VERSION 5.7 ;
BUSBITCHARS "[]" ;
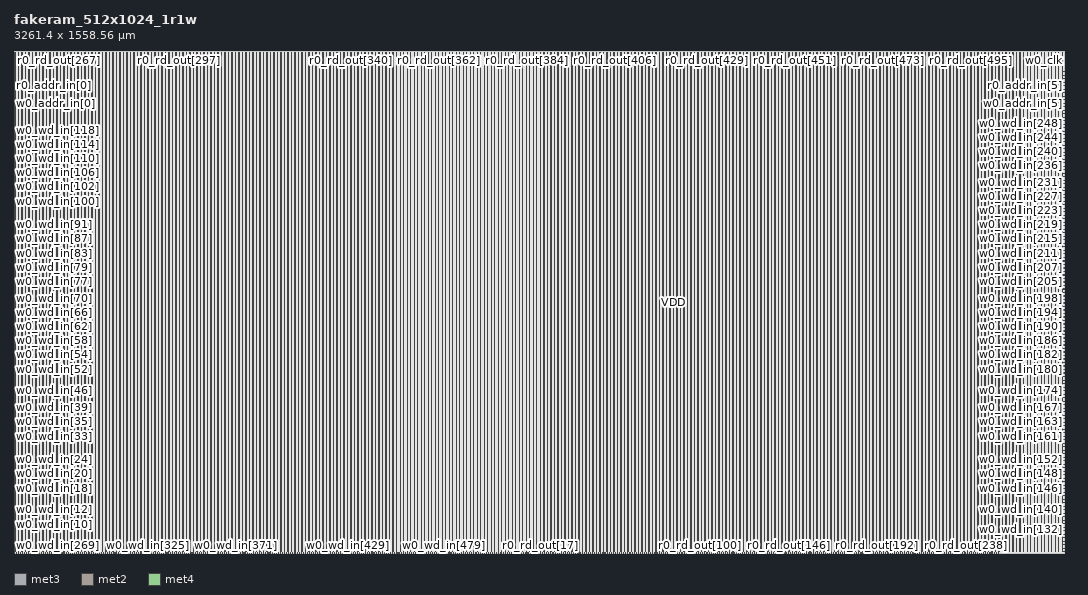
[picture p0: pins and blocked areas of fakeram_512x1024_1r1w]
MACRO fakeram_512x1024_1r1w
  FOREIGN fakeram_512x1024_1r1w 0 0 ;
  SYMMETRY X Y R90 ;
  SIZE 3261.400 BY 1558.560 ;
  CLASS BLOCK ;
  PIN w0_wd_in[0]
    DIRECTION INPUT ;
    USE SIGNAL ;
    SHAPE ABUTMENT ;
    PORT
      LAYER met3 ;
      RECT 0.000 3.930 0.900 4.230 ;
    END
  END w0_wd_in[0]
  PIN w0_wd_in[1]
    DIRECTION INPUT ;
    USE SIGNAL ;
    SHAPE ABUTMENT ;
    PORT
      LAYER met3 ;
      RECT 0.000 14.810 0.900 15.110 ;
    END
  END w0_wd_in[1]
  PIN w0_wd_in[2]
    DIRECTION INPUT ;
    USE SIGNAL ;
    SHAPE ABUTMENT ;
    PORT
      LAYER met3 ;
      RECT 0.000 25.690 0.900 25.990 ;
    END
  END w0_wd_in[2]
  PIN w0_wd_in[3]
    DIRECTION INPUT ;
    USE SIGNAL ;
    SHAPE ABUTMENT ;
    PORT
      LAYER met3 ;
      RECT 0.000 36.570 0.900 36.870 ;
    END
  END w0_wd_in[3]
  PIN w0_wd_in[4]
    DIRECTION INPUT ;
    USE SIGNAL ;
    SHAPE ABUTMENT ;
    PORT
      LAYER met3 ;
      RECT 0.000 47.450 0.900 47.750 ;
    END
  END w0_wd_in[4]
  PIN w0_wd_in[5]
    DIRECTION INPUT ;
    USE SIGNAL ;
    SHAPE ABUTMENT ;
    PORT
      LAYER met3 ;
      RECT 0.000 58.330 0.900 58.630 ;
    END
  END w0_wd_in[5]
  PIN w0_wd_in[6]
    DIRECTION INPUT ;
    USE SIGNAL ;
    SHAPE ABUTMENT ;
    PORT
      LAYER met3 ;
      RECT 0.000 69.210 0.900 69.510 ;
    END
  END w0_wd_in[6]
  PIN w0_wd_in[7]
    DIRECTION INPUT ;
    USE SIGNAL ;
    SHAPE ABUTMENT ;
    PORT
      LAYER met3 ;
      RECT 0.000 80.090 0.900 80.390 ;
    END
  END w0_wd_in[7]
  PIN w0_wd_in[8]
    DIRECTION INPUT ;
    USE SIGNAL ;
    SHAPE ABUTMENT ;
    PORT
      LAYER met3 ;
      RECT 0.000 90.970 0.900 91.270 ;
    END
  END w0_wd_in[8]
  PIN w0_wd_in[9]
    DIRECTION INPUT ;
    USE SIGNAL ;
    SHAPE ABUTMENT ;
    PORT
      LAYER met3 ;
      RECT 0.000 101.850 0.900 102.150 ;
    END
  END w0_wd_in[9]
  PIN w0_wd_in[10]
    DIRECTION INPUT ;
    USE SIGNAL ;
    SHAPE ABUTMENT ;
    PORT
      LAYER met3 ;
      RECT 0.000 112.730 0.900 113.030 ;
    END
  END w0_wd_in[10]
  PIN w0_wd_in[11]
    DIRECTION INPUT ;
    USE SIGNAL ;
    SHAPE ABUTMENT ;
    PORT
      LAYER met3 ;
      RECT 0.000 123.610 0.900 123.910 ;
    END
  END w0_wd_in[11]
  PIN w0_wd_in[12]
    DIRECTION INPUT ;
    USE SIGNAL ;
    SHAPE ABUTMENT ;
    PORT
      LAYER met3 ;
      RECT 0.000 134.490 0.900 134.790 ;
    END
  END w0_wd_in[12]
  PIN w0_wd_in[13]
    DIRECTION INPUT ;
    USE SIGNAL ;
    SHAPE ABUTMENT ;
    PORT
      LAYER met3 ;
      RECT 0.000 145.370 0.900 145.670 ;
    END
  END w0_wd_in[13]
  PIN w0_wd_in[14]
    DIRECTION INPUT ;
    USE SIGNAL ;
    SHAPE ABUTMENT ;
    PORT
      LAYER met3 ;
      RECT 0.000 156.250 0.900 156.550 ;
    END
  END w0_wd_in[14]
  PIN w0_wd_in[15]
    DIRECTION INPUT ;
    USE SIGNAL ;
    SHAPE ABUTMENT ;
    PORT
      LAYER met3 ;
      RECT 0.000 167.130 0.900 167.430 ;
    END
  END w0_wd_in[15]
  PIN w0_wd_in[16]
    DIRECTION INPUT ;
    USE SIGNAL ;
    SHAPE ABUTMENT ;
    PORT
      LAYER met3 ;
      RECT 0.000 178.010 0.900 178.310 ;
    END
  END w0_wd_in[16]
  PIN w0_wd_in[17]
    DIRECTION INPUT ;
    USE SIGNAL ;
    SHAPE ABUTMENT ;
    PORT
      LAYER met3 ;
      RECT 0.000 188.890 0.900 189.190 ;
    END
  END w0_wd_in[17]
  PIN w0_wd_in[18]
    DIRECTION INPUT ;
    USE SIGNAL ;
    SHAPE ABUTMENT ;
    PORT
      LAYER met3 ;
      RECT 0.000 199.770 0.900 200.070 ;
    END
  END w0_wd_in[18]
  PIN w0_wd_in[19]
    DIRECTION INPUT ;
    USE SIGNAL ;
    SHAPE ABUTMENT ;
    PORT
      LAYER met3 ;
      RECT 0.000 210.650 0.900 210.950 ;
    END
  END w0_wd_in[19]
  PIN w0_wd_in[20]
    DIRECTION INPUT ;
    USE SIGNAL ;
    SHAPE ABUTMENT ;
    PORT
      LAYER met3 ;
      RECT 0.000 221.530 0.900 221.830 ;
    END
  END w0_wd_in[20]
  PIN w0_wd_in[21]
    DIRECTION INPUT ;
    USE SIGNAL ;
    SHAPE ABUTMENT ;
    PORT
      LAYER met3 ;
      RECT 0.000 232.410 0.900 232.710 ;
    END
  END w0_wd_in[21]
  PIN w0_wd_in[22]
    DIRECTION INPUT ;
    USE SIGNAL ;
    SHAPE ABUTMENT ;
    PORT
      LAYER met3 ;
      RECT 0.000 243.290 0.900 243.590 ;
    END
  END w0_wd_in[22]
  PIN w0_wd_in[23]
    DIRECTION INPUT ;
    USE SIGNAL ;
    SHAPE ABUTMENT ;
    PORT
      LAYER met3 ;
      RECT 0.000 254.170 0.900 254.470 ;
    END
  END w0_wd_in[23]
  PIN w0_wd_in[24]
    DIRECTION INPUT ;
    USE SIGNAL ;
    SHAPE ABUTMENT ;
    PORT
      LAYER met3 ;
      RECT 0.000 265.050 0.900 265.350 ;
    END
  END w0_wd_in[24]
  PIN w0_wd_in[25]
    DIRECTION INPUT ;
    USE SIGNAL ;
    SHAPE ABUTMENT ;
    PORT
      LAYER met3 ;
      RECT 0.000 275.930 0.900 276.230 ;
    END
  END w0_wd_in[25]
  PIN w0_wd_in[26]
    DIRECTION INPUT ;
    USE SIGNAL ;
    SHAPE ABUTMENT ;
    PORT
      LAYER met3 ;
      RECT 0.000 286.810 0.900 287.110 ;
    END
  END w0_wd_in[26]
  PIN w0_wd_in[27]
    DIRECTION INPUT ;
    USE SIGNAL ;
    SHAPE ABUTMENT ;
    PORT
      LAYER met3 ;
      RECT 0.000 297.690 0.900 297.990 ;
    END
  END w0_wd_in[27]
  PIN w0_wd_in[28]
    DIRECTION INPUT ;
    USE SIGNAL ;
    SHAPE ABUTMENT ;
    PORT
      LAYER met3 ;
      RECT 0.000 308.570 0.900 308.870 ;
    END
  END w0_wd_in[28]
  PIN w0_wd_in[29]
    DIRECTION INPUT ;
    USE SIGNAL ;
    SHAPE ABUTMENT ;
    PORT
      LAYER met3 ;
      RECT 0.000 319.450 0.900 319.750 ;
    END
  END w0_wd_in[29]
  PIN w0_wd_in[30]
    DIRECTION INPUT ;
    USE SIGNAL ;
    SHAPE ABUTMENT ;
    PORT
      LAYER met3 ;
      RECT 0.000 330.330 0.900 330.630 ;
    END
  END w0_wd_in[30]
  PIN w0_wd_in[31]
    DIRECTION INPUT ;
    USE SIGNAL ;
    SHAPE ABUTMENT ;
    PORT
      LAYER met3 ;
      RECT 0.000 341.210 0.900 341.510 ;
    END
  END w0_wd_in[31]
  PIN w0_wd_in[32]
    DIRECTION INPUT ;
    USE SIGNAL ;
    SHAPE ABUTMENT ;
    PORT
      LAYER met3 ;
      RECT 0.000 352.090 0.900 352.390 ;
    END
  END w0_wd_in[32]
  PIN w0_wd_in[33]
    DIRECTION INPUT ;
    USE SIGNAL ;
    SHAPE ABUTMENT ;
    PORT
      LAYER met3 ;
      RECT 0.000 362.970 0.900 363.270 ;
    END
  END w0_wd_in[33]
  PIN w0_wd_in[34]
    DIRECTION INPUT ;
    USE SIGNAL ;
    SHAPE ABUTMENT ;
    PORT
      LAYER met3 ;
      RECT 0.000 373.850 0.900 374.150 ;
    END
  END w0_wd_in[34]
  PIN w0_wd_in[35]
    DIRECTION INPUT ;
    USE SIGNAL ;
    SHAPE ABUTMENT ;
    PORT
      LAYER met3 ;
      RECT 0.000 384.730 0.900 385.030 ;
    END
  END w0_wd_in[35]
  PIN w0_wd_in[36]
    DIRECTION INPUT ;
    USE SIGNAL ;
    SHAPE ABUTMENT ;
    PORT
      LAYER met3 ;
      RECT 0.000 395.610 0.900 395.910 ;
    END
  END w0_wd_in[36]
  PIN w0_wd_in[37]
    DIRECTION INPUT ;
    USE SIGNAL ;
    SHAPE ABUTMENT ;
    PORT
      LAYER met3 ;
      RECT 0.000 406.490 0.900 406.790 ;
    END
  END w0_wd_in[37]
  PIN w0_wd_in[38]
    DIRECTION INPUT ;
    USE SIGNAL ;
    SHAPE ABUTMENT ;
    PORT
      LAYER met3 ;
      RECT 0.000 417.370 0.900 417.670 ;
    END
  END w0_wd_in[38]
  PIN w0_wd_in[39]
    DIRECTION INPUT ;
    USE SIGNAL ;
    SHAPE ABUTMENT ;
    PORT
      LAYER met3 ;
      RECT 0.000 428.250 0.900 428.550 ;
    END
  END w0_wd_in[39]
  PIN w0_wd_in[40]
    DIRECTION INPUT ;
    USE SIGNAL ;
    SHAPE ABUTMENT ;
    PORT
      LAYER met3 ;
      RECT 0.000 439.130 0.900 439.430 ;
    END
  END w0_wd_in[40]
  PIN w0_wd_in[41]
    DIRECTION INPUT ;
    USE SIGNAL ;
    SHAPE ABUTMENT ;
    PORT
      LAYER met3 ;
      RECT 0.000 450.010 0.900 450.310 ;
    END
  END w0_wd_in[41]
  PIN w0_wd_in[42]
    DIRECTION INPUT ;
    USE SIGNAL ;
    SHAPE ABUTMENT ;
    PORT
      LAYER met3 ;
      RECT 0.000 460.890 0.900 461.190 ;
    END
  END w0_wd_in[42]
  PIN w0_wd_in[43]
    DIRECTION INPUT ;
    USE SIGNAL ;
    SHAPE ABUTMENT ;
    PORT
      LAYER met3 ;
      RECT 0.000 471.770 0.900 472.070 ;
    END
  END w0_wd_in[43]
  PIN w0_wd_in[44]
    DIRECTION INPUT ;
    USE SIGNAL ;
    SHAPE ABUTMENT ;
    PORT
      LAYER met3 ;
      RECT 0.000 482.650 0.900 482.950 ;
    END
  END w0_wd_in[44]
  PIN w0_wd_in[45]
    DIRECTION INPUT ;
    USE SIGNAL ;
    SHAPE ABUTMENT ;
    PORT
      LAYER met3 ;
      RECT 0.000 493.530 0.900 493.830 ;
    END
  END w0_wd_in[45]
  PIN w0_wd_in[46]
    DIRECTION INPUT ;
    USE SIGNAL ;
    SHAPE ABUTMENT ;
    PORT
      LAYER met3 ;
      RECT 0.000 504.410 0.900 504.710 ;
    END
  END w0_wd_in[46]
  PIN w0_wd_in[47]
    DIRECTION INPUT ;
    USE SIGNAL ;
    SHAPE ABUTMENT ;
    PORT
      LAYER met3 ;
      RECT 0.000 515.290 0.900 515.590 ;
    END
  END w0_wd_in[47]
  PIN w0_wd_in[48]
    DIRECTION INPUT ;
    USE SIGNAL ;
    SHAPE ABUTMENT ;
    PORT
      LAYER met3 ;
      RECT 0.000 526.170 0.900 526.470 ;
    END
  END w0_wd_in[48]
  PIN w0_wd_in[49]
    DIRECTION INPUT ;
    USE SIGNAL ;
    SHAPE ABUTMENT ;
    PORT
      LAYER met3 ;
      RECT 0.000 537.050 0.900 537.350 ;
    END
  END w0_wd_in[49]
  PIN w0_wd_in[50]
    DIRECTION INPUT ;
    USE SIGNAL ;
    SHAPE ABUTMENT ;
    PORT
      LAYER met3 ;
      RECT 0.000 547.930 0.900 548.230 ;
    END
  END w0_wd_in[50]
  PIN w0_wd_in[51]
    DIRECTION INPUT ;
    USE SIGNAL ;
    SHAPE ABUTMENT ;
    PORT
      LAYER met3 ;
      RECT 0.000 558.810 0.900 559.110 ;
    END
  END w0_wd_in[51]
  PIN w0_wd_in[52]
    DIRECTION INPUT ;
    USE SIGNAL ;
    SHAPE ABUTMENT ;
    PORT
      LAYER met3 ;
      RECT 0.000 569.690 0.900 569.990 ;
    END
  END w0_wd_in[52]
  PIN w0_wd_in[53]
    DIRECTION INPUT ;
    USE SIGNAL ;
    SHAPE ABUTMENT ;
    PORT
      LAYER met3 ;
      RECT 0.000 580.570 0.900 580.870 ;
    END
  END w0_wd_in[53]
  PIN w0_wd_in[54]
    DIRECTION INPUT ;
    USE SIGNAL ;
    SHAPE ABUTMENT ;
    PORT
      LAYER met3 ;
      RECT 0.000 591.450 0.900 591.750 ;
    END
  END w0_wd_in[54]
  PIN w0_wd_in[55]
    DIRECTION INPUT ;
    USE SIGNAL ;
    SHAPE ABUTMENT ;
    PORT
      LAYER met3 ;
      RECT 0.000 602.330 0.900 602.630 ;
    END
  END w0_wd_in[55]
  PIN w0_wd_in[56]
    DIRECTION INPUT ;
    USE SIGNAL ;
    SHAPE ABUTMENT ;
    PORT
      LAYER met3 ;
      RECT 0.000 613.210 0.900 613.510 ;
    END
  END w0_wd_in[56]
  PIN w0_wd_in[57]
    DIRECTION INPUT ;
    USE SIGNAL ;
    SHAPE ABUTMENT ;
    PORT
      LAYER met3 ;
      RECT 0.000 624.090 0.900 624.390 ;
    END
  END w0_wd_in[57]
  PIN w0_wd_in[58]
    DIRECTION INPUT ;
    USE SIGNAL ;
    SHAPE ABUTMENT ;
    PORT
      LAYER met3 ;
      RECT 0.000 634.970 0.900 635.270 ;
    END
  END w0_wd_in[58]
  PIN w0_wd_in[59]
    DIRECTION INPUT ;
    USE SIGNAL ;
    SHAPE ABUTMENT ;
    PORT
      LAYER met3 ;
      RECT 0.000 645.850 0.900 646.150 ;
    END
  END w0_wd_in[59]
  PIN w0_wd_in[60]
    DIRECTION INPUT ;
    USE SIGNAL ;
    SHAPE ABUTMENT ;
    PORT
      LAYER met3 ;
      RECT 0.000 656.730 0.900 657.030 ;
    END
  END w0_wd_in[60]
  PIN w0_wd_in[61]
    DIRECTION INPUT ;
    USE SIGNAL ;
    SHAPE ABUTMENT ;
    PORT
      LAYER met3 ;
      RECT 0.000 667.610 0.900 667.910 ;
    END
  END w0_wd_in[61]
  PIN w0_wd_in[62]
    DIRECTION INPUT ;
    USE SIGNAL ;
    SHAPE ABUTMENT ;
    PORT
      LAYER met3 ;
      RECT 0.000 678.490 0.900 678.790 ;
    END
  END w0_wd_in[62]
  PIN w0_wd_in[63]
    DIRECTION INPUT ;
    USE SIGNAL ;
    SHAPE ABUTMENT ;
    PORT
      LAYER met3 ;
      RECT 0.000 689.370 0.900 689.670 ;
    END
  END w0_wd_in[63]
  PIN w0_wd_in[64]
    DIRECTION INPUT ;
    USE SIGNAL ;
    SHAPE ABUTMENT ;
    PORT
      LAYER met3 ;
      RECT 0.000 700.250 0.900 700.550 ;
    END
  END w0_wd_in[64]
  PIN w0_wd_in[65]
    DIRECTION INPUT ;
    USE SIGNAL ;
    SHAPE ABUTMENT ;
    PORT
      LAYER met3 ;
      RECT 0.000 711.130 0.900 711.430 ;
    END
  END w0_wd_in[65]
  PIN w0_wd_in[66]
    DIRECTION INPUT ;
    USE SIGNAL ;
    SHAPE ABUTMENT ;
    PORT
      LAYER met3 ;
      RECT 0.000 722.010 0.900 722.310 ;
    END
  END w0_wd_in[66]
  PIN w0_wd_in[67]
    DIRECTION INPUT ;
    USE SIGNAL ;
    SHAPE ABUTMENT ;
    PORT
      LAYER met3 ;
      RECT 0.000 732.890 0.900 733.190 ;
    END
  END w0_wd_in[67]
  PIN w0_wd_in[68]
    DIRECTION INPUT ;
    USE SIGNAL ;
    SHAPE ABUTMENT ;
    PORT
      LAYER met3 ;
      RECT 0.000 743.770 0.900 744.070 ;
    END
  END w0_wd_in[68]
  PIN w0_wd_in[69]
    DIRECTION INPUT ;
    USE SIGNAL ;
    SHAPE ABUTMENT ;
    PORT
      LAYER met3 ;
      RECT 0.000 754.650 0.900 754.950 ;
    END
  END w0_wd_in[69]
  PIN w0_wd_in[70]
    DIRECTION INPUT ;
    USE SIGNAL ;
    SHAPE ABUTMENT ;
    PORT
      LAYER met3 ;
      RECT 0.000 765.530 0.900 765.830 ;
    END
  END w0_wd_in[70]
  PIN w0_wd_in[71]
    DIRECTION INPUT ;
    USE SIGNAL ;
    SHAPE ABUTMENT ;
    PORT
      LAYER met3 ;
      RECT 0.000 776.410 0.900 776.710 ;
    END
  END w0_wd_in[71]
  PIN w0_wd_in[72]
    DIRECTION INPUT ;
    USE SIGNAL ;
    SHAPE ABUTMENT ;
    PORT
      LAYER met3 ;
      RECT 0.000 787.290 0.900 787.590 ;
    END
  END w0_wd_in[72]
  PIN w0_wd_in[73]
    DIRECTION INPUT ;
    USE SIGNAL ;
    SHAPE ABUTMENT ;
    PORT
      LAYER met3 ;
      RECT 0.000 798.170 0.900 798.470 ;
    END
  END w0_wd_in[73]
  PIN w0_wd_in[74]
    DIRECTION INPUT ;
    USE SIGNAL ;
    SHAPE ABUTMENT ;
    PORT
      LAYER met3 ;
      RECT 0.000 809.050 0.900 809.350 ;
    END
  END w0_wd_in[74]
  PIN w0_wd_in[75]
    DIRECTION INPUT ;
    USE SIGNAL ;
    SHAPE ABUTMENT ;
    PORT
      LAYER met3 ;
      RECT 0.000 819.930 0.900 820.230 ;
    END
  END w0_wd_in[75]
  PIN w0_wd_in[76]
    DIRECTION INPUT ;
    USE SIGNAL ;
    SHAPE ABUTMENT ;
    PORT
      LAYER met3 ;
      RECT 0.000 830.810 0.900 831.110 ;
    END
  END w0_wd_in[76]
  PIN w0_wd_in[77]
    DIRECTION INPUT ;
    USE SIGNAL ;
    SHAPE ABUTMENT ;
    PORT
      LAYER met3 ;
      RECT 0.000 841.690 0.900 841.990 ;
    END
  END w0_wd_in[77]
  PIN w0_wd_in[78]
    DIRECTION INPUT ;
    USE SIGNAL ;
    SHAPE ABUTMENT ;
    PORT
      LAYER met3 ;
      RECT 0.000 852.570 0.900 852.870 ;
    END
  END w0_wd_in[78]
  PIN w0_wd_in[79]
    DIRECTION INPUT ;
    USE SIGNAL ;
    SHAPE ABUTMENT ;
    PORT
      LAYER met3 ;
      RECT 0.000 863.450 0.900 863.750 ;
    END
  END w0_wd_in[79]
  PIN w0_wd_in[80]
    DIRECTION INPUT ;
    USE SIGNAL ;
    SHAPE ABUTMENT ;
    PORT
      LAYER met3 ;
      RECT 0.000 874.330 0.900 874.630 ;
    END
  END w0_wd_in[80]
  PIN w0_wd_in[81]
    DIRECTION INPUT ;
    USE SIGNAL ;
    SHAPE ABUTMENT ;
    PORT
      LAYER met3 ;
      RECT 0.000 885.210 0.900 885.510 ;
    END
  END w0_wd_in[81]
  PIN w0_wd_in[82]
    DIRECTION INPUT ;
    USE SIGNAL ;
    SHAPE ABUTMENT ;
    PORT
      LAYER met3 ;
      RECT 0.000 896.090 0.900 896.390 ;
    END
  END w0_wd_in[82]
  PIN w0_wd_in[83]
    DIRECTION INPUT ;
    USE SIGNAL ;
    SHAPE ABUTMENT ;
    PORT
      LAYER met3 ;
      RECT 0.000 906.970 0.900 907.270 ;
    END
  END w0_wd_in[83]
  PIN w0_wd_in[84]
    DIRECTION INPUT ;
    USE SIGNAL ;
    SHAPE ABUTMENT ;
    PORT
      LAYER met3 ;
      RECT 0.000 917.850 0.900 918.150 ;
    END
  END w0_wd_in[84]
  PIN w0_wd_in[85]
    DIRECTION INPUT ;
    USE SIGNAL ;
    SHAPE ABUTMENT ;
    PORT
      LAYER met3 ;
      RECT 0.000 928.730 0.900 929.030 ;
    END
  END w0_wd_in[85]
  PIN w0_wd_in[86]
    DIRECTION INPUT ;
    USE SIGNAL ;
    SHAPE ABUTMENT ;
    PORT
      LAYER met3 ;
      RECT 0.000 939.610 0.900 939.910 ;
    END
  END w0_wd_in[86]
  PIN w0_wd_in[87]
    DIRECTION INPUT ;
    USE SIGNAL ;
    SHAPE ABUTMENT ;
    PORT
      LAYER met3 ;
      RECT 0.000 950.490 0.900 950.790 ;
    END
  END w0_wd_in[87]
  PIN w0_wd_in[88]
    DIRECTION INPUT ;
    USE SIGNAL ;
    SHAPE ABUTMENT ;
    PORT
      LAYER met3 ;
      RECT 0.000 961.370 0.900 961.670 ;
    END
  END w0_wd_in[88]
  PIN w0_wd_in[89]
    DIRECTION INPUT ;
    USE SIGNAL ;
    SHAPE ABUTMENT ;
    PORT
      LAYER met3 ;
      RECT 0.000 972.250 0.900 972.550 ;
    END
  END w0_wd_in[89]
  PIN w0_wd_in[90]
    DIRECTION INPUT ;
    USE SIGNAL ;
    SHAPE ABUTMENT ;
    PORT
      LAYER met3 ;
      RECT 0.000 983.130 0.900 983.430 ;
    END
  END w0_wd_in[90]
  PIN w0_wd_in[91]
    DIRECTION INPUT ;
    USE SIGNAL ;
    SHAPE ABUTMENT ;
    PORT
      LAYER met3 ;
      RECT 0.000 994.010 0.900 994.310 ;
    END
  END w0_wd_in[91]
  PIN w0_wd_in[92]
    DIRECTION INPUT ;
    USE SIGNAL ;
    SHAPE ABUTMENT ;
    PORT
      LAYER met3 ;
      RECT 0.000 1004.890 0.900 1005.190 ;
    END
  END w0_wd_in[92]
  PIN w0_wd_in[93]
    DIRECTION INPUT ;
    USE SIGNAL ;
    SHAPE ABUTMENT ;
    PORT
      LAYER met3 ;
      RECT 0.000 1015.770 0.900 1016.070 ;
    END
  END w0_wd_in[93]
  PIN w0_wd_in[94]
    DIRECTION INPUT ;
    USE SIGNAL ;
    SHAPE ABUTMENT ;
    PORT
      LAYER met3 ;
      RECT 0.000 1026.650 0.900 1026.950 ;
    END
  END w0_wd_in[94]
  PIN w0_wd_in[95]
    DIRECTION INPUT ;
    USE SIGNAL ;
    SHAPE ABUTMENT ;
    PORT
      LAYER met3 ;
      RECT 0.000 1037.530 0.900 1037.830 ;
    END
  END w0_wd_in[95]
  PIN w0_wd_in[96]
    DIRECTION INPUT ;
    USE SIGNAL ;
    SHAPE ABUTMENT ;
    PORT
      LAYER met3 ;
      RECT 0.000 1048.410 0.900 1048.710 ;
    END
  END w0_wd_in[96]
  PIN w0_wd_in[97]
    DIRECTION INPUT ;
    USE SIGNAL ;
    SHAPE ABUTMENT ;
    PORT
      LAYER met3 ;
      RECT 0.000 1059.290 0.900 1059.590 ;
    END
  END w0_wd_in[97]
  PIN w0_wd_in[98]
    DIRECTION INPUT ;
    USE SIGNAL ;
    SHAPE ABUTMENT ;
    PORT
      LAYER met3 ;
      RECT 0.000 1070.170 0.900 1070.470 ;
    END
  END w0_wd_in[98]
  PIN w0_wd_in[99]
    DIRECTION INPUT ;
    USE SIGNAL ;
    SHAPE ABUTMENT ;
    PORT
      LAYER met3 ;
      RECT 0.000 1081.050 0.900 1081.350 ;
    END
  END w0_wd_in[99]
  PIN w0_wd_in[100]
    DIRECTION INPUT ;
    USE SIGNAL ;
    SHAPE ABUTMENT ;
    PORT
      LAYER met3 ;
      RECT 0.000 1091.930 0.900 1092.230 ;
    END
  END w0_wd_in[100]
  PIN w0_wd_in[101]
    DIRECTION INPUT ;
    USE SIGNAL ;
    SHAPE ABUTMENT ;
    PORT
      LAYER met3 ;
      RECT 0.000 1102.810 0.900 1103.110 ;
    END
  END w0_wd_in[101]
  PIN w0_wd_in[102]
    DIRECTION INPUT ;
    USE SIGNAL ;
    SHAPE ABUTMENT ;
    PORT
      LAYER met3 ;
      RECT 0.000 1113.690 0.900 1113.990 ;
    END
  END w0_wd_in[102]
  PIN w0_wd_in[103]
    DIRECTION INPUT ;
    USE SIGNAL ;
    SHAPE ABUTMENT ;
    PORT
      LAYER met3 ;
      RECT 0.000 1124.570 0.900 1124.870 ;
    END
  END w0_wd_in[103]
  PIN w0_wd_in[104]
    DIRECTION INPUT ;
    USE SIGNAL ;
    SHAPE ABUTMENT ;
    PORT
      LAYER met3 ;
      RECT 0.000 1135.450 0.900 1135.750 ;
    END
  END w0_wd_in[104]
  PIN w0_wd_in[105]
    DIRECTION INPUT ;
    USE SIGNAL ;
    SHAPE ABUTMENT ;
    PORT
      LAYER met3 ;
      RECT 0.000 1146.330 0.900 1146.630 ;
    END
  END w0_wd_in[105]
  PIN w0_wd_in[106]
    DIRECTION INPUT ;
    USE SIGNAL ;
    SHAPE ABUTMENT ;
    PORT
      LAYER met3 ;
      RECT 0.000 1157.210 0.900 1157.510 ;
    END
  END w0_wd_in[106]
  PIN w0_wd_in[107]
    DIRECTION INPUT ;
    USE SIGNAL ;
    SHAPE ABUTMENT ;
    PORT
      LAYER met3 ;
      RECT 0.000 1168.090 0.900 1168.390 ;
    END
  END w0_wd_in[107]
  PIN w0_wd_in[108]
    DIRECTION INPUT ;
    USE SIGNAL ;
    SHAPE ABUTMENT ;
    PORT
      LAYER met3 ;
      RECT 0.000 1178.970 0.900 1179.270 ;
    END
  END w0_wd_in[108]
  PIN w0_wd_in[109]
    DIRECTION INPUT ;
    USE SIGNAL ;
    SHAPE ABUTMENT ;
    PORT
      LAYER met3 ;
      RECT 0.000 1189.850 0.900 1190.150 ;
    END
  END w0_wd_in[109]
  PIN w0_wd_in[110]
    DIRECTION INPUT ;
    USE SIGNAL ;
    SHAPE ABUTMENT ;
    PORT
      LAYER met3 ;
      RECT 0.000 1200.730 0.900 1201.030 ;
    END
  END w0_wd_in[110]
  PIN w0_wd_in[111]
    DIRECTION INPUT ;
    USE SIGNAL ;
    SHAPE ABUTMENT ;
    PORT
      LAYER met3 ;
      RECT 0.000 1211.610 0.900 1211.910 ;
    END
  END w0_wd_in[111]
  PIN w0_wd_in[112]
    DIRECTION INPUT ;
    USE SIGNAL ;
    SHAPE ABUTMENT ;
    PORT
      LAYER met3 ;
      RECT 0.000 1222.490 0.900 1222.790 ;
    END
  END w0_wd_in[112]
  PIN w0_wd_in[113]
    DIRECTION INPUT ;
    USE SIGNAL ;
    SHAPE ABUTMENT ;
    PORT
      LAYER met3 ;
      RECT 0.000 1233.370 0.900 1233.670 ;
    END
  END w0_wd_in[113]
  PIN w0_wd_in[114]
    DIRECTION INPUT ;
    USE SIGNAL ;
    SHAPE ABUTMENT ;
    PORT
      LAYER met3 ;
      RECT 0.000 1244.250 0.900 1244.550 ;
    END
  END w0_wd_in[114]
  PIN w0_wd_in[115]
    DIRECTION INPUT ;
    USE SIGNAL ;
    SHAPE ABUTMENT ;
    PORT
      LAYER met3 ;
      RECT 0.000 1255.130 0.900 1255.430 ;
    END
  END w0_wd_in[115]
  PIN w0_wd_in[116]
    DIRECTION INPUT ;
    USE SIGNAL ;
    SHAPE ABUTMENT ;
    PORT
      LAYER met3 ;
      RECT 0.000 1266.010 0.900 1266.310 ;
    END
  END w0_wd_in[116]
  PIN w0_wd_in[117]
    DIRECTION INPUT ;
    USE SIGNAL ;
    SHAPE ABUTMENT ;
    PORT
      LAYER met3 ;
      RECT 0.000 1276.890 0.900 1277.190 ;
    END
  END w0_wd_in[117]
  PIN w0_wd_in[118]
    DIRECTION INPUT ;
    USE SIGNAL ;
    SHAPE ABUTMENT ;
    PORT
      LAYER met3 ;
      RECT 0.000 1287.770 0.900 1288.070 ;
    END
  END w0_wd_in[118]
  PIN w0_wd_in[119]
    DIRECTION INPUT ;
    USE SIGNAL ;
    SHAPE ABUTMENT ;
    PORT
      LAYER met3 ;
      RECT 0.000 1298.650 0.900 1298.950 ;
    END
  END w0_wd_in[119]
  PIN w0_wd_in[120]
    DIRECTION INPUT ;
    USE SIGNAL ;
    SHAPE ABUTMENT ;
    PORT
      LAYER met3 ;
      RECT 0.000 1309.530 0.900 1309.830 ;
    END
  END w0_wd_in[120]
  PIN w0_wd_in[121]
    DIRECTION INPUT ;
    USE SIGNAL ;
    SHAPE ABUTMENT ;
    PORT
      LAYER met3 ;
      RECT 0.000 1320.410 0.900 1320.710 ;
    END
  END w0_wd_in[121]
  PIN w0_wd_in[122]
    DIRECTION INPUT ;
    USE SIGNAL ;
    SHAPE ABUTMENT ;
    PORT
      LAYER met3 ;
      RECT 0.000 1331.290 0.900 1331.590 ;
    END
  END w0_wd_in[122]
  PIN w0_wd_in[123]
    DIRECTION INPUT ;
    USE SIGNAL ;
    SHAPE ABUTMENT ;
    PORT
      LAYER met3 ;
      RECT 0.000 1342.170 0.900 1342.470 ;
    END
  END w0_wd_in[123]
  PIN w0_wd_in[124]
    DIRECTION INPUT ;
    USE SIGNAL ;
    SHAPE ABUTMENT ;
    PORT
      LAYER met3 ;
      RECT 0.000 1353.050 0.900 1353.350 ;
    END
  END w0_wd_in[124]
  PIN w0_wd_in[125]
    DIRECTION INPUT ;
    USE SIGNAL ;
    SHAPE ABUTMENT ;
    PORT
      LAYER met3 ;
      RECT 0.000 1363.930 0.900 1364.230 ;
    END
  END w0_wd_in[125]
  PIN w0_wd_in[126]
    DIRECTION INPUT ;
    USE SIGNAL ;
    SHAPE ABUTMENT ;
    PORT
      LAYER met3 ;
      RECT 0.000 1374.810 0.900 1375.110 ;
    END
  END w0_wd_in[126]
  PIN w0_wd_in[127]
    DIRECTION INPUT ;
    USE SIGNAL ;
    SHAPE ABUTMENT ;
    PORT
      LAYER met3 ;
      RECT 0.000 1385.690 0.900 1385.990 ;
    END
  END w0_wd_in[127]
  PIN w0_wd_in[128]
    DIRECTION INPUT ;
    USE SIGNAL ;
    SHAPE ABUTMENT ;
    PORT
      LAYER met3 ;
      RECT 3260.500 3.930 3261.400 4.230 ;
    END
  END w0_wd_in[128]
  PIN w0_wd_in[129]
    DIRECTION INPUT ;
    USE SIGNAL ;
    SHAPE ABUTMENT ;
    PORT
      LAYER met3 ;
      RECT 3260.500 14.810 3261.400 15.110 ;
    END
  END w0_wd_in[129]
  PIN w0_wd_in[130]
    DIRECTION INPUT ;
    USE SIGNAL ;
    SHAPE ABUTMENT ;
    PORT
      LAYER met3 ;
      RECT 3260.500 25.690 3261.400 25.990 ;
    END
  END w0_wd_in[130]
  PIN w0_wd_in[131]
    DIRECTION INPUT ;
    USE SIGNAL ;
    SHAPE ABUTMENT ;
    PORT
      LAYER met3 ;
      RECT 3260.500 36.570 3261.400 36.870 ;
    END
  END w0_wd_in[131]
  PIN w0_wd_in[132]
    DIRECTION INPUT ;
    USE SIGNAL ;
    SHAPE ABUTMENT ;
    PORT
      LAYER met3 ;
      RECT 3260.500 47.450 3261.400 47.750 ;
    END
  END w0_wd_in[132]
  PIN w0_wd_in[133]
    DIRECTION INPUT ;
    USE SIGNAL ;
    SHAPE ABUTMENT ;
    PORT
      LAYER met3 ;
      RECT 3260.500 58.330 3261.400 58.630 ;
    END
  END w0_wd_in[133]
  PIN w0_wd_in[134]
    DIRECTION INPUT ;
    USE SIGNAL ;
    SHAPE ABUTMENT ;
    PORT
      LAYER met3 ;
      RECT 3260.500 69.210 3261.400 69.510 ;
    END
  END w0_wd_in[134]
  PIN w0_wd_in[135]
    DIRECTION INPUT ;
    USE SIGNAL ;
    SHAPE ABUTMENT ;
    PORT
      LAYER met3 ;
      RECT 3260.500 80.090 3261.400 80.390 ;
    END
  END w0_wd_in[135]
  PIN w0_wd_in[136]
    DIRECTION INPUT ;
    USE SIGNAL ;
    SHAPE ABUTMENT ;
    PORT
      LAYER met3 ;
      RECT 3260.500 90.970 3261.400 91.270 ;
    END
  END w0_wd_in[136]
  PIN w0_wd_in[137]
    DIRECTION INPUT ;
    USE SIGNAL ;
    SHAPE ABUTMENT ;
    PORT
      LAYER met3 ;
      RECT 3260.500 101.850 3261.400 102.150 ;
    END
  END w0_wd_in[137]
  PIN w0_wd_in[138]
    DIRECTION INPUT ;
    USE SIGNAL ;
    SHAPE ABUTMENT ;
    PORT
      LAYER met3 ;
      RECT 3260.500 112.730 3261.400 113.030 ;
    END
  END w0_wd_in[138]
  PIN w0_wd_in[139]
    DIRECTION INPUT ;
    USE SIGNAL ;
    SHAPE ABUTMENT ;
    PORT
      LAYER met3 ;
      RECT 3260.500 123.610 3261.400 123.910 ;
    END
  END w0_wd_in[139]
  PIN w0_wd_in[140]
    DIRECTION INPUT ;
    USE SIGNAL ;
    SHAPE ABUTMENT ;
    PORT
      LAYER met3 ;
      RECT 3260.500 134.490 3261.400 134.790 ;
    END
  END w0_wd_in[140]
  PIN w0_wd_in[141]
    DIRECTION INPUT ;
    USE SIGNAL ;
    SHAPE ABUTMENT ;
    PORT
      LAYER met3 ;
      RECT 3260.500 145.370 3261.400 145.670 ;
    END
  END w0_wd_in[141]
  PIN w0_wd_in[142]
    DIRECTION INPUT ;
    USE SIGNAL ;
    SHAPE ABUTMENT ;
    PORT
      LAYER met3 ;
      RECT 3260.500 156.250 3261.400 156.550 ;
    END
  END w0_wd_in[142]
  PIN w0_wd_in[143]
    DIRECTION INPUT ;
    USE SIGNAL ;
    SHAPE ABUTMENT ;
    PORT
      LAYER met3 ;
      RECT 3260.500 167.130 3261.400 167.430 ;
    END
  END w0_wd_in[143]
  PIN w0_wd_in[144]
    DIRECTION INPUT ;
    USE SIGNAL ;
    SHAPE ABUTMENT ;
    PORT
      LAYER met3 ;
      RECT 3260.500 178.010 3261.400 178.310 ;
    END
  END w0_wd_in[144]
  PIN w0_wd_in[145]
    DIRECTION INPUT ;
    USE SIGNAL ;
    SHAPE ABUTMENT ;
    PORT
      LAYER met3 ;
      RECT 3260.500 188.890 3261.400 189.190 ;
    END
  END w0_wd_in[145]
  PIN w0_wd_in[146]
    DIRECTION INPUT ;
    USE SIGNAL ;
    SHAPE ABUTMENT ;
    PORT
      LAYER met3 ;
      RECT 3260.500 199.770 3261.400 200.070 ;
    END
  END w0_wd_in[146]
  PIN w0_wd_in[147]
    DIRECTION INPUT ;
    USE SIGNAL ;
    SHAPE ABUTMENT ;
    PORT
      LAYER met3 ;
      RECT 3260.500 210.650 3261.400 210.950 ;
    END
  END w0_wd_in[147]
  PIN w0_wd_in[148]
    DIRECTION INPUT ;
    USE SIGNAL ;
    SHAPE ABUTMENT ;
    PORT
      LAYER met3 ;
      RECT 3260.500 221.530 3261.400 221.830 ;
    END
  END w0_wd_in[148]
  PIN w0_wd_in[149]
    DIRECTION INPUT ;
    USE SIGNAL ;
    SHAPE ABUTMENT ;
    PORT
      LAYER met3 ;
      RECT 3260.500 232.410 3261.400 232.710 ;
    END
  END w0_wd_in[149]
  PIN w0_wd_in[150]
    DIRECTION INPUT ;
    USE SIGNAL ;
    SHAPE ABUTMENT ;
    PORT
      LAYER met3 ;
      RECT 3260.500 243.290 3261.400 243.590 ;
    END
  END w0_wd_in[150]
  PIN w0_wd_in[151]
    DIRECTION INPUT ;
    USE SIGNAL ;
    SHAPE ABUTMENT ;
    PORT
      LAYER met3 ;
      RECT 3260.500 254.170 3261.400 254.470 ;
    END
  END w0_wd_in[151]
  PIN w0_wd_in[152]
    DIRECTION INPUT ;
    USE SIGNAL ;
    SHAPE ABUTMENT ;
    PORT
      LAYER met3 ;
      RECT 3260.500 265.050 3261.400 265.350 ;
    END
  END w0_wd_in[152]
  PIN w0_wd_in[153]
    DIRECTION INPUT ;
    USE SIGNAL ;
    SHAPE ABUTMENT ;
    PORT
      LAYER met3 ;
      RECT 3260.500 275.930 3261.400 276.230 ;
    END
  END w0_wd_in[153]
  PIN w0_wd_in[154]
    DIRECTION INPUT ;
    USE SIGNAL ;
    SHAPE ABUTMENT ;
    PORT
      LAYER met3 ;
      RECT 3260.500 286.810 3261.400 287.110 ;
    END
  END w0_wd_in[154]
  PIN w0_wd_in[155]
    DIRECTION INPUT ;
    USE SIGNAL ;
    SHAPE ABUTMENT ;
    PORT
      LAYER met3 ;
      RECT 3260.500 297.690 3261.400 297.990 ;
    END
  END w0_wd_in[155]
  PIN w0_wd_in[156]
    DIRECTION INPUT ;
    USE SIGNAL ;
    SHAPE ABUTMENT ;
    PORT
      LAYER met3 ;
      RECT 3260.500 308.570 3261.400 308.870 ;
    END
  END w0_wd_in[156]
  PIN w0_wd_in[157]
    DIRECTION INPUT ;
    USE SIGNAL ;
    SHAPE ABUTMENT ;
    PORT
      LAYER met3 ;
      RECT 3260.500 319.450 3261.400 319.750 ;
    END
  END w0_wd_in[157]
  PIN w0_wd_in[158]
    DIRECTION INPUT ;
    USE SIGNAL ;
    SHAPE ABUTMENT ;
    PORT
      LAYER met3 ;
      RECT 3260.500 330.330 3261.400 330.630 ;
    END
  END w0_wd_in[158]
  PIN w0_wd_in[159]
    DIRECTION INPUT ;
    USE SIGNAL ;
    SHAPE ABUTMENT ;
    PORT
      LAYER met3 ;
      RECT 3260.500 341.210 3261.400 341.510 ;
    END
  END w0_wd_in[159]
  PIN w0_wd_in[160]
    DIRECTION INPUT ;
    USE SIGNAL ;
    SHAPE ABUTMENT ;
    PORT
      LAYER met3 ;
      RECT 3260.500 352.090 3261.400 352.390 ;
    END
  END w0_wd_in[160]
  PIN w0_wd_in[161]
    DIRECTION INPUT ;
    USE SIGNAL ;
    SHAPE ABUTMENT ;
    PORT
      LAYER met3 ;
      RECT 3260.500 362.970 3261.400 363.270 ;
    END
  END w0_wd_in[161]
  PIN w0_wd_in[162]
    DIRECTION INPUT ;
    USE SIGNAL ;
    SHAPE ABUTMENT ;
    PORT
      LAYER met3 ;
      RECT 3260.500 373.850 3261.400 374.150 ;
    END
  END w0_wd_in[162]
  PIN w0_wd_in[163]
    DIRECTION INPUT ;
    USE SIGNAL ;
    SHAPE ABUTMENT ;
    PORT
      LAYER met3 ;
      RECT 3260.500 384.730 3261.400 385.030 ;
    END
  END w0_wd_in[163]
  PIN w0_wd_in[164]
    DIRECTION INPUT ;
    USE SIGNAL ;
    SHAPE ABUTMENT ;
    PORT
      LAYER met3 ;
      RECT 3260.500 395.610 3261.400 395.910 ;
    END
  END w0_wd_in[164]
  PIN w0_wd_in[165]
    DIRECTION INPUT ;
    USE SIGNAL ;
    SHAPE ABUTMENT ;
    PORT
      LAYER met3 ;
      RECT 3260.500 406.490 3261.400 406.790 ;
    END
  END w0_wd_in[165]
  PIN w0_wd_in[166]
    DIRECTION INPUT ;
    USE SIGNAL ;
    SHAPE ABUTMENT ;
    PORT
      LAYER met3 ;
      RECT 3260.500 417.370 3261.400 417.670 ;
    END
  END w0_wd_in[166]
  PIN w0_wd_in[167]
    DIRECTION INPUT ;
    USE SIGNAL ;
    SHAPE ABUTMENT ;
    PORT
      LAYER met3 ;
      RECT 3260.500 428.250 3261.400 428.550 ;
    END
  END w0_wd_in[167]
  PIN w0_wd_in[168]
    DIRECTION INPUT ;
    USE SIGNAL ;
    SHAPE ABUTMENT ;
    PORT
      LAYER met3 ;
      RECT 3260.500 439.130 3261.400 439.430 ;
    END
  END w0_wd_in[168]
  PIN w0_wd_in[169]
    DIRECTION INPUT ;
    USE SIGNAL ;
    SHAPE ABUTMENT ;
    PORT
      LAYER met3 ;
      RECT 3260.500 450.010 3261.400 450.310 ;
    END
  END w0_wd_in[169]
  PIN w0_wd_in[170]
    DIRECTION INPUT ;
    USE SIGNAL ;
    SHAPE ABUTMENT ;
    PORT
      LAYER met3 ;
      RECT 3260.500 460.890 3261.400 461.190 ;
    END
  END w0_wd_in[170]
  PIN w0_wd_in[171]
    DIRECTION INPUT ;
    USE SIGNAL ;
    SHAPE ABUTMENT ;
    PORT
      LAYER met3 ;
      RECT 3260.500 471.770 3261.400 472.070 ;
    END
  END w0_wd_in[171]
  PIN w0_wd_in[172]
    DIRECTION INPUT ;
    USE SIGNAL ;
    SHAPE ABUTMENT ;
    PORT
      LAYER met3 ;
      RECT 3260.500 482.650 3261.400 482.950 ;
    END
  END w0_wd_in[172]
  PIN w0_wd_in[173]
    DIRECTION INPUT ;
    USE SIGNAL ;
    SHAPE ABUTMENT ;
    PORT
      LAYER met3 ;
      RECT 3260.500 493.530 3261.400 493.830 ;
    END
  END w0_wd_in[173]
  PIN w0_wd_in[174]
    DIRECTION INPUT ;
    USE SIGNAL ;
    SHAPE ABUTMENT ;
    PORT
      LAYER met3 ;
      RECT 3260.500 504.410 3261.400 504.710 ;
    END
  END w0_wd_in[174]
  PIN w0_wd_in[175]
    DIRECTION INPUT ;
    USE SIGNAL ;
    SHAPE ABUTMENT ;
    PORT
      LAYER met3 ;
      RECT 3260.500 515.290 3261.400 515.590 ;
    END
  END w0_wd_in[175]
  PIN w0_wd_in[176]
    DIRECTION INPUT ;
    USE SIGNAL ;
    SHAPE ABUTMENT ;
    PORT
      LAYER met3 ;
      RECT 3260.500 526.170 3261.400 526.470 ;
    END
  END w0_wd_in[176]
  PIN w0_wd_in[177]
    DIRECTION INPUT ;
    USE SIGNAL ;
    SHAPE ABUTMENT ;
    PORT
      LAYER met3 ;
      RECT 3260.500 537.050 3261.400 537.350 ;
    END
  END w0_wd_in[177]
  PIN w0_wd_in[178]
    DIRECTION INPUT ;
    USE SIGNAL ;
    SHAPE ABUTMENT ;
    PORT
      LAYER met3 ;
      RECT 3260.500 547.930 3261.400 548.230 ;
    END
  END w0_wd_in[178]
  PIN w0_wd_in[179]
    DIRECTION INPUT ;
    USE SIGNAL ;
    SHAPE ABUTMENT ;
    PORT
      LAYER met3 ;
      RECT 3260.500 558.810 3261.400 559.110 ;
    END
  END w0_wd_in[179]
  PIN w0_wd_in[180]
    DIRECTION INPUT ;
    USE SIGNAL ;
    SHAPE ABUTMENT ;
    PORT
      LAYER met3 ;
      RECT 3260.500 569.690 3261.400 569.990 ;
    END
  END w0_wd_in[180]
  PIN w0_wd_in[181]
    DIRECTION INPUT ;
    USE SIGNAL ;
    SHAPE ABUTMENT ;
    PORT
      LAYER met3 ;
      RECT 3260.500 580.570 3261.400 580.870 ;
    END
  END w0_wd_in[181]
  PIN w0_wd_in[182]
    DIRECTION INPUT ;
    USE SIGNAL ;
    SHAPE ABUTMENT ;
    PORT
      LAYER met3 ;
      RECT 3260.500 591.450 3261.400 591.750 ;
    END
  END w0_wd_in[182]
  PIN w0_wd_in[183]
    DIRECTION INPUT ;
    USE SIGNAL ;
    SHAPE ABUTMENT ;
    PORT
      LAYER met3 ;
      RECT 3260.500 602.330 3261.400 602.630 ;
    END
  END w0_wd_in[183]
  PIN w0_wd_in[184]
    DIRECTION INPUT ;
    USE SIGNAL ;
    SHAPE ABUTMENT ;
    PORT
      LAYER met3 ;
      RECT 3260.500 613.210 3261.400 613.510 ;
    END
  END w0_wd_in[184]
  PIN w0_wd_in[185]
    DIRECTION INPUT ;
    USE SIGNAL ;
    SHAPE ABUTMENT ;
    PORT
      LAYER met3 ;
      RECT 3260.500 624.090 3261.400 624.390 ;
    END
  END w0_wd_in[185]
  PIN w0_wd_in[186]
    DIRECTION INPUT ;
    USE SIGNAL ;
    SHAPE ABUTMENT ;
    PORT
      LAYER met3 ;
      RECT 3260.500 634.970 3261.400 635.270 ;
    END
  END w0_wd_in[186]
  PIN w0_wd_in[187]
    DIRECTION INPUT ;
    USE SIGNAL ;
    SHAPE ABUTMENT ;
    PORT
      LAYER met3 ;
      RECT 3260.500 645.850 3261.400 646.150 ;
    END
  END w0_wd_in[187]
  PIN w0_wd_in[188]
    DIRECTION INPUT ;
    USE SIGNAL ;
    SHAPE ABUTMENT ;
    PORT
      LAYER met3 ;
      RECT 3260.500 656.730 3261.400 657.030 ;
    END
  END w0_wd_in[188]
  PIN w0_wd_in[189]
    DIRECTION INPUT ;
    USE SIGNAL ;
    SHAPE ABUTMENT ;
    PORT
      LAYER met3 ;
      RECT 3260.500 667.610 3261.400 667.910 ;
    END
  END w0_wd_in[189]
  PIN w0_wd_in[190]
    DIRECTION INPUT ;
    USE SIGNAL ;
    SHAPE ABUTMENT ;
    PORT
      LAYER met3 ;
      RECT 3260.500 678.490 3261.400 678.790 ;
    END
  END w0_wd_in[190]
  PIN w0_wd_in[191]
    DIRECTION INPUT ;
    USE SIGNAL ;
    SHAPE ABUTMENT ;
    PORT
      LAYER met3 ;
      RECT 3260.500 689.370 3261.400 689.670 ;
    END
  END w0_wd_in[191]
  PIN w0_wd_in[192]
    DIRECTION INPUT ;
    USE SIGNAL ;
    SHAPE ABUTMENT ;
    PORT
      LAYER met3 ;
      RECT 3260.500 700.250 3261.400 700.550 ;
    END
  END w0_wd_in[192]
  PIN w0_wd_in[193]
    DIRECTION INPUT ;
    USE SIGNAL ;
    SHAPE ABUTMENT ;
    PORT
      LAYER met3 ;
      RECT 3260.500 711.130 3261.400 711.430 ;
    END
  END w0_wd_in[193]
  PIN w0_wd_in[194]
    DIRECTION INPUT ;
    USE SIGNAL ;
    SHAPE ABUTMENT ;
    PORT
      LAYER met3 ;
      RECT 3260.500 722.010 3261.400 722.310 ;
    END
  END w0_wd_in[194]
  PIN w0_wd_in[195]
    DIRECTION INPUT ;
    USE SIGNAL ;
    SHAPE ABUTMENT ;
    PORT
      LAYER met3 ;
      RECT 3260.500 732.890 3261.400 733.190 ;
    END
  END w0_wd_in[195]
  PIN w0_wd_in[196]
    DIRECTION INPUT ;
    USE SIGNAL ;
    SHAPE ABUTMENT ;
    PORT
      LAYER met3 ;
      RECT 3260.500 743.770 3261.400 744.070 ;
    END
  END w0_wd_in[196]
  PIN w0_wd_in[197]
    DIRECTION INPUT ;
    USE SIGNAL ;
    SHAPE ABUTMENT ;
    PORT
      LAYER met3 ;
      RECT 3260.500 754.650 3261.400 754.950 ;
    END
  END w0_wd_in[197]
  PIN w0_wd_in[198]
    DIRECTION INPUT ;
    USE SIGNAL ;
    SHAPE ABUTMENT ;
    PORT
      LAYER met3 ;
      RECT 3260.500 765.530 3261.400 765.830 ;
    END
  END w0_wd_in[198]
  PIN w0_wd_in[199]
    DIRECTION INPUT ;
    USE SIGNAL ;
    SHAPE ABUTMENT ;
    PORT
      LAYER met3 ;
      RECT 3260.500 776.410 3261.400 776.710 ;
    END
  END w0_wd_in[199]
  PIN w0_wd_in[200]
    DIRECTION INPUT ;
    USE SIGNAL ;
    SHAPE ABUTMENT ;
    PORT
      LAYER met3 ;
      RECT 3260.500 787.290 3261.400 787.590 ;
    END
  END w0_wd_in[200]
  PIN w0_wd_in[201]
    DIRECTION INPUT ;
    USE SIGNAL ;
    SHAPE ABUTMENT ;
    PORT
      LAYER met3 ;
      RECT 3260.500 798.170 3261.400 798.470 ;
    END
  END w0_wd_in[201]
  PIN w0_wd_in[202]
    DIRECTION INPUT ;
    USE SIGNAL ;
    SHAPE ABUTMENT ;
    PORT
      LAYER met3 ;
      RECT 3260.500 809.050 3261.400 809.350 ;
    END
  END w0_wd_in[202]
  PIN w0_wd_in[203]
    DIRECTION INPUT ;
    USE SIGNAL ;
    SHAPE ABUTMENT ;
    PORT
      LAYER met3 ;
      RECT 3260.500 819.930 3261.400 820.230 ;
    END
  END w0_wd_in[203]
  PIN w0_wd_in[204]
    DIRECTION INPUT ;
    USE SIGNAL ;
    SHAPE ABUTMENT ;
    PORT
      LAYER met3 ;
      RECT 3260.500 830.810 3261.400 831.110 ;
    END
  END w0_wd_in[204]
  PIN w0_wd_in[205]
    DIRECTION INPUT ;
    USE SIGNAL ;
    SHAPE ABUTMENT ;
    PORT
      LAYER met3 ;
      RECT 3260.500 841.690 3261.400 841.990 ;
    END
  END w0_wd_in[205]
  PIN w0_wd_in[206]
    DIRECTION INPUT ;
    USE SIGNAL ;
    SHAPE ABUTMENT ;
    PORT
      LAYER met3 ;
      RECT 3260.500 852.570 3261.400 852.870 ;
    END
  END w0_wd_in[206]
  PIN w0_wd_in[207]
    DIRECTION INPUT ;
    USE SIGNAL ;
    SHAPE ABUTMENT ;
    PORT
      LAYER met3 ;
      RECT 3260.500 863.450 3261.400 863.750 ;
    END
  END w0_wd_in[207]
  PIN w0_wd_in[208]
    DIRECTION INPUT ;
    USE SIGNAL ;
    SHAPE ABUTMENT ;
    PORT
      LAYER met3 ;
      RECT 3260.500 874.330 3261.400 874.630 ;
    END
  END w0_wd_in[208]
  PIN w0_wd_in[209]
    DIRECTION INPUT ;
    USE SIGNAL ;
    SHAPE ABUTMENT ;
    PORT
      LAYER met3 ;
      RECT 3260.500 885.210 3261.400 885.510 ;
    END
  END w0_wd_in[209]
  PIN w0_wd_in[210]
    DIRECTION INPUT ;
    USE SIGNAL ;
    SHAPE ABUTMENT ;
    PORT
      LAYER met3 ;
      RECT 3260.500 896.090 3261.400 896.390 ;
    END
  END w0_wd_in[210]
  PIN w0_wd_in[211]
    DIRECTION INPUT ;
    USE SIGNAL ;
    SHAPE ABUTMENT ;
    PORT
      LAYER met3 ;
      RECT 3260.500 906.970 3261.400 907.270 ;
    END
  END w0_wd_in[211]
  PIN w0_wd_in[212]
    DIRECTION INPUT ;
    USE SIGNAL ;
    SHAPE ABUTMENT ;
    PORT
      LAYER met3 ;
      RECT 3260.500 917.850 3261.400 918.150 ;
    END
  END w0_wd_in[212]
  PIN w0_wd_in[213]
    DIRECTION INPUT ;
    USE SIGNAL ;
    SHAPE ABUTMENT ;
    PORT
      LAYER met3 ;
      RECT 3260.500 928.730 3261.400 929.030 ;
    END
  END w0_wd_in[213]
  PIN w0_wd_in[214]
    DIRECTION INPUT ;
    USE SIGNAL ;
    SHAPE ABUTMENT ;
    PORT
      LAYER met3 ;
      RECT 3260.500 939.610 3261.400 939.910 ;
    END
  END w0_wd_in[214]
  PIN w0_wd_in[215]
    DIRECTION INPUT ;
    USE SIGNAL ;
    SHAPE ABUTMENT ;
    PORT
      LAYER met3 ;
      RECT 3260.500 950.490 3261.400 950.790 ;
    END
  END w0_wd_in[215]
  PIN w0_wd_in[216]
    DIRECTION INPUT ;
    USE SIGNAL ;
    SHAPE ABUTMENT ;
    PORT
      LAYER met3 ;
      RECT 3260.500 961.370 3261.400 961.670 ;
    END
  END w0_wd_in[216]
  PIN w0_wd_in[217]
    DIRECTION INPUT ;
    USE SIGNAL ;
    SHAPE ABUTMENT ;
    PORT
      LAYER met3 ;
      RECT 3260.500 972.250 3261.400 972.550 ;
    END
  END w0_wd_in[217]
  PIN w0_wd_in[218]
    DIRECTION INPUT ;
    USE SIGNAL ;
    SHAPE ABUTMENT ;
    PORT
      LAYER met3 ;
      RECT 3260.500 983.130 3261.400 983.430 ;
    END
  END w0_wd_in[218]
  PIN w0_wd_in[219]
    DIRECTION INPUT ;
    USE SIGNAL ;
    SHAPE ABUTMENT ;
    PORT
      LAYER met3 ;
      RECT 3260.500 994.010 3261.400 994.310 ;
    END
  END w0_wd_in[219]
  PIN w0_wd_in[220]
    DIRECTION INPUT ;
    USE SIGNAL ;
    SHAPE ABUTMENT ;
    PORT
      LAYER met3 ;
      RECT 3260.500 1004.890 3261.400 1005.190 ;
    END
  END w0_wd_in[220]
  PIN w0_wd_in[221]
    DIRECTION INPUT ;
    USE SIGNAL ;
    SHAPE ABUTMENT ;
    PORT
      LAYER met3 ;
      RECT 3260.500 1015.770 3261.400 1016.070 ;
    END
  END w0_wd_in[221]
  PIN w0_wd_in[222]
    DIRECTION INPUT ;
    USE SIGNAL ;
    SHAPE ABUTMENT ;
    PORT
      LAYER met3 ;
      RECT 3260.500 1026.650 3261.400 1026.950 ;
    END
  END w0_wd_in[222]
  PIN w0_wd_in[223]
    DIRECTION INPUT ;
    USE SIGNAL ;
    SHAPE ABUTMENT ;
    PORT
      LAYER met3 ;
      RECT 3260.500 1037.530 3261.400 1037.830 ;
    END
  END w0_wd_in[223]
  PIN w0_wd_in[224]
    DIRECTION INPUT ;
    USE SIGNAL ;
    SHAPE ABUTMENT ;
    PORT
      LAYER met3 ;
      RECT 3260.500 1048.410 3261.400 1048.710 ;
    END
  END w0_wd_in[224]
  PIN w0_wd_in[225]
    DIRECTION INPUT ;
    USE SIGNAL ;
    SHAPE ABUTMENT ;
    PORT
      LAYER met3 ;
      RECT 3260.500 1059.290 3261.400 1059.590 ;
    END
  END w0_wd_in[225]
  PIN w0_wd_in[226]
    DIRECTION INPUT ;
    USE SIGNAL ;
    SHAPE ABUTMENT ;
    PORT
      LAYER met3 ;
      RECT 3260.500 1070.170 3261.400 1070.470 ;
    END
  END w0_wd_in[226]
  PIN w0_wd_in[227]
    DIRECTION INPUT ;
    USE SIGNAL ;
    SHAPE ABUTMENT ;
    PORT
      LAYER met3 ;
      RECT 3260.500 1081.050 3261.400 1081.350 ;
    END
  END w0_wd_in[227]
  PIN w0_wd_in[228]
    DIRECTION INPUT ;
    USE SIGNAL ;
    SHAPE ABUTMENT ;
    PORT
      LAYER met3 ;
      RECT 3260.500 1091.930 3261.400 1092.230 ;
    END
  END w0_wd_in[228]
  PIN w0_wd_in[229]
    DIRECTION INPUT ;
    USE SIGNAL ;
    SHAPE ABUTMENT ;
    PORT
      LAYER met3 ;
      RECT 3260.500 1102.810 3261.400 1103.110 ;
    END
  END w0_wd_in[229]
  PIN w0_wd_in[230]
    DIRECTION INPUT ;
    USE SIGNAL ;
    SHAPE ABUTMENT ;
    PORT
      LAYER met3 ;
      RECT 3260.500 1113.690 3261.400 1113.990 ;
    END
  END w0_wd_in[230]
  PIN w0_wd_in[231]
    DIRECTION INPUT ;
    USE SIGNAL ;
    SHAPE ABUTMENT ;
    PORT
      LAYER met3 ;
      RECT 3260.500 1124.570 3261.400 1124.870 ;
    END
  END w0_wd_in[231]
  PIN w0_wd_in[232]
    DIRECTION INPUT ;
    USE SIGNAL ;
    SHAPE ABUTMENT ;
    PORT
      LAYER met3 ;
      RECT 3260.500 1135.450 3261.400 1135.750 ;
    END
  END w0_wd_in[232]
  PIN w0_wd_in[233]
    DIRECTION INPUT ;
    USE SIGNAL ;
    SHAPE ABUTMENT ;
    PORT
      LAYER met3 ;
      RECT 3260.500 1146.330 3261.400 1146.630 ;
    END
  END w0_wd_in[233]
  PIN w0_wd_in[234]
    DIRECTION INPUT ;
    USE SIGNAL ;
    SHAPE ABUTMENT ;
    PORT
      LAYER met3 ;
      RECT 3260.500 1157.210 3261.400 1157.510 ;
    END
  END w0_wd_in[234]
  PIN w0_wd_in[235]
    DIRECTION INPUT ;
    USE SIGNAL ;
    SHAPE ABUTMENT ;
    PORT
      LAYER met3 ;
      RECT 3260.500 1168.090 3261.400 1168.390 ;
    END
  END w0_wd_in[235]
  PIN w0_wd_in[236]
    DIRECTION INPUT ;
    USE SIGNAL ;
    SHAPE ABUTMENT ;
    PORT
      LAYER met3 ;
      RECT 3260.500 1178.970 3261.400 1179.270 ;
    END
  END w0_wd_in[236]
  PIN w0_wd_in[237]
    DIRECTION INPUT ;
    USE SIGNAL ;
    SHAPE ABUTMENT ;
    PORT
      LAYER met3 ;
      RECT 3260.500 1189.850 3261.400 1190.150 ;
    END
  END w0_wd_in[237]
  PIN w0_wd_in[238]
    DIRECTION INPUT ;
    USE SIGNAL ;
    SHAPE ABUTMENT ;
    PORT
      LAYER met3 ;
      RECT 3260.500 1200.730 3261.400 1201.030 ;
    END
  END w0_wd_in[238]
  PIN w0_wd_in[239]
    DIRECTION INPUT ;
    USE SIGNAL ;
    SHAPE ABUTMENT ;
    PORT
      LAYER met3 ;
      RECT 3260.500 1211.610 3261.400 1211.910 ;
    END
  END w0_wd_in[239]
  PIN w0_wd_in[240]
    DIRECTION INPUT ;
    USE SIGNAL ;
    SHAPE ABUTMENT ;
    PORT
      LAYER met3 ;
      RECT 3260.500 1222.490 3261.400 1222.790 ;
    END
  END w0_wd_in[240]
  PIN w0_wd_in[241]
    DIRECTION INPUT ;
    USE SIGNAL ;
    SHAPE ABUTMENT ;
    PORT
      LAYER met3 ;
      RECT 3260.500 1233.370 3261.400 1233.670 ;
    END
  END w0_wd_in[241]
  PIN w0_wd_in[242]
    DIRECTION INPUT ;
    USE SIGNAL ;
    SHAPE ABUTMENT ;
    PORT
      LAYER met3 ;
      RECT 3260.500 1244.250 3261.400 1244.550 ;
    END
  END w0_wd_in[242]
  PIN w0_wd_in[243]
    DIRECTION INPUT ;
    USE SIGNAL ;
    SHAPE ABUTMENT ;
    PORT
      LAYER met3 ;
      RECT 3260.500 1255.130 3261.400 1255.430 ;
    END
  END w0_wd_in[243]
  PIN w0_wd_in[244]
    DIRECTION INPUT ;
    USE SIGNAL ;
    SHAPE ABUTMENT ;
    PORT
      LAYER met3 ;
      RECT 3260.500 1266.010 3261.400 1266.310 ;
    END
  END w0_wd_in[244]
  PIN w0_wd_in[245]
    DIRECTION INPUT ;
    USE SIGNAL ;
    SHAPE ABUTMENT ;
    PORT
      LAYER met3 ;
      RECT 3260.500 1276.890 3261.400 1277.190 ;
    END
  END w0_wd_in[245]
  PIN w0_wd_in[246]
    DIRECTION INPUT ;
    USE SIGNAL ;
    SHAPE ABUTMENT ;
    PORT
      LAYER met3 ;
      RECT 3260.500 1287.770 3261.400 1288.070 ;
    END
  END w0_wd_in[246]
  PIN w0_wd_in[247]
    DIRECTION INPUT ;
    USE SIGNAL ;
    SHAPE ABUTMENT ;
    PORT
      LAYER met3 ;
      RECT 3260.500 1298.650 3261.400 1298.950 ;
    END
  END w0_wd_in[247]
  PIN w0_wd_in[248]
    DIRECTION INPUT ;
    USE SIGNAL ;
    SHAPE ABUTMENT ;
    PORT
      LAYER met3 ;
      RECT 3260.500 1309.530 3261.400 1309.830 ;
    END
  END w0_wd_in[248]
  PIN w0_wd_in[249]
    DIRECTION INPUT ;
    USE SIGNAL ;
    SHAPE ABUTMENT ;
    PORT
      LAYER met3 ;
      RECT 3260.500 1320.410 3261.400 1320.710 ;
    END
  END w0_wd_in[249]
  PIN w0_wd_in[250]
    DIRECTION INPUT ;
    USE SIGNAL ;
    SHAPE ABUTMENT ;
    PORT
      LAYER met3 ;
      RECT 3260.500 1331.290 3261.400 1331.590 ;
    END
  END w0_wd_in[250]
  PIN w0_wd_in[251]
    DIRECTION INPUT ;
    USE SIGNAL ;
    SHAPE ABUTMENT ;
    PORT
      LAYER met3 ;
      RECT 3260.500 1342.170 3261.400 1342.470 ;
    END
  END w0_wd_in[251]
  PIN w0_wd_in[252]
    DIRECTION INPUT ;
    USE SIGNAL ;
    SHAPE ABUTMENT ;
    PORT
      LAYER met3 ;
      RECT 3260.500 1353.050 3261.400 1353.350 ;
    END
  END w0_wd_in[252]
  PIN w0_wd_in[253]
    DIRECTION INPUT ;
    USE SIGNAL ;
    SHAPE ABUTMENT ;
    PORT
      LAYER met3 ;
      RECT 3260.500 1363.930 3261.400 1364.230 ;
    END
  END w0_wd_in[253]
  PIN w0_wd_in[254]
    DIRECTION INPUT ;
    USE SIGNAL ;
    SHAPE ABUTMENT ;
    PORT
      LAYER met3 ;
      RECT 3260.500 1374.810 3261.400 1375.110 ;
    END
  END w0_wd_in[254]
  PIN w0_wd_in[255]
    DIRECTION INPUT ;
    USE SIGNAL ;
    SHAPE ABUTMENT ;
    PORT
      LAYER met3 ;
      RECT 3260.500 1385.690 3261.400 1385.990 ;
    END
  END w0_wd_in[255]
  PIN w0_wd_in[256]
    DIRECTION OUTPUT ;
    USE SIGNAL ;
    SHAPE ABUTMENT ;
    PORT
      LAYER met2 ;
      RECT 2.690 0.000 2.830 0.420 ;
    END
  END w0_wd_in[256]
  PIN w0_wd_in[257]
    DIRECTION OUTPUT ;
    USE SIGNAL ;
    SHAPE ABUTMENT ;
    PORT
      LAYER met2 ;
      RECT 8.670 0.000 8.810 0.420 ;
    END
  END w0_wd_in[257]
  PIN w0_wd_in[258]
    DIRECTION OUTPUT ;
    USE SIGNAL ;
    SHAPE ABUTMENT ;
    PORT
      LAYER met2 ;
      RECT 14.650 0.000 14.790 0.420 ;
    END
  END w0_wd_in[258]
  PIN w0_wd_in[259]
    DIRECTION OUTPUT ;
    USE SIGNAL ;
    SHAPE ABUTMENT ;
    PORT
      LAYER met2 ;
      RECT 20.630 0.000 20.770 0.420 ;
    END
  END w0_wd_in[259]
  PIN w0_wd_in[260]
    DIRECTION OUTPUT ;
    USE SIGNAL ;
    SHAPE ABUTMENT ;
    PORT
      LAYER met2 ;
      RECT 26.610 0.000 26.750 0.420 ;
    END
  END w0_wd_in[260]
  PIN w0_wd_in[261]
    DIRECTION OUTPUT ;
    USE SIGNAL ;
    SHAPE ABUTMENT ;
    PORT
      LAYER met2 ;
      RECT 32.590 0.000 32.730 0.420 ;
    END
  END w0_wd_in[261]
  PIN w0_wd_in[262]
    DIRECTION OUTPUT ;
    USE SIGNAL ;
    SHAPE ABUTMENT ;
    PORT
      LAYER met2 ;
      RECT 38.570 0.000 38.710 0.420 ;
    END
  END w0_wd_in[262]
  PIN w0_wd_in[263]
    DIRECTION OUTPUT ;
    USE SIGNAL ;
    SHAPE ABUTMENT ;
    PORT
      LAYER met2 ;
      RECT 44.550 0.000 44.690 0.420 ;
    END
  END w0_wd_in[263]
  PIN w0_wd_in[264]
    DIRECTION OUTPUT ;
    USE SIGNAL ;
    SHAPE ABUTMENT ;
    PORT
      LAYER met2 ;
      RECT 50.530 0.000 50.670 0.420 ;
    END
  END w0_wd_in[264]
  PIN w0_wd_in[265]
    DIRECTION OUTPUT ;
    USE SIGNAL ;
    SHAPE ABUTMENT ;
    PORT
      LAYER met2 ;
      RECT 56.510 0.000 56.650 0.420 ;
    END
  END w0_wd_in[265]
  PIN w0_wd_in[266]
    DIRECTION OUTPUT ;
    USE SIGNAL ;
    SHAPE ABUTMENT ;
    PORT
      LAYER met2 ;
      RECT 62.490 0.000 62.630 0.420 ;
    END
  END w0_wd_in[266]
  PIN w0_wd_in[267]
    DIRECTION OUTPUT ;
    USE SIGNAL ;
    SHAPE ABUTMENT ;
    PORT
      LAYER met2 ;
      RECT 68.470 0.000 68.610 0.420 ;
    END
  END w0_wd_in[267]
  PIN w0_wd_in[268]
    DIRECTION OUTPUT ;
    USE SIGNAL ;
    SHAPE ABUTMENT ;
    PORT
      LAYER met2 ;
      RECT 74.450 0.000 74.590 0.420 ;
    END
  END w0_wd_in[268]
  PIN w0_wd_in[269]
    DIRECTION OUTPUT ;
    USE SIGNAL ;
    SHAPE ABUTMENT ;
    PORT
      LAYER met2 ;
      RECT 80.430 0.000 80.570 0.420 ;
    END
  END w0_wd_in[269]
  PIN w0_wd_in[270]
    DIRECTION OUTPUT ;
    USE SIGNAL ;
    SHAPE ABUTMENT ;
    PORT
      LAYER met2 ;
      RECT 86.410 0.000 86.550 0.420 ;
    END
  END w0_wd_in[270]
  PIN w0_wd_in[271]
    DIRECTION OUTPUT ;
    USE SIGNAL ;
    SHAPE ABUTMENT ;
    PORT
      LAYER met2 ;
      RECT 92.390 0.000 92.530 0.420 ;
    END
  END w0_wd_in[271]
  PIN w0_wd_in[272]
    DIRECTION OUTPUT ;
    USE SIGNAL ;
    SHAPE ABUTMENT ;
    PORT
      LAYER met2 ;
      RECT 98.370 0.000 98.510 0.420 ;
    END
  END w0_wd_in[272]
  PIN w0_wd_in[273]
    DIRECTION OUTPUT ;
    USE SIGNAL ;
    SHAPE ABUTMENT ;
    PORT
      LAYER met2 ;
      RECT 104.350 0.000 104.490 0.420 ;
    END
  END w0_wd_in[273]
  PIN w0_wd_in[274]
    DIRECTION OUTPUT ;
    USE SIGNAL ;
    SHAPE ABUTMENT ;
    PORT
      LAYER met2 ;
      RECT 110.330 0.000 110.470 0.420 ;
    END
  END w0_wd_in[274]
  PIN w0_wd_in[275]
    DIRECTION OUTPUT ;
    USE SIGNAL ;
    SHAPE ABUTMENT ;
    PORT
      LAYER met2 ;
      RECT 116.310 0.000 116.450 0.420 ;
    END
  END w0_wd_in[275]
  PIN w0_wd_in[276]
    DIRECTION OUTPUT ;
    USE SIGNAL ;
    SHAPE ABUTMENT ;
    PORT
      LAYER met2 ;
      RECT 122.290 0.000 122.430 0.420 ;
    END
  END w0_wd_in[276]
  PIN w0_wd_in[277]
    DIRECTION OUTPUT ;
    USE SIGNAL ;
    SHAPE ABUTMENT ;
    PORT
      LAYER met2 ;
      RECT 128.270 0.000 128.410 0.420 ;
    END
  END w0_wd_in[277]
  PIN w0_wd_in[278]
    DIRECTION OUTPUT ;
    USE SIGNAL ;
    SHAPE ABUTMENT ;
    PORT
      LAYER met2 ;
      RECT 134.250 0.000 134.390 0.420 ;
    END
  END w0_wd_in[278]
  PIN w0_wd_in[279]
    DIRECTION OUTPUT ;
    USE SIGNAL ;
    SHAPE ABUTMENT ;
    PORT
      LAYER met2 ;
      RECT 140.230 0.000 140.370 0.420 ;
    END
  END w0_wd_in[279]
  PIN w0_wd_in[280]
    DIRECTION OUTPUT ;
    USE SIGNAL ;
    SHAPE ABUTMENT ;
    PORT
      LAYER met2 ;
      RECT 146.210 0.000 146.350 0.420 ;
    END
  END w0_wd_in[280]
  PIN w0_wd_in[281]
    DIRECTION OUTPUT ;
    USE SIGNAL ;
    SHAPE ABUTMENT ;
    PORT
      LAYER met2 ;
      RECT 152.190 0.000 152.330 0.420 ;
    END
  END w0_wd_in[281]
  PIN w0_wd_in[282]
    DIRECTION OUTPUT ;
    USE SIGNAL ;
    SHAPE ABUTMENT ;
    PORT
      LAYER met2 ;
      RECT 158.170 0.000 158.310 0.420 ;
    END
  END w0_wd_in[282]
  PIN w0_wd_in[283]
    DIRECTION OUTPUT ;
    USE SIGNAL ;
    SHAPE ABUTMENT ;
    PORT
      LAYER met2 ;
      RECT 164.150 0.000 164.290 0.420 ;
    END
  END w0_wd_in[283]
  PIN w0_wd_in[284]
    DIRECTION OUTPUT ;
    USE SIGNAL ;
    SHAPE ABUTMENT ;
    PORT
      LAYER met2 ;
      RECT 170.130 0.000 170.270 0.420 ;
    END
  END w0_wd_in[284]
  PIN w0_wd_in[285]
    DIRECTION OUTPUT ;
    USE SIGNAL ;
    SHAPE ABUTMENT ;
    PORT
      LAYER met2 ;
      RECT 176.110 0.000 176.250 0.420 ;
    END
  END w0_wd_in[285]
  PIN w0_wd_in[286]
    DIRECTION OUTPUT ;
    USE SIGNAL ;
    SHAPE ABUTMENT ;
    PORT
      LAYER met2 ;
      RECT 182.090 0.000 182.230 0.420 ;
    END
  END w0_wd_in[286]
  PIN w0_wd_in[287]
    DIRECTION OUTPUT ;
    USE SIGNAL ;
    SHAPE ABUTMENT ;
    PORT
      LAYER met2 ;
      RECT 188.070 0.000 188.210 0.420 ;
    END
  END w0_wd_in[287]
  PIN w0_wd_in[288]
    DIRECTION OUTPUT ;
    USE SIGNAL ;
    SHAPE ABUTMENT ;
    PORT
      LAYER met2 ;
      RECT 194.050 0.000 194.190 0.420 ;
    END
  END w0_wd_in[288]
  PIN w0_wd_in[289]
    DIRECTION OUTPUT ;
    USE SIGNAL ;
    SHAPE ABUTMENT ;
    PORT
      LAYER met2 ;
      RECT 200.030 0.000 200.170 0.420 ;
    END
  END w0_wd_in[289]
  PIN w0_wd_in[290]
    DIRECTION OUTPUT ;
    USE SIGNAL ;
    SHAPE ABUTMENT ;
    PORT
      LAYER met2 ;
      RECT 206.010 0.000 206.150 0.420 ;
    END
  END w0_wd_in[290]
  PIN w0_wd_in[291]
    DIRECTION OUTPUT ;
    USE SIGNAL ;
    SHAPE ABUTMENT ;
    PORT
      LAYER met2 ;
      RECT 211.990 0.000 212.130 0.420 ;
    END
  END w0_wd_in[291]
  PIN w0_wd_in[292]
    DIRECTION OUTPUT ;
    USE SIGNAL ;
    SHAPE ABUTMENT ;
    PORT
      LAYER met2 ;
      RECT 217.970 0.000 218.110 0.420 ;
    END
  END w0_wd_in[292]
  PIN w0_wd_in[293]
    DIRECTION OUTPUT ;
    USE SIGNAL ;
    SHAPE ABUTMENT ;
    PORT
      LAYER met2 ;
      RECT 223.950 0.000 224.090 0.420 ;
    END
  END w0_wd_in[293]
  PIN w0_wd_in[294]
    DIRECTION OUTPUT ;
    USE SIGNAL ;
    SHAPE ABUTMENT ;
    PORT
      LAYER met2 ;
      RECT 229.930 0.000 230.070 0.420 ;
    END
  END w0_wd_in[294]
  PIN w0_wd_in[295]
    DIRECTION OUTPUT ;
    USE SIGNAL ;
    SHAPE ABUTMENT ;
    PORT
      LAYER met2 ;
      RECT 235.910 0.000 236.050 0.420 ;
    END
  END w0_wd_in[295]
  PIN w0_wd_in[296]
    DIRECTION OUTPUT ;
    USE SIGNAL ;
    SHAPE ABUTMENT ;
    PORT
      LAYER met2 ;
      RECT 241.890 0.000 242.030 0.420 ;
    END
  END w0_wd_in[296]
  PIN w0_wd_in[297]
    DIRECTION OUTPUT ;
    USE SIGNAL ;
    SHAPE ABUTMENT ;
    PORT
      LAYER met2 ;
      RECT 247.870 0.000 248.010 0.420 ;
    END
  END w0_wd_in[297]
  PIN w0_wd_in[298]
    DIRECTION OUTPUT ;
    USE SIGNAL ;
    SHAPE ABUTMENT ;
    PORT
      LAYER met2 ;
      RECT 253.850 0.000 253.990 0.420 ;
    END
  END w0_wd_in[298]
  PIN w0_wd_in[299]
    DIRECTION OUTPUT ;
    USE SIGNAL ;
    SHAPE ABUTMENT ;
    PORT
      LAYER met2 ;
      RECT 259.830 0.000 259.970 0.420 ;
    END
  END w0_wd_in[299]
  PIN w0_wd_in[300]
    DIRECTION OUTPUT ;
    USE SIGNAL ;
    SHAPE ABUTMENT ;
    PORT
      LAYER met2 ;
      RECT 265.810 0.000 265.950 0.420 ;
    END
  END w0_wd_in[300]
  PIN w0_wd_in[301]
    DIRECTION OUTPUT ;
    USE SIGNAL ;
    SHAPE ABUTMENT ;
    PORT
      LAYER met2 ;
      RECT 271.790 0.000 271.930 0.420 ;
    END
  END w0_wd_in[301]
  PIN w0_wd_in[302]
    DIRECTION OUTPUT ;
    USE SIGNAL ;
    SHAPE ABUTMENT ;
    PORT
      LAYER met2 ;
      RECT 277.770 0.000 277.910 0.420 ;
    END
  END w0_wd_in[302]
  PIN w0_wd_in[303]
    DIRECTION OUTPUT ;
    USE SIGNAL ;
    SHAPE ABUTMENT ;
    PORT
      LAYER met2 ;
      RECT 283.750 0.000 283.890 0.420 ;
    END
  END w0_wd_in[303]
  PIN w0_wd_in[304]
    DIRECTION OUTPUT ;
    USE SIGNAL ;
    SHAPE ABUTMENT ;
    PORT
      LAYER met2 ;
      RECT 289.730 0.000 289.870 0.420 ;
    END
  END w0_wd_in[304]
  PIN w0_wd_in[305]
    DIRECTION OUTPUT ;
    USE SIGNAL ;
    SHAPE ABUTMENT ;
    PORT
      LAYER met2 ;
      RECT 295.710 0.000 295.850 0.420 ;
    END
  END w0_wd_in[305]
  PIN w0_wd_in[306]
    DIRECTION OUTPUT ;
    USE SIGNAL ;
    SHAPE ABUTMENT ;
    PORT
      LAYER met2 ;
      RECT 301.690 0.000 301.830 0.420 ;
    END
  END w0_wd_in[306]
  PIN w0_wd_in[307]
    DIRECTION OUTPUT ;
    USE SIGNAL ;
    SHAPE ABUTMENT ;
    PORT
      LAYER met2 ;
      RECT 307.670 0.000 307.810 0.420 ;
    END
  END w0_wd_in[307]
  PIN w0_wd_in[308]
    DIRECTION OUTPUT ;
    USE SIGNAL ;
    SHAPE ABUTMENT ;
    PORT
      LAYER met2 ;
      RECT 313.650 0.000 313.790 0.420 ;
    END
  END w0_wd_in[308]
  PIN w0_wd_in[309]
    DIRECTION OUTPUT ;
    USE SIGNAL ;
    SHAPE ABUTMENT ;
    PORT
      LAYER met2 ;
      RECT 319.630 0.000 319.770 0.420 ;
    END
  END w0_wd_in[309]
  PIN w0_wd_in[310]
    DIRECTION OUTPUT ;
    USE SIGNAL ;
    SHAPE ABUTMENT ;
    PORT
      LAYER met2 ;
      RECT 325.610 0.000 325.750 0.420 ;
    END
  END w0_wd_in[310]
  PIN w0_wd_in[311]
    DIRECTION OUTPUT ;
    USE SIGNAL ;
    SHAPE ABUTMENT ;
    PORT
      LAYER met2 ;
      RECT 331.590 0.000 331.730 0.420 ;
    END
  END w0_wd_in[311]
  PIN w0_wd_in[312]
    DIRECTION OUTPUT ;
    USE SIGNAL ;
    SHAPE ABUTMENT ;
    PORT
      LAYER met2 ;
      RECT 337.570 0.000 337.710 0.420 ;
    END
  END w0_wd_in[312]
  PIN w0_wd_in[313]
    DIRECTION OUTPUT ;
    USE SIGNAL ;
    SHAPE ABUTMENT ;
    PORT
      LAYER met2 ;
      RECT 343.550 0.000 343.690 0.420 ;
    END
  END w0_wd_in[313]
  PIN w0_wd_in[314]
    DIRECTION OUTPUT ;
    USE SIGNAL ;
    SHAPE ABUTMENT ;
    PORT
      LAYER met2 ;
      RECT 349.530 0.000 349.670 0.420 ;
    END
  END w0_wd_in[314]
  PIN w0_wd_in[315]
    DIRECTION OUTPUT ;
    USE SIGNAL ;
    SHAPE ABUTMENT ;
    PORT
      LAYER met2 ;
      RECT 355.510 0.000 355.650 0.420 ;
    END
  END w0_wd_in[315]
  PIN w0_wd_in[316]
    DIRECTION OUTPUT ;
    USE SIGNAL ;
    SHAPE ABUTMENT ;
    PORT
      LAYER met2 ;
      RECT 361.490 0.000 361.630 0.420 ;
    END
  END w0_wd_in[316]
  PIN w0_wd_in[317]
    DIRECTION OUTPUT ;
    USE SIGNAL ;
    SHAPE ABUTMENT ;
    PORT
      LAYER met2 ;
      RECT 367.470 0.000 367.610 0.420 ;
    END
  END w0_wd_in[317]
  PIN w0_wd_in[318]
    DIRECTION OUTPUT ;
    USE SIGNAL ;
    SHAPE ABUTMENT ;
    PORT
      LAYER met2 ;
      RECT 373.450 0.000 373.590 0.420 ;
    END
  END w0_wd_in[318]
  PIN w0_wd_in[319]
    DIRECTION OUTPUT ;
    USE SIGNAL ;
    SHAPE ABUTMENT ;
    PORT
      LAYER met2 ;
      RECT 379.430 0.000 379.570 0.420 ;
    END
  END w0_wd_in[319]
  PIN w0_wd_in[320]
    DIRECTION OUTPUT ;
    USE SIGNAL ;
    SHAPE ABUTMENT ;
    PORT
      LAYER met2 ;
      RECT 385.410 0.000 385.550 0.420 ;
    END
  END w0_wd_in[320]
  PIN w0_wd_in[321]
    DIRECTION OUTPUT ;
    USE SIGNAL ;
    SHAPE ABUTMENT ;
    PORT
      LAYER met2 ;
      RECT 391.390 0.000 391.530 0.420 ;
    END
  END w0_wd_in[321]
  PIN w0_wd_in[322]
    DIRECTION OUTPUT ;
    USE SIGNAL ;
    SHAPE ABUTMENT ;
    PORT
      LAYER met2 ;
      RECT 397.370 0.000 397.510 0.420 ;
    END
  END w0_wd_in[322]
  PIN w0_wd_in[323]
    DIRECTION OUTPUT ;
    USE SIGNAL ;
    SHAPE ABUTMENT ;
    PORT
      LAYER met2 ;
      RECT 403.350 0.000 403.490 0.420 ;
    END
  END w0_wd_in[323]
  PIN w0_wd_in[324]
    DIRECTION OUTPUT ;
    USE SIGNAL ;
    SHAPE ABUTMENT ;
    PORT
      LAYER met2 ;
      RECT 409.330 0.000 409.470 0.420 ;
    END
  END w0_wd_in[324]
  PIN w0_wd_in[325]
    DIRECTION OUTPUT ;
    USE SIGNAL ;
    SHAPE ABUTMENT ;
    PORT
      LAYER met2 ;
      RECT 415.310 0.000 415.450 0.420 ;
    END
  END w0_wd_in[325]
  PIN w0_wd_in[326]
    DIRECTION OUTPUT ;
    USE SIGNAL ;
    SHAPE ABUTMENT ;
    PORT
      LAYER met2 ;
      RECT 421.290 0.000 421.430 0.420 ;
    END
  END w0_wd_in[326]
  PIN w0_wd_in[327]
    DIRECTION OUTPUT ;
    USE SIGNAL ;
    SHAPE ABUTMENT ;
    PORT
      LAYER met2 ;
      RECT 427.270 0.000 427.410 0.420 ;
    END
  END w0_wd_in[327]
  PIN w0_wd_in[328]
    DIRECTION OUTPUT ;
    USE SIGNAL ;
    SHAPE ABUTMENT ;
    PORT
      LAYER met2 ;
      RECT 433.250 0.000 433.390 0.420 ;
    END
  END w0_wd_in[328]
  PIN w0_wd_in[329]
    DIRECTION OUTPUT ;
    USE SIGNAL ;
    SHAPE ABUTMENT ;
    PORT
      LAYER met2 ;
      RECT 439.230 0.000 439.370 0.420 ;
    END
  END w0_wd_in[329]
  PIN w0_wd_in[330]
    DIRECTION OUTPUT ;
    USE SIGNAL ;
    SHAPE ABUTMENT ;
    PORT
      LAYER met2 ;
      RECT 445.210 0.000 445.350 0.420 ;
    END
  END w0_wd_in[330]
  PIN w0_wd_in[331]
    DIRECTION OUTPUT ;
    USE SIGNAL ;
    SHAPE ABUTMENT ;
    PORT
      LAYER met2 ;
      RECT 451.190 0.000 451.330 0.420 ;
    END
  END w0_wd_in[331]
  PIN w0_wd_in[332]
    DIRECTION OUTPUT ;
    USE SIGNAL ;
    SHAPE ABUTMENT ;
    PORT
      LAYER met2 ;
      RECT 457.170 0.000 457.310 0.420 ;
    END
  END w0_wd_in[332]
  PIN w0_wd_in[333]
    DIRECTION OUTPUT ;
    USE SIGNAL ;
    SHAPE ABUTMENT ;
    PORT
      LAYER met2 ;
      RECT 463.150 0.000 463.290 0.420 ;
    END
  END w0_wd_in[333]
  PIN w0_wd_in[334]
    DIRECTION OUTPUT ;
    USE SIGNAL ;
    SHAPE ABUTMENT ;
    PORT
      LAYER met2 ;
      RECT 469.130 0.000 469.270 0.420 ;
    END
  END w0_wd_in[334]
  PIN w0_wd_in[335]
    DIRECTION OUTPUT ;
    USE SIGNAL ;
    SHAPE ABUTMENT ;
    PORT
      LAYER met2 ;
      RECT 475.110 0.000 475.250 0.420 ;
    END
  END w0_wd_in[335]
  PIN w0_wd_in[336]
    DIRECTION OUTPUT ;
    USE SIGNAL ;
    SHAPE ABUTMENT ;
    PORT
      LAYER met2 ;
      RECT 481.090 0.000 481.230 0.420 ;
    END
  END w0_wd_in[336]
  PIN w0_wd_in[337]
    DIRECTION OUTPUT ;
    USE SIGNAL ;
    SHAPE ABUTMENT ;
    PORT
      LAYER met2 ;
      RECT 487.070 0.000 487.210 0.420 ;
    END
  END w0_wd_in[337]
  PIN w0_wd_in[338]
    DIRECTION OUTPUT ;
    USE SIGNAL ;
    SHAPE ABUTMENT ;
    PORT
      LAYER met2 ;
      RECT 493.050 0.000 493.190 0.420 ;
    END
  END w0_wd_in[338]
  PIN w0_wd_in[339]
    DIRECTION OUTPUT ;
    USE SIGNAL ;
    SHAPE ABUTMENT ;
    PORT
      LAYER met2 ;
      RECT 499.030 0.000 499.170 0.420 ;
    END
  END w0_wd_in[339]
  PIN w0_wd_in[340]
    DIRECTION OUTPUT ;
    USE SIGNAL ;
    SHAPE ABUTMENT ;
    PORT
      LAYER met2 ;
      RECT 505.010 0.000 505.150 0.420 ;
    END
  END w0_wd_in[340]
  PIN w0_wd_in[341]
    DIRECTION OUTPUT ;
    USE SIGNAL ;
    SHAPE ABUTMENT ;
    PORT
      LAYER met2 ;
      RECT 510.990 0.000 511.130 0.420 ;
    END
  END w0_wd_in[341]
  PIN w0_wd_in[342]
    DIRECTION OUTPUT ;
    USE SIGNAL ;
    SHAPE ABUTMENT ;
    PORT
      LAYER met2 ;
      RECT 516.970 0.000 517.110 0.420 ;
    END
  END w0_wd_in[342]
  PIN w0_wd_in[343]
    DIRECTION OUTPUT ;
    USE SIGNAL ;
    SHAPE ABUTMENT ;
    PORT
      LAYER met2 ;
      RECT 522.950 0.000 523.090 0.420 ;
    END
  END w0_wd_in[343]
  PIN w0_wd_in[344]
    DIRECTION OUTPUT ;
    USE SIGNAL ;
    SHAPE ABUTMENT ;
    PORT
      LAYER met2 ;
      RECT 528.930 0.000 529.070 0.420 ;
    END
  END w0_wd_in[344]
  PIN w0_wd_in[345]
    DIRECTION OUTPUT ;
    USE SIGNAL ;
    SHAPE ABUTMENT ;
    PORT
      LAYER met2 ;
      RECT 534.910 0.000 535.050 0.420 ;
    END
  END w0_wd_in[345]
  PIN w0_wd_in[346]
    DIRECTION OUTPUT ;
    USE SIGNAL ;
    SHAPE ABUTMENT ;
    PORT
      LAYER met2 ;
      RECT 540.890 0.000 541.030 0.420 ;
    END
  END w0_wd_in[346]
  PIN w0_wd_in[347]
    DIRECTION OUTPUT ;
    USE SIGNAL ;
    SHAPE ABUTMENT ;
    PORT
      LAYER met2 ;
      RECT 546.870 0.000 547.010 0.420 ;
    END
  END w0_wd_in[347]
  PIN w0_wd_in[348]
    DIRECTION OUTPUT ;
    USE SIGNAL ;
    SHAPE ABUTMENT ;
    PORT
      LAYER met2 ;
      RECT 552.850 0.000 552.990 0.420 ;
    END
  END w0_wd_in[348]
  PIN w0_wd_in[349]
    DIRECTION OUTPUT ;
    USE SIGNAL ;
    SHAPE ABUTMENT ;
    PORT
      LAYER met2 ;
      RECT 558.830 0.000 558.970 0.420 ;
    END
  END w0_wd_in[349]
  PIN w0_wd_in[350]
    DIRECTION OUTPUT ;
    USE SIGNAL ;
    SHAPE ABUTMENT ;
    PORT
      LAYER met2 ;
      RECT 564.810 0.000 564.950 0.420 ;
    END
  END w0_wd_in[350]
  PIN w0_wd_in[351]
    DIRECTION OUTPUT ;
    USE SIGNAL ;
    SHAPE ABUTMENT ;
    PORT
      LAYER met2 ;
      RECT 570.790 0.000 570.930 0.420 ;
    END
  END w0_wd_in[351]
  PIN w0_wd_in[352]
    DIRECTION OUTPUT ;
    USE SIGNAL ;
    SHAPE ABUTMENT ;
    PORT
      LAYER met2 ;
      RECT 576.770 0.000 576.910 0.420 ;
    END
  END w0_wd_in[352]
  PIN w0_wd_in[353]
    DIRECTION OUTPUT ;
    USE SIGNAL ;
    SHAPE ABUTMENT ;
    PORT
      LAYER met2 ;
      RECT 582.750 0.000 582.890 0.420 ;
    END
  END w0_wd_in[353]
  PIN w0_wd_in[354]
    DIRECTION OUTPUT ;
    USE SIGNAL ;
    SHAPE ABUTMENT ;
    PORT
      LAYER met2 ;
      RECT 588.730 0.000 588.870 0.420 ;
    END
  END w0_wd_in[354]
  PIN w0_wd_in[355]
    DIRECTION OUTPUT ;
    USE SIGNAL ;
    SHAPE ABUTMENT ;
    PORT
      LAYER met2 ;
      RECT 594.710 0.000 594.850 0.420 ;
    END
  END w0_wd_in[355]
  PIN w0_wd_in[356]
    DIRECTION OUTPUT ;
    USE SIGNAL ;
    SHAPE ABUTMENT ;
    PORT
      LAYER met2 ;
      RECT 600.690 0.000 600.830 0.420 ;
    END
  END w0_wd_in[356]
  PIN w0_wd_in[357]
    DIRECTION OUTPUT ;
    USE SIGNAL ;
    SHAPE ABUTMENT ;
    PORT
      LAYER met2 ;
      RECT 606.670 0.000 606.810 0.420 ;
    END
  END w0_wd_in[357]
  PIN w0_wd_in[358]
    DIRECTION OUTPUT ;
    USE SIGNAL ;
    SHAPE ABUTMENT ;
    PORT
      LAYER met2 ;
      RECT 612.650 0.000 612.790 0.420 ;
    END
  END w0_wd_in[358]
  PIN w0_wd_in[359]
    DIRECTION OUTPUT ;
    USE SIGNAL ;
    SHAPE ABUTMENT ;
    PORT
      LAYER met2 ;
      RECT 618.630 0.000 618.770 0.420 ;
    END
  END w0_wd_in[359]
  PIN w0_wd_in[360]
    DIRECTION OUTPUT ;
    USE SIGNAL ;
    SHAPE ABUTMENT ;
    PORT
      LAYER met2 ;
      RECT 624.610 0.000 624.750 0.420 ;
    END
  END w0_wd_in[360]
  PIN w0_wd_in[361]
    DIRECTION OUTPUT ;
    USE SIGNAL ;
    SHAPE ABUTMENT ;
    PORT
      LAYER met2 ;
      RECT 630.590 0.000 630.730 0.420 ;
    END
  END w0_wd_in[361]
  PIN w0_wd_in[362]
    DIRECTION OUTPUT ;
    USE SIGNAL ;
    SHAPE ABUTMENT ;
    PORT
      LAYER met2 ;
      RECT 636.570 0.000 636.710 0.420 ;
    END
  END w0_wd_in[362]
  PIN w0_wd_in[363]
    DIRECTION OUTPUT ;
    USE SIGNAL ;
    SHAPE ABUTMENT ;
    PORT
      LAYER met2 ;
      RECT 642.550 0.000 642.690 0.420 ;
    END
  END w0_wd_in[363]
  PIN w0_wd_in[364]
    DIRECTION OUTPUT ;
    USE SIGNAL ;
    SHAPE ABUTMENT ;
    PORT
      LAYER met2 ;
      RECT 648.530 0.000 648.670 0.420 ;
    END
  END w0_wd_in[364]
  PIN w0_wd_in[365]
    DIRECTION OUTPUT ;
    USE SIGNAL ;
    SHAPE ABUTMENT ;
    PORT
      LAYER met2 ;
      RECT 654.510 0.000 654.650 0.420 ;
    END
  END w0_wd_in[365]
  PIN w0_wd_in[366]
    DIRECTION OUTPUT ;
    USE SIGNAL ;
    SHAPE ABUTMENT ;
    PORT
      LAYER met2 ;
      RECT 660.490 0.000 660.630 0.420 ;
    END
  END w0_wd_in[366]
  PIN w0_wd_in[367]
    DIRECTION OUTPUT ;
    USE SIGNAL ;
    SHAPE ABUTMENT ;
    PORT
      LAYER met2 ;
      RECT 666.470 0.000 666.610 0.420 ;
    END
  END w0_wd_in[367]
  PIN w0_wd_in[368]
    DIRECTION OUTPUT ;
    USE SIGNAL ;
    SHAPE ABUTMENT ;
    PORT
      LAYER met2 ;
      RECT 672.450 0.000 672.590 0.420 ;
    END
  END w0_wd_in[368]
  PIN w0_wd_in[369]
    DIRECTION OUTPUT ;
    USE SIGNAL ;
    SHAPE ABUTMENT ;
    PORT
      LAYER met2 ;
      RECT 678.430 0.000 678.570 0.420 ;
    END
  END w0_wd_in[369]
  PIN w0_wd_in[370]
    DIRECTION OUTPUT ;
    USE SIGNAL ;
    SHAPE ABUTMENT ;
    PORT
      LAYER met2 ;
      RECT 684.410 0.000 684.550 0.420 ;
    END
  END w0_wd_in[370]
  PIN w0_wd_in[371]
    DIRECTION OUTPUT ;
    USE SIGNAL ;
    SHAPE ABUTMENT ;
    PORT
      LAYER met2 ;
      RECT 690.390 0.000 690.530 0.420 ;
    END
  END w0_wd_in[371]
  PIN w0_wd_in[372]
    DIRECTION OUTPUT ;
    USE SIGNAL ;
    SHAPE ABUTMENT ;
    PORT
      LAYER met2 ;
      RECT 696.370 0.000 696.510 0.420 ;
    END
  END w0_wd_in[372]
  PIN w0_wd_in[373]
    DIRECTION OUTPUT ;
    USE SIGNAL ;
    SHAPE ABUTMENT ;
    PORT
      LAYER met2 ;
      RECT 702.350 0.000 702.490 0.420 ;
    END
  END w0_wd_in[373]
  PIN w0_wd_in[374]
    DIRECTION OUTPUT ;
    USE SIGNAL ;
    SHAPE ABUTMENT ;
    PORT
      LAYER met2 ;
      RECT 708.330 0.000 708.470 0.420 ;
    END
  END w0_wd_in[374]
  PIN w0_wd_in[375]
    DIRECTION OUTPUT ;
    USE SIGNAL ;
    SHAPE ABUTMENT ;
    PORT
      LAYER met2 ;
      RECT 714.310 0.000 714.450 0.420 ;
    END
  END w0_wd_in[375]
  PIN w0_wd_in[376]
    DIRECTION OUTPUT ;
    USE SIGNAL ;
    SHAPE ABUTMENT ;
    PORT
      LAYER met2 ;
      RECT 720.290 0.000 720.430 0.420 ;
    END
  END w0_wd_in[376]
  PIN w0_wd_in[377]
    DIRECTION OUTPUT ;
    USE SIGNAL ;
    SHAPE ABUTMENT ;
    PORT
      LAYER met2 ;
      RECT 726.270 0.000 726.410 0.420 ;
    END
  END w0_wd_in[377]
  PIN w0_wd_in[378]
    DIRECTION OUTPUT ;
    USE SIGNAL ;
    SHAPE ABUTMENT ;
    PORT
      LAYER met2 ;
      RECT 732.250 0.000 732.390 0.420 ;
    END
  END w0_wd_in[378]
  PIN w0_wd_in[379]
    DIRECTION OUTPUT ;
    USE SIGNAL ;
    SHAPE ABUTMENT ;
    PORT
      LAYER met2 ;
      RECT 738.230 0.000 738.370 0.420 ;
    END
  END w0_wd_in[379]
  PIN w0_wd_in[380]
    DIRECTION OUTPUT ;
    USE SIGNAL ;
    SHAPE ABUTMENT ;
    PORT
      LAYER met2 ;
      RECT 744.210 0.000 744.350 0.420 ;
    END
  END w0_wd_in[380]
  PIN w0_wd_in[381]
    DIRECTION OUTPUT ;
    USE SIGNAL ;
    SHAPE ABUTMENT ;
    PORT
      LAYER met2 ;
      RECT 750.190 0.000 750.330 0.420 ;
    END
  END w0_wd_in[381]
  PIN w0_wd_in[382]
    DIRECTION OUTPUT ;
    USE SIGNAL ;
    SHAPE ABUTMENT ;
    PORT
      LAYER met2 ;
      RECT 756.170 0.000 756.310 0.420 ;
    END
  END w0_wd_in[382]
  PIN w0_wd_in[383]
    DIRECTION OUTPUT ;
    USE SIGNAL ;
    SHAPE ABUTMENT ;
    PORT
      LAYER met2 ;
      RECT 762.150 0.000 762.290 0.420 ;
    END
  END w0_wd_in[383]
  PIN w0_wd_in[384]
    DIRECTION OUTPUT ;
    USE SIGNAL ;
    SHAPE ABUTMENT ;
    PORT
      LAYER met2 ;
      RECT 768.130 0.000 768.270 0.420 ;
    END
  END w0_wd_in[384]
  PIN w0_wd_in[385]
    DIRECTION OUTPUT ;
    USE SIGNAL ;
    SHAPE ABUTMENT ;
    PORT
      LAYER met2 ;
      RECT 774.110 0.000 774.250 0.420 ;
    END
  END w0_wd_in[385]
  PIN w0_wd_in[386]
    DIRECTION OUTPUT ;
    USE SIGNAL ;
    SHAPE ABUTMENT ;
    PORT
      LAYER met2 ;
      RECT 780.090 0.000 780.230 0.420 ;
    END
  END w0_wd_in[386]
  PIN w0_wd_in[387]
    DIRECTION OUTPUT ;
    USE SIGNAL ;
    SHAPE ABUTMENT ;
    PORT
      LAYER met2 ;
      RECT 786.070 0.000 786.210 0.420 ;
    END
  END w0_wd_in[387]
  PIN w0_wd_in[388]
    DIRECTION OUTPUT ;
    USE SIGNAL ;
    SHAPE ABUTMENT ;
    PORT
      LAYER met2 ;
      RECT 792.050 0.000 792.190 0.420 ;
    END
  END w0_wd_in[388]
  PIN w0_wd_in[389]
    DIRECTION OUTPUT ;
    USE SIGNAL ;
    SHAPE ABUTMENT ;
    PORT
      LAYER met2 ;
      RECT 798.030 0.000 798.170 0.420 ;
    END
  END w0_wd_in[389]
  PIN w0_wd_in[390]
    DIRECTION OUTPUT ;
    USE SIGNAL ;
    SHAPE ABUTMENT ;
    PORT
      LAYER met2 ;
      RECT 804.010 0.000 804.150 0.420 ;
    END
  END w0_wd_in[390]
  PIN w0_wd_in[391]
    DIRECTION OUTPUT ;
    USE SIGNAL ;
    SHAPE ABUTMENT ;
    PORT
      LAYER met2 ;
      RECT 809.990 0.000 810.130 0.420 ;
    END
  END w0_wd_in[391]
  PIN w0_wd_in[392]
    DIRECTION OUTPUT ;
    USE SIGNAL ;
    SHAPE ABUTMENT ;
    PORT
      LAYER met2 ;
      RECT 815.970 0.000 816.110 0.420 ;
    END
  END w0_wd_in[392]
  PIN w0_wd_in[393]
    DIRECTION OUTPUT ;
    USE SIGNAL ;
    SHAPE ABUTMENT ;
    PORT
      LAYER met2 ;
      RECT 821.950 0.000 822.090 0.420 ;
    END
  END w0_wd_in[393]
  PIN w0_wd_in[394]
    DIRECTION OUTPUT ;
    USE SIGNAL ;
    SHAPE ABUTMENT ;
    PORT
      LAYER met2 ;
      RECT 827.930 0.000 828.070 0.420 ;
    END
  END w0_wd_in[394]
  PIN w0_wd_in[395]
    DIRECTION OUTPUT ;
    USE SIGNAL ;
    SHAPE ABUTMENT ;
    PORT
      LAYER met2 ;
      RECT 833.910 0.000 834.050 0.420 ;
    END
  END w0_wd_in[395]
  PIN w0_wd_in[396]
    DIRECTION OUTPUT ;
    USE SIGNAL ;
    SHAPE ABUTMENT ;
    PORT
      LAYER met2 ;
      RECT 839.890 0.000 840.030 0.420 ;
    END
  END w0_wd_in[396]
  PIN w0_wd_in[397]
    DIRECTION OUTPUT ;
    USE SIGNAL ;
    SHAPE ABUTMENT ;
    PORT
      LAYER met2 ;
      RECT 845.870 0.000 846.010 0.420 ;
    END
  END w0_wd_in[397]
  PIN w0_wd_in[398]
    DIRECTION OUTPUT ;
    USE SIGNAL ;
    SHAPE ABUTMENT ;
    PORT
      LAYER met2 ;
      RECT 851.850 0.000 851.990 0.420 ;
    END
  END w0_wd_in[398]
  PIN w0_wd_in[399]
    DIRECTION OUTPUT ;
    USE SIGNAL ;
    SHAPE ABUTMENT ;
    PORT
      LAYER met2 ;
      RECT 857.830 0.000 857.970 0.420 ;
    END
  END w0_wd_in[399]
  PIN w0_wd_in[400]
    DIRECTION OUTPUT ;
    USE SIGNAL ;
    SHAPE ABUTMENT ;
    PORT
      LAYER met2 ;
      RECT 863.810 0.000 863.950 0.420 ;
    END
  END w0_wd_in[400]
  PIN w0_wd_in[401]
    DIRECTION OUTPUT ;
    USE SIGNAL ;
    SHAPE ABUTMENT ;
    PORT
      LAYER met2 ;
      RECT 869.790 0.000 869.930 0.420 ;
    END
  END w0_wd_in[401]
  PIN w0_wd_in[402]
    DIRECTION OUTPUT ;
    USE SIGNAL ;
    SHAPE ABUTMENT ;
    PORT
      LAYER met2 ;
      RECT 875.770 0.000 875.910 0.420 ;
    END
  END w0_wd_in[402]
  PIN w0_wd_in[403]
    DIRECTION OUTPUT ;
    USE SIGNAL ;
    SHAPE ABUTMENT ;
    PORT
      LAYER met2 ;
      RECT 881.750 0.000 881.890 0.420 ;
    END
  END w0_wd_in[403]
  PIN w0_wd_in[404]
    DIRECTION OUTPUT ;
    USE SIGNAL ;
    SHAPE ABUTMENT ;
    PORT
      LAYER met2 ;
      RECT 887.730 0.000 887.870 0.420 ;
    END
  END w0_wd_in[404]
  PIN w0_wd_in[405]
    DIRECTION OUTPUT ;
    USE SIGNAL ;
    SHAPE ABUTMENT ;
    PORT
      LAYER met2 ;
      RECT 893.710 0.000 893.850 0.420 ;
    END
  END w0_wd_in[405]
  PIN w0_wd_in[406]
    DIRECTION OUTPUT ;
    USE SIGNAL ;
    SHAPE ABUTMENT ;
    PORT
      LAYER met2 ;
      RECT 899.690 0.000 899.830 0.420 ;
    END
  END w0_wd_in[406]
  PIN w0_wd_in[407]
    DIRECTION OUTPUT ;
    USE SIGNAL ;
    SHAPE ABUTMENT ;
    PORT
      LAYER met2 ;
      RECT 905.670 0.000 905.810 0.420 ;
    END
  END w0_wd_in[407]
  PIN w0_wd_in[408]
    DIRECTION OUTPUT ;
    USE SIGNAL ;
    SHAPE ABUTMENT ;
    PORT
      LAYER met2 ;
      RECT 911.650 0.000 911.790 0.420 ;
    END
  END w0_wd_in[408]
  PIN w0_wd_in[409]
    DIRECTION OUTPUT ;
    USE SIGNAL ;
    SHAPE ABUTMENT ;
    PORT
      LAYER met2 ;
      RECT 917.630 0.000 917.770 0.420 ;
    END
  END w0_wd_in[409]
  PIN w0_wd_in[410]
    DIRECTION OUTPUT ;
    USE SIGNAL ;
    SHAPE ABUTMENT ;
    PORT
      LAYER met2 ;
      RECT 923.610 0.000 923.750 0.420 ;
    END
  END w0_wd_in[410]
  PIN w0_wd_in[411]
    DIRECTION OUTPUT ;
    USE SIGNAL ;
    SHAPE ABUTMENT ;
    PORT
      LAYER met2 ;
      RECT 929.590 0.000 929.730 0.420 ;
    END
  END w0_wd_in[411]
  PIN w0_wd_in[412]
    DIRECTION OUTPUT ;
    USE SIGNAL ;
    SHAPE ABUTMENT ;
    PORT
      LAYER met2 ;
      RECT 935.570 0.000 935.710 0.420 ;
    END
  END w0_wd_in[412]
  PIN w0_wd_in[413]
    DIRECTION OUTPUT ;
    USE SIGNAL ;
    SHAPE ABUTMENT ;
    PORT
      LAYER met2 ;
      RECT 941.550 0.000 941.690 0.420 ;
    END
  END w0_wd_in[413]
  PIN w0_wd_in[414]
    DIRECTION OUTPUT ;
    USE SIGNAL ;
    SHAPE ABUTMENT ;
    PORT
      LAYER met2 ;
      RECT 947.530 0.000 947.670 0.420 ;
    END
  END w0_wd_in[414]
  PIN w0_wd_in[415]
    DIRECTION OUTPUT ;
    USE SIGNAL ;
    SHAPE ABUTMENT ;
    PORT
      LAYER met2 ;
      RECT 953.510 0.000 953.650 0.420 ;
    END
  END w0_wd_in[415]
  PIN w0_wd_in[416]
    DIRECTION OUTPUT ;
    USE SIGNAL ;
    SHAPE ABUTMENT ;
    PORT
      LAYER met2 ;
      RECT 959.490 0.000 959.630 0.420 ;
    END
  END w0_wd_in[416]
  PIN w0_wd_in[417]
    DIRECTION OUTPUT ;
    USE SIGNAL ;
    SHAPE ABUTMENT ;
    PORT
      LAYER met2 ;
      RECT 965.470 0.000 965.610 0.420 ;
    END
  END w0_wd_in[417]
  PIN w0_wd_in[418]
    DIRECTION OUTPUT ;
    USE SIGNAL ;
    SHAPE ABUTMENT ;
    PORT
      LAYER met2 ;
      RECT 971.450 0.000 971.590 0.420 ;
    END
  END w0_wd_in[418]
  PIN w0_wd_in[419]
    DIRECTION OUTPUT ;
    USE SIGNAL ;
    SHAPE ABUTMENT ;
    PORT
      LAYER met2 ;
      RECT 977.430 0.000 977.570 0.420 ;
    END
  END w0_wd_in[419]
  PIN w0_wd_in[420]
    DIRECTION OUTPUT ;
    USE SIGNAL ;
    SHAPE ABUTMENT ;
    PORT
      LAYER met2 ;
      RECT 983.410 0.000 983.550 0.420 ;
    END
  END w0_wd_in[420]
  PIN w0_wd_in[421]
    DIRECTION OUTPUT ;
    USE SIGNAL ;
    SHAPE ABUTMENT ;
    PORT
      LAYER met2 ;
      RECT 989.390 0.000 989.530 0.420 ;
    END
  END w0_wd_in[421]
  PIN w0_wd_in[422]
    DIRECTION OUTPUT ;
    USE SIGNAL ;
    SHAPE ABUTMENT ;
    PORT
      LAYER met2 ;
      RECT 995.370 0.000 995.510 0.420 ;
    END
  END w0_wd_in[422]
  PIN w0_wd_in[423]
    DIRECTION OUTPUT ;
    USE SIGNAL ;
    SHAPE ABUTMENT ;
    PORT
      LAYER met2 ;
      RECT 1001.350 0.000 1001.490 0.420 ;
    END
  END w0_wd_in[423]
  PIN w0_wd_in[424]
    DIRECTION OUTPUT ;
    USE SIGNAL ;
    SHAPE ABUTMENT ;
    PORT
      LAYER met2 ;
      RECT 1007.330 0.000 1007.470 0.420 ;
    END
  END w0_wd_in[424]
  PIN w0_wd_in[425]
    DIRECTION OUTPUT ;
    USE SIGNAL ;
    SHAPE ABUTMENT ;
    PORT
      LAYER met2 ;
      RECT 1013.310 0.000 1013.450 0.420 ;
    END
  END w0_wd_in[425]
  PIN w0_wd_in[426]
    DIRECTION OUTPUT ;
    USE SIGNAL ;
    SHAPE ABUTMENT ;
    PORT
      LAYER met2 ;
      RECT 1019.290 0.000 1019.430 0.420 ;
    END
  END w0_wd_in[426]
  PIN w0_wd_in[427]
    DIRECTION OUTPUT ;
    USE SIGNAL ;
    SHAPE ABUTMENT ;
    PORT
      LAYER met2 ;
      RECT 1025.270 0.000 1025.410 0.420 ;
    END
  END w0_wd_in[427]
  PIN w0_wd_in[428]
    DIRECTION OUTPUT ;
    USE SIGNAL ;
    SHAPE ABUTMENT ;
    PORT
      LAYER met2 ;
      RECT 1031.250 0.000 1031.390 0.420 ;
    END
  END w0_wd_in[428]
  PIN w0_wd_in[429]
    DIRECTION OUTPUT ;
    USE SIGNAL ;
    SHAPE ABUTMENT ;
    PORT
      LAYER met2 ;
      RECT 1037.230 0.000 1037.370 0.420 ;
    END
  END w0_wd_in[429]
  PIN w0_wd_in[430]
    DIRECTION OUTPUT ;
    USE SIGNAL ;
    SHAPE ABUTMENT ;
    PORT
      LAYER met2 ;
      RECT 1043.210 0.000 1043.350 0.420 ;
    END
  END w0_wd_in[430]
  PIN w0_wd_in[431]
    DIRECTION OUTPUT ;
    USE SIGNAL ;
    SHAPE ABUTMENT ;
    PORT
      LAYER met2 ;
      RECT 1049.190 0.000 1049.330 0.420 ;
    END
  END w0_wd_in[431]
  PIN w0_wd_in[432]
    DIRECTION OUTPUT ;
    USE SIGNAL ;
    SHAPE ABUTMENT ;
    PORT
      LAYER met2 ;
      RECT 1055.170 0.000 1055.310 0.420 ;
    END
  END w0_wd_in[432]
  PIN w0_wd_in[433]
    DIRECTION OUTPUT ;
    USE SIGNAL ;
    SHAPE ABUTMENT ;
    PORT
      LAYER met2 ;
      RECT 1061.150 0.000 1061.290 0.420 ;
    END
  END w0_wd_in[433]
  PIN w0_wd_in[434]
    DIRECTION OUTPUT ;
    USE SIGNAL ;
    SHAPE ABUTMENT ;
    PORT
      LAYER met2 ;
      RECT 1067.130 0.000 1067.270 0.420 ;
    END
  END w0_wd_in[434]
  PIN w0_wd_in[435]
    DIRECTION OUTPUT ;
    USE SIGNAL ;
    SHAPE ABUTMENT ;
    PORT
      LAYER met2 ;
      RECT 1073.110 0.000 1073.250 0.420 ;
    END
  END w0_wd_in[435]
  PIN w0_wd_in[436]
    DIRECTION OUTPUT ;
    USE SIGNAL ;
    SHAPE ABUTMENT ;
    PORT
      LAYER met2 ;
      RECT 1079.090 0.000 1079.230 0.420 ;
    END
  END w0_wd_in[436]
  PIN w0_wd_in[437]
    DIRECTION OUTPUT ;
    USE SIGNAL ;
    SHAPE ABUTMENT ;
    PORT
      LAYER met2 ;
      RECT 1085.070 0.000 1085.210 0.420 ;
    END
  END w0_wd_in[437]
  PIN w0_wd_in[438]
    DIRECTION OUTPUT ;
    USE SIGNAL ;
    SHAPE ABUTMENT ;
    PORT
      LAYER met2 ;
      RECT 1091.050 0.000 1091.190 0.420 ;
    END
  END w0_wd_in[438]
  PIN w0_wd_in[439]
    DIRECTION OUTPUT ;
    USE SIGNAL ;
    SHAPE ABUTMENT ;
    PORT
      LAYER met2 ;
      RECT 1097.030 0.000 1097.170 0.420 ;
    END
  END w0_wd_in[439]
  PIN w0_wd_in[440]
    DIRECTION OUTPUT ;
    USE SIGNAL ;
    SHAPE ABUTMENT ;
    PORT
      LAYER met2 ;
      RECT 1103.010 0.000 1103.150 0.420 ;
    END
  END w0_wd_in[440]
  PIN w0_wd_in[441]
    DIRECTION OUTPUT ;
    USE SIGNAL ;
    SHAPE ABUTMENT ;
    PORT
      LAYER met2 ;
      RECT 1108.990 0.000 1109.130 0.420 ;
    END
  END w0_wd_in[441]
  PIN w0_wd_in[442]
    DIRECTION OUTPUT ;
    USE SIGNAL ;
    SHAPE ABUTMENT ;
    PORT
      LAYER met2 ;
      RECT 1114.970 0.000 1115.110 0.420 ;
    END
  END w0_wd_in[442]
  PIN w0_wd_in[443]
    DIRECTION OUTPUT ;
    USE SIGNAL ;
    SHAPE ABUTMENT ;
    PORT
      LAYER met2 ;
      RECT 1120.950 0.000 1121.090 0.420 ;
    END
  END w0_wd_in[443]
  PIN w0_wd_in[444]
    DIRECTION OUTPUT ;
    USE SIGNAL ;
    SHAPE ABUTMENT ;
    PORT
      LAYER met2 ;
      RECT 1126.930 0.000 1127.070 0.420 ;
    END
  END w0_wd_in[444]
  PIN w0_wd_in[445]
    DIRECTION OUTPUT ;
    USE SIGNAL ;
    SHAPE ABUTMENT ;
    PORT
      LAYER met2 ;
      RECT 1132.910 0.000 1133.050 0.420 ;
    END
  END w0_wd_in[445]
  PIN w0_wd_in[446]
    DIRECTION OUTPUT ;
    USE SIGNAL ;
    SHAPE ABUTMENT ;
    PORT
      LAYER met2 ;
      RECT 1138.890 0.000 1139.030 0.420 ;
    END
  END w0_wd_in[446]
  PIN w0_wd_in[447]
    DIRECTION OUTPUT ;
    USE SIGNAL ;
    SHAPE ABUTMENT ;
    PORT
      LAYER met2 ;
      RECT 1144.870 0.000 1145.010 0.420 ;
    END
  END w0_wd_in[447]
  PIN w0_wd_in[448]
    DIRECTION OUTPUT ;
    USE SIGNAL ;
    SHAPE ABUTMENT ;
    PORT
      LAYER met2 ;
      RECT 1150.850 0.000 1150.990 0.420 ;
    END
  END w0_wd_in[448]
  PIN w0_wd_in[449]
    DIRECTION OUTPUT ;
    USE SIGNAL ;
    SHAPE ABUTMENT ;
    PORT
      LAYER met2 ;
      RECT 1156.830 0.000 1156.970 0.420 ;
    END
  END w0_wd_in[449]
  PIN w0_wd_in[450]
    DIRECTION OUTPUT ;
    USE SIGNAL ;
    SHAPE ABUTMENT ;
    PORT
      LAYER met2 ;
      RECT 1162.810 0.000 1162.950 0.420 ;
    END
  END w0_wd_in[450]
  PIN w0_wd_in[451]
    DIRECTION OUTPUT ;
    USE SIGNAL ;
    SHAPE ABUTMENT ;
    PORT
      LAYER met2 ;
      RECT 1168.790 0.000 1168.930 0.420 ;
    END
  END w0_wd_in[451]
  PIN w0_wd_in[452]
    DIRECTION OUTPUT ;
    USE SIGNAL ;
    SHAPE ABUTMENT ;
    PORT
      LAYER met2 ;
      RECT 1174.770 0.000 1174.910 0.420 ;
    END
  END w0_wd_in[452]
  PIN w0_wd_in[453]
    DIRECTION OUTPUT ;
    USE SIGNAL ;
    SHAPE ABUTMENT ;
    PORT
      LAYER met2 ;
      RECT 1180.750 0.000 1180.890 0.420 ;
    END
  END w0_wd_in[453]
  PIN w0_wd_in[454]
    DIRECTION OUTPUT ;
    USE SIGNAL ;
    SHAPE ABUTMENT ;
    PORT
      LAYER met2 ;
      RECT 1186.730 0.000 1186.870 0.420 ;
    END
  END w0_wd_in[454]
  PIN w0_wd_in[455]
    DIRECTION OUTPUT ;
    USE SIGNAL ;
    SHAPE ABUTMENT ;
    PORT
      LAYER met2 ;
      RECT 1192.710 0.000 1192.850 0.420 ;
    END
  END w0_wd_in[455]
  PIN w0_wd_in[456]
    DIRECTION OUTPUT ;
    USE SIGNAL ;
    SHAPE ABUTMENT ;
    PORT
      LAYER met2 ;
      RECT 1198.690 0.000 1198.830 0.420 ;
    END
  END w0_wd_in[456]
  PIN w0_wd_in[457]
    DIRECTION OUTPUT ;
    USE SIGNAL ;
    SHAPE ABUTMENT ;
    PORT
      LAYER met2 ;
      RECT 1204.670 0.000 1204.810 0.420 ;
    END
  END w0_wd_in[457]
  PIN w0_wd_in[458]
    DIRECTION OUTPUT ;
    USE SIGNAL ;
    SHAPE ABUTMENT ;
    PORT
      LAYER met2 ;
      RECT 1210.650 0.000 1210.790 0.420 ;
    END
  END w0_wd_in[458]
  PIN w0_wd_in[459]
    DIRECTION OUTPUT ;
    USE SIGNAL ;
    SHAPE ABUTMENT ;
    PORT
      LAYER met2 ;
      RECT 1216.630 0.000 1216.770 0.420 ;
    END
  END w0_wd_in[459]
  PIN w0_wd_in[460]
    DIRECTION OUTPUT ;
    USE SIGNAL ;
    SHAPE ABUTMENT ;
    PORT
      LAYER met2 ;
      RECT 1222.610 0.000 1222.750 0.420 ;
    END
  END w0_wd_in[460]
  PIN w0_wd_in[461]
    DIRECTION OUTPUT ;
    USE SIGNAL ;
    SHAPE ABUTMENT ;
    PORT
      LAYER met2 ;
      RECT 1228.590 0.000 1228.730 0.420 ;
    END
  END w0_wd_in[461]
  PIN w0_wd_in[462]
    DIRECTION OUTPUT ;
    USE SIGNAL ;
    SHAPE ABUTMENT ;
    PORT
      LAYER met2 ;
      RECT 1234.570 0.000 1234.710 0.420 ;
    END
  END w0_wd_in[462]
  PIN w0_wd_in[463]
    DIRECTION OUTPUT ;
    USE SIGNAL ;
    SHAPE ABUTMENT ;
    PORT
      LAYER met2 ;
      RECT 1240.550 0.000 1240.690 0.420 ;
    END
  END w0_wd_in[463]
  PIN w0_wd_in[464]
    DIRECTION OUTPUT ;
    USE SIGNAL ;
    SHAPE ABUTMENT ;
    PORT
      LAYER met2 ;
      RECT 1246.530 0.000 1246.670 0.420 ;
    END
  END w0_wd_in[464]
  PIN w0_wd_in[465]
    DIRECTION OUTPUT ;
    USE SIGNAL ;
    SHAPE ABUTMENT ;
    PORT
      LAYER met2 ;
      RECT 1252.510 0.000 1252.650 0.420 ;
    END
  END w0_wd_in[465]
  PIN w0_wd_in[466]
    DIRECTION OUTPUT ;
    USE SIGNAL ;
    SHAPE ABUTMENT ;
    PORT
      LAYER met2 ;
      RECT 1258.490 0.000 1258.630 0.420 ;
    END
  END w0_wd_in[466]
  PIN w0_wd_in[467]
    DIRECTION OUTPUT ;
    USE SIGNAL ;
    SHAPE ABUTMENT ;
    PORT
      LAYER met2 ;
      RECT 1264.470 0.000 1264.610 0.420 ;
    END
  END w0_wd_in[467]
  PIN w0_wd_in[468]
    DIRECTION OUTPUT ;
    USE SIGNAL ;
    SHAPE ABUTMENT ;
    PORT
      LAYER met2 ;
      RECT 1270.450 0.000 1270.590 0.420 ;
    END
  END w0_wd_in[468]
  PIN w0_wd_in[469]
    DIRECTION OUTPUT ;
    USE SIGNAL ;
    SHAPE ABUTMENT ;
    PORT
      LAYER met2 ;
      RECT 1276.430 0.000 1276.570 0.420 ;
    END
  END w0_wd_in[469]
  PIN w0_wd_in[470]
    DIRECTION OUTPUT ;
    USE SIGNAL ;
    SHAPE ABUTMENT ;
    PORT
      LAYER met2 ;
      RECT 1282.410 0.000 1282.550 0.420 ;
    END
  END w0_wd_in[470]
  PIN w0_wd_in[471]
    DIRECTION OUTPUT ;
    USE SIGNAL ;
    SHAPE ABUTMENT ;
    PORT
      LAYER met2 ;
      RECT 1288.390 0.000 1288.530 0.420 ;
    END
  END w0_wd_in[471]
  PIN w0_wd_in[472]
    DIRECTION OUTPUT ;
    USE SIGNAL ;
    SHAPE ABUTMENT ;
    PORT
      LAYER met2 ;
      RECT 1294.370 0.000 1294.510 0.420 ;
    END
  END w0_wd_in[472]
  PIN w0_wd_in[473]
    DIRECTION OUTPUT ;
    USE SIGNAL ;
    SHAPE ABUTMENT ;
    PORT
      LAYER met2 ;
      RECT 1300.350 0.000 1300.490 0.420 ;
    END
  END w0_wd_in[473]
  PIN w0_wd_in[474]
    DIRECTION OUTPUT ;
    USE SIGNAL ;
    SHAPE ABUTMENT ;
    PORT
      LAYER met2 ;
      RECT 1306.330 0.000 1306.470 0.420 ;
    END
  END w0_wd_in[474]
  PIN w0_wd_in[475]
    DIRECTION OUTPUT ;
    USE SIGNAL ;
    SHAPE ABUTMENT ;
    PORT
      LAYER met2 ;
      RECT 1312.310 0.000 1312.450 0.420 ;
    END
  END w0_wd_in[475]
  PIN w0_wd_in[476]
    DIRECTION OUTPUT ;
    USE SIGNAL ;
    SHAPE ABUTMENT ;
    PORT
      LAYER met2 ;
      RECT 1318.290 0.000 1318.430 0.420 ;
    END
  END w0_wd_in[476]
  PIN w0_wd_in[477]
    DIRECTION OUTPUT ;
    USE SIGNAL ;
    SHAPE ABUTMENT ;
    PORT
      LAYER met2 ;
      RECT 1324.270 0.000 1324.410 0.420 ;
    END
  END w0_wd_in[477]
  PIN w0_wd_in[478]
    DIRECTION OUTPUT ;
    USE SIGNAL ;
    SHAPE ABUTMENT ;
    PORT
      LAYER met2 ;
      RECT 1330.250 0.000 1330.390 0.420 ;
    END
  END w0_wd_in[478]
  PIN w0_wd_in[479]
    DIRECTION OUTPUT ;
    USE SIGNAL ;
    SHAPE ABUTMENT ;
    PORT
      LAYER met2 ;
      RECT 1336.230 0.000 1336.370 0.420 ;
    END
  END w0_wd_in[479]
  PIN w0_wd_in[480]
    DIRECTION OUTPUT ;
    USE SIGNAL ;
    SHAPE ABUTMENT ;
    PORT
      LAYER met2 ;
      RECT 1342.210 0.000 1342.350 0.420 ;
    END
  END w0_wd_in[480]
  PIN w0_wd_in[481]
    DIRECTION OUTPUT ;
    USE SIGNAL ;
    SHAPE ABUTMENT ;
    PORT
      LAYER met2 ;
      RECT 1348.190 0.000 1348.330 0.420 ;
    END
  END w0_wd_in[481]
  PIN w0_wd_in[482]
    DIRECTION OUTPUT ;
    USE SIGNAL ;
    SHAPE ABUTMENT ;
    PORT
      LAYER met2 ;
      RECT 1354.170 0.000 1354.310 0.420 ;
    END
  END w0_wd_in[482]
  PIN w0_wd_in[483]
    DIRECTION OUTPUT ;
    USE SIGNAL ;
    SHAPE ABUTMENT ;
    PORT
      LAYER met2 ;
      RECT 1360.150 0.000 1360.290 0.420 ;
    END
  END w0_wd_in[483]
  PIN w0_wd_in[484]
    DIRECTION OUTPUT ;
    USE SIGNAL ;
    SHAPE ABUTMENT ;
    PORT
      LAYER met2 ;
      RECT 1366.130 0.000 1366.270 0.420 ;
    END
  END w0_wd_in[484]
  PIN w0_wd_in[485]
    DIRECTION OUTPUT ;
    USE SIGNAL ;
    SHAPE ABUTMENT ;
    PORT
      LAYER met2 ;
      RECT 1372.110 0.000 1372.250 0.420 ;
    END
  END w0_wd_in[485]
  PIN w0_wd_in[486]
    DIRECTION OUTPUT ;
    USE SIGNAL ;
    SHAPE ABUTMENT ;
    PORT
      LAYER met2 ;
      RECT 1378.090 0.000 1378.230 0.420 ;
    END
  END w0_wd_in[486]
  PIN w0_wd_in[487]
    DIRECTION OUTPUT ;
    USE SIGNAL ;
    SHAPE ABUTMENT ;
    PORT
      LAYER met2 ;
      RECT 1384.070 0.000 1384.210 0.420 ;
    END
  END w0_wd_in[487]
  PIN w0_wd_in[488]
    DIRECTION OUTPUT ;
    USE SIGNAL ;
    SHAPE ABUTMENT ;
    PORT
      LAYER met2 ;
      RECT 1390.050 0.000 1390.190 0.420 ;
    END
  END w0_wd_in[488]
  PIN w0_wd_in[489]
    DIRECTION OUTPUT ;
    USE SIGNAL ;
    SHAPE ABUTMENT ;
    PORT
      LAYER met2 ;
      RECT 1396.030 0.000 1396.170 0.420 ;
    END
  END w0_wd_in[489]
  PIN w0_wd_in[490]
    DIRECTION OUTPUT ;
    USE SIGNAL ;
    SHAPE ABUTMENT ;
    PORT
      LAYER met2 ;
      RECT 1402.010 0.000 1402.150 0.420 ;
    END
  END w0_wd_in[490]
  PIN w0_wd_in[491]
    DIRECTION OUTPUT ;
    USE SIGNAL ;
    SHAPE ABUTMENT ;
    PORT
      LAYER met2 ;
      RECT 1407.990 0.000 1408.130 0.420 ;
    END
  END w0_wd_in[491]
  PIN w0_wd_in[492]
    DIRECTION OUTPUT ;
    USE SIGNAL ;
    SHAPE ABUTMENT ;
    PORT
      LAYER met2 ;
      RECT 1413.970 0.000 1414.110 0.420 ;
    END
  END w0_wd_in[492]
  PIN w0_wd_in[493]
    DIRECTION OUTPUT ;
    USE SIGNAL ;
    SHAPE ABUTMENT ;
    PORT
      LAYER met2 ;
      RECT 1419.950 0.000 1420.090 0.420 ;
    END
  END w0_wd_in[493]
  PIN w0_wd_in[494]
    DIRECTION OUTPUT ;
    USE SIGNAL ;
    SHAPE ABUTMENT ;
    PORT
      LAYER met2 ;
      RECT 1425.930 0.000 1426.070 0.420 ;
    END
  END w0_wd_in[494]
  PIN w0_wd_in[495]
    DIRECTION OUTPUT ;
    USE SIGNAL ;
    SHAPE ABUTMENT ;
    PORT
      LAYER met2 ;
      RECT 1431.910 0.000 1432.050 0.420 ;
    END
  END w0_wd_in[495]
  PIN w0_wd_in[496]
    DIRECTION OUTPUT ;
    USE SIGNAL ;
    SHAPE ABUTMENT ;
    PORT
      LAYER met2 ;
      RECT 1437.890 0.000 1438.030 0.420 ;
    END
  END w0_wd_in[496]
  PIN w0_wd_in[497]
    DIRECTION OUTPUT ;
    USE SIGNAL ;
    SHAPE ABUTMENT ;
    PORT
      LAYER met2 ;
      RECT 1443.870 0.000 1444.010 0.420 ;
    END
  END w0_wd_in[497]
  PIN w0_wd_in[498]
    DIRECTION OUTPUT ;
    USE SIGNAL ;
    SHAPE ABUTMENT ;
    PORT
      LAYER met2 ;
      RECT 1449.850 0.000 1449.990 0.420 ;
    END
  END w0_wd_in[498]
  PIN w0_wd_in[499]
    DIRECTION OUTPUT ;
    USE SIGNAL ;
    SHAPE ABUTMENT ;
    PORT
      LAYER met2 ;
      RECT 1455.830 0.000 1455.970 0.420 ;
    END
  END w0_wd_in[499]
  PIN w0_wd_in[500]
    DIRECTION OUTPUT ;
    USE SIGNAL ;
    SHAPE ABUTMENT ;
    PORT
      LAYER met2 ;
      RECT 1461.810 0.000 1461.950 0.420 ;
    END
  END w0_wd_in[500]
  PIN w0_wd_in[501]
    DIRECTION OUTPUT ;
    USE SIGNAL ;
    SHAPE ABUTMENT ;
    PORT
      LAYER met2 ;
      RECT 1467.790 0.000 1467.930 0.420 ;
    END
  END w0_wd_in[501]
  PIN w0_wd_in[502]
    DIRECTION OUTPUT ;
    USE SIGNAL ;
    SHAPE ABUTMENT ;
    PORT
      LAYER met2 ;
      RECT 1473.770 0.000 1473.910 0.420 ;
    END
  END w0_wd_in[502]
  PIN w0_wd_in[503]
    DIRECTION OUTPUT ;
    USE SIGNAL ;
    SHAPE ABUTMENT ;
    PORT
      LAYER met2 ;
      RECT 1479.750 0.000 1479.890 0.420 ;
    END
  END w0_wd_in[503]
  PIN w0_wd_in[504]
    DIRECTION OUTPUT ;
    USE SIGNAL ;
    SHAPE ABUTMENT ;
    PORT
      LAYER met2 ;
      RECT 1485.730 0.000 1485.870 0.420 ;
    END
  END w0_wd_in[504]
  PIN w0_wd_in[505]
    DIRECTION OUTPUT ;
    USE SIGNAL ;
    SHAPE ABUTMENT ;
    PORT
      LAYER met2 ;
      RECT 1491.710 0.000 1491.850 0.420 ;
    END
  END w0_wd_in[505]
  PIN w0_wd_in[506]
    DIRECTION OUTPUT ;
    USE SIGNAL ;
    SHAPE ABUTMENT ;
    PORT
      LAYER met2 ;
      RECT 1497.690 0.000 1497.830 0.420 ;
    END
  END w0_wd_in[506]
  PIN w0_wd_in[507]
    DIRECTION OUTPUT ;
    USE SIGNAL ;
    SHAPE ABUTMENT ;
    PORT
      LAYER met2 ;
      RECT 1503.670 0.000 1503.810 0.420 ;
    END
  END w0_wd_in[507]
  PIN w0_wd_in[508]
    DIRECTION OUTPUT ;
    USE SIGNAL ;
    SHAPE ABUTMENT ;
    PORT
      LAYER met2 ;
      RECT 1509.650 0.000 1509.790 0.420 ;
    END
  END w0_wd_in[508]
  PIN w0_wd_in[509]
    DIRECTION OUTPUT ;
    USE SIGNAL ;
    SHAPE ABUTMENT ;
    PORT
      LAYER met2 ;
      RECT 1515.630 0.000 1515.770 0.420 ;
    END
  END w0_wd_in[509]
  PIN w0_wd_in[510]
    DIRECTION OUTPUT ;
    USE SIGNAL ;
    SHAPE ABUTMENT ;
    PORT
      LAYER met2 ;
      RECT 1521.610 0.000 1521.750 0.420 ;
    END
  END w0_wd_in[510]
  PIN w0_wd_in[511]
    DIRECTION OUTPUT ;
    USE SIGNAL ;
    SHAPE ABUTMENT ;
    PORT
      LAYER met2 ;
      RECT 1527.590 0.000 1527.730 0.420 ;
    END
  END w0_wd_in[511]
  PIN r0_rd_out[0]
    DIRECTION OUTPUT ;
    USE SIGNAL ;
    SHAPE ABUTMENT ;
    PORT
      LAYER met2 ;
      RECT 1533.570 0.000 1533.710 0.420 ;
    END
  END r0_rd_out[0]
  PIN r0_rd_out[1]
    DIRECTION OUTPUT ;
    USE SIGNAL ;
    SHAPE ABUTMENT ;
    PORT
      LAYER met2 ;
      RECT 1539.550 0.000 1539.690 0.420 ;
    END
  END r0_rd_out[1]
  PIN r0_rd_out[2]
    DIRECTION OUTPUT ;
    USE SIGNAL ;
    SHAPE ABUTMENT ;
    PORT
      LAYER met2 ;
      RECT 1545.530 0.000 1545.670 0.420 ;
    END
  END r0_rd_out[2]
  PIN r0_rd_out[3]
    DIRECTION OUTPUT ;
    USE SIGNAL ;
    SHAPE ABUTMENT ;
    PORT
      LAYER met2 ;
      RECT 1551.510 0.000 1551.650 0.420 ;
    END
  END r0_rd_out[3]
  PIN r0_rd_out[4]
    DIRECTION OUTPUT ;
    USE SIGNAL ;
    SHAPE ABUTMENT ;
    PORT
      LAYER met2 ;
      RECT 1557.490 0.000 1557.630 0.420 ;
    END
  END r0_rd_out[4]
  PIN r0_rd_out[5]
    DIRECTION OUTPUT ;
    USE SIGNAL ;
    SHAPE ABUTMENT ;
    PORT
      LAYER met2 ;
      RECT 1563.470 0.000 1563.610 0.420 ;
    END
  END r0_rd_out[5]
  PIN r0_rd_out[6]
    DIRECTION OUTPUT ;
    USE SIGNAL ;
    SHAPE ABUTMENT ;
    PORT
      LAYER met2 ;
      RECT 1569.450 0.000 1569.590 0.420 ;
    END
  END r0_rd_out[6]
  PIN r0_rd_out[7]
    DIRECTION OUTPUT ;
    USE SIGNAL ;
    SHAPE ABUTMENT ;
    PORT
      LAYER met2 ;
      RECT 1575.430 0.000 1575.570 0.420 ;
    END
  END r0_rd_out[7]
  PIN r0_rd_out[8]
    DIRECTION OUTPUT ;
    USE SIGNAL ;
    SHAPE ABUTMENT ;
    PORT
      LAYER met2 ;
      RECT 1581.410 0.000 1581.550 0.420 ;
    END
  END r0_rd_out[8]
  PIN r0_rd_out[9]
    DIRECTION OUTPUT ;
    USE SIGNAL ;
    SHAPE ABUTMENT ;
    PORT
      LAYER met2 ;
      RECT 1587.390 0.000 1587.530 0.420 ;
    END
  END r0_rd_out[9]
  PIN r0_rd_out[10]
    DIRECTION OUTPUT ;
    USE SIGNAL ;
    SHAPE ABUTMENT ;
    PORT
      LAYER met2 ;
      RECT 1593.370 0.000 1593.510 0.420 ;
    END
  END r0_rd_out[10]
  PIN r0_rd_out[11]
    DIRECTION OUTPUT ;
    USE SIGNAL ;
    SHAPE ABUTMENT ;
    PORT
      LAYER met2 ;
      RECT 1599.350 0.000 1599.490 0.420 ;
    END
  END r0_rd_out[11]
  PIN r0_rd_out[12]
    DIRECTION OUTPUT ;
    USE SIGNAL ;
    SHAPE ABUTMENT ;
    PORT
      LAYER met2 ;
      RECT 1605.330 0.000 1605.470 0.420 ;
    END
  END r0_rd_out[12]
  PIN r0_rd_out[13]
    DIRECTION OUTPUT ;
    USE SIGNAL ;
    SHAPE ABUTMENT ;
    PORT
      LAYER met2 ;
      RECT 1611.310 0.000 1611.450 0.420 ;
    END
  END r0_rd_out[13]
  PIN r0_rd_out[14]
    DIRECTION OUTPUT ;
    USE SIGNAL ;
    SHAPE ABUTMENT ;
    PORT
      LAYER met2 ;
      RECT 1617.290 0.000 1617.430 0.420 ;
    END
  END r0_rd_out[14]
  PIN r0_rd_out[15]
    DIRECTION OUTPUT ;
    USE SIGNAL ;
    SHAPE ABUTMENT ;
    PORT
      LAYER met2 ;
      RECT 1623.270 0.000 1623.410 0.420 ;
    END
  END r0_rd_out[15]
  PIN r0_rd_out[16]
    DIRECTION OUTPUT ;
    USE SIGNAL ;
    SHAPE ABUTMENT ;
    PORT
      LAYER met2 ;
      RECT 1629.250 0.000 1629.390 0.420 ;
    END
  END r0_rd_out[16]
  PIN r0_rd_out[17]
    DIRECTION OUTPUT ;
    USE SIGNAL ;
    SHAPE ABUTMENT ;
    PORT
      LAYER met2 ;
      RECT 1635.230 0.000 1635.370 0.420 ;
    END
  END r0_rd_out[17]
  PIN r0_rd_out[18]
    DIRECTION OUTPUT ;
    USE SIGNAL ;
    SHAPE ABUTMENT ;
    PORT
      LAYER met2 ;
      RECT 1641.210 0.000 1641.350 0.420 ;
    END
  END r0_rd_out[18]
  PIN r0_rd_out[19]
    DIRECTION OUTPUT ;
    USE SIGNAL ;
    SHAPE ABUTMENT ;
    PORT
      LAYER met2 ;
      RECT 1647.190 0.000 1647.330 0.420 ;
    END
  END r0_rd_out[19]
  PIN r0_rd_out[20]
    DIRECTION OUTPUT ;
    USE SIGNAL ;
    SHAPE ABUTMENT ;
    PORT
      LAYER met2 ;
      RECT 1653.170 0.000 1653.310 0.420 ;
    END
  END r0_rd_out[20]
  PIN r0_rd_out[21]
    DIRECTION OUTPUT ;
    USE SIGNAL ;
    SHAPE ABUTMENT ;
    PORT
      LAYER met2 ;
      RECT 1659.150 0.000 1659.290 0.420 ;
    END
  END r0_rd_out[21]
  PIN r0_rd_out[22]
    DIRECTION OUTPUT ;
    USE SIGNAL ;
    SHAPE ABUTMENT ;
    PORT
      LAYER met2 ;
      RECT 1665.130 0.000 1665.270 0.420 ;
    END
  END r0_rd_out[22]
  PIN r0_rd_out[23]
    DIRECTION OUTPUT ;
    USE SIGNAL ;
    SHAPE ABUTMENT ;
    PORT
      LAYER met2 ;
      RECT 1671.110 0.000 1671.250 0.420 ;
    END
  END r0_rd_out[23]
  PIN r0_rd_out[24]
    DIRECTION OUTPUT ;
    USE SIGNAL ;
    SHAPE ABUTMENT ;
    PORT
      LAYER met2 ;
      RECT 1677.090 0.000 1677.230 0.420 ;
    END
  END r0_rd_out[24]
  PIN r0_rd_out[25]
    DIRECTION OUTPUT ;
    USE SIGNAL ;
    SHAPE ABUTMENT ;
    PORT
      LAYER met2 ;
      RECT 1683.070 0.000 1683.210 0.420 ;
    END
  END r0_rd_out[25]
  PIN r0_rd_out[26]
    DIRECTION OUTPUT ;
    USE SIGNAL ;
    SHAPE ABUTMENT ;
    PORT
      LAYER met2 ;
      RECT 1689.050 0.000 1689.190 0.420 ;
    END
  END r0_rd_out[26]
  PIN r0_rd_out[27]
    DIRECTION OUTPUT ;
    USE SIGNAL ;
    SHAPE ABUTMENT ;
    PORT
      LAYER met2 ;
      RECT 1695.030 0.000 1695.170 0.420 ;
    END
  END r0_rd_out[27]
  PIN r0_rd_out[28]
    DIRECTION OUTPUT ;
    USE SIGNAL ;
    SHAPE ABUTMENT ;
    PORT
      LAYER met2 ;
      RECT 1701.010 0.000 1701.150 0.420 ;
    END
  END r0_rd_out[28]
  PIN r0_rd_out[29]
    DIRECTION OUTPUT ;
    USE SIGNAL ;
    SHAPE ABUTMENT ;
    PORT
      LAYER met2 ;
      RECT 1706.990 0.000 1707.130 0.420 ;
    END
  END r0_rd_out[29]
  PIN r0_rd_out[30]
    DIRECTION OUTPUT ;
    USE SIGNAL ;
    SHAPE ABUTMENT ;
    PORT
      LAYER met2 ;
      RECT 1712.970 0.000 1713.110 0.420 ;
    END
  END r0_rd_out[30]
  PIN r0_rd_out[31]
    DIRECTION OUTPUT ;
    USE SIGNAL ;
    SHAPE ABUTMENT ;
    PORT
      LAYER met2 ;
      RECT 1718.950 0.000 1719.090 0.420 ;
    END
  END r0_rd_out[31]
  PIN r0_rd_out[32]
    DIRECTION OUTPUT ;
    USE SIGNAL ;
    SHAPE ABUTMENT ;
    PORT
      LAYER met2 ;
      RECT 1724.930 0.000 1725.070 0.420 ;
    END
  END r0_rd_out[32]
  PIN r0_rd_out[33]
    DIRECTION OUTPUT ;
    USE SIGNAL ;
    SHAPE ABUTMENT ;
    PORT
      LAYER met2 ;
      RECT 1730.910 0.000 1731.050 0.420 ;
    END
  END r0_rd_out[33]
  PIN r0_rd_out[34]
    DIRECTION OUTPUT ;
    USE SIGNAL ;
    SHAPE ABUTMENT ;
    PORT
      LAYER met2 ;
      RECT 1736.890 0.000 1737.030 0.420 ;
    END
  END r0_rd_out[34]
  PIN r0_rd_out[35]
    DIRECTION OUTPUT ;
    USE SIGNAL ;
    SHAPE ABUTMENT ;
    PORT
      LAYER met2 ;
      RECT 1742.870 0.000 1743.010 0.420 ;
    END
  END r0_rd_out[35]
  PIN r0_rd_out[36]
    DIRECTION OUTPUT ;
    USE SIGNAL ;
    SHAPE ABUTMENT ;
    PORT
      LAYER met2 ;
      RECT 1748.850 0.000 1748.990 0.420 ;
    END
  END r0_rd_out[36]
  PIN r0_rd_out[37]
    DIRECTION OUTPUT ;
    USE SIGNAL ;
    SHAPE ABUTMENT ;
    PORT
      LAYER met2 ;
      RECT 1754.830 0.000 1754.970 0.420 ;
    END
  END r0_rd_out[37]
  PIN r0_rd_out[38]
    DIRECTION OUTPUT ;
    USE SIGNAL ;
    SHAPE ABUTMENT ;
    PORT
      LAYER met2 ;
      RECT 1760.810 0.000 1760.950 0.420 ;
    END
  END r0_rd_out[38]
  PIN r0_rd_out[39]
    DIRECTION OUTPUT ;
    USE SIGNAL ;
    SHAPE ABUTMENT ;
    PORT
      LAYER met2 ;
      RECT 1766.790 0.000 1766.930 0.420 ;
    END
  END r0_rd_out[39]
  PIN r0_rd_out[40]
    DIRECTION OUTPUT ;
    USE SIGNAL ;
    SHAPE ABUTMENT ;
    PORT
      LAYER met2 ;
      RECT 1772.770 0.000 1772.910 0.420 ;
    END
  END r0_rd_out[40]
  PIN r0_rd_out[41]
    DIRECTION OUTPUT ;
    USE SIGNAL ;
    SHAPE ABUTMENT ;
    PORT
      LAYER met2 ;
      RECT 1778.750 0.000 1778.890 0.420 ;
    END
  END r0_rd_out[41]
  PIN r0_rd_out[42]
    DIRECTION OUTPUT ;
    USE SIGNAL ;
    SHAPE ABUTMENT ;
    PORT
      LAYER met2 ;
      RECT 1784.730 0.000 1784.870 0.420 ;
    END
  END r0_rd_out[42]
  PIN r0_rd_out[43]
    DIRECTION OUTPUT ;
    USE SIGNAL ;
    SHAPE ABUTMENT ;
    PORT
      LAYER met2 ;
      RECT 1790.710 0.000 1790.850 0.420 ;
    END
  END r0_rd_out[43]
  PIN r0_rd_out[44]
    DIRECTION OUTPUT ;
    USE SIGNAL ;
    SHAPE ABUTMENT ;
    PORT
      LAYER met2 ;
      RECT 1796.690 0.000 1796.830 0.420 ;
    END
  END r0_rd_out[44]
  PIN r0_rd_out[45]
    DIRECTION OUTPUT ;
    USE SIGNAL ;
    SHAPE ABUTMENT ;
    PORT
      LAYER met2 ;
      RECT 1802.670 0.000 1802.810 0.420 ;
    END
  END r0_rd_out[45]
  PIN r0_rd_out[46]
    DIRECTION OUTPUT ;
    USE SIGNAL ;
    SHAPE ABUTMENT ;
    PORT
      LAYER met2 ;
      RECT 1808.650 0.000 1808.790 0.420 ;
    END
  END r0_rd_out[46]
  PIN r0_rd_out[47]
    DIRECTION OUTPUT ;
    USE SIGNAL ;
    SHAPE ABUTMENT ;
    PORT
      LAYER met2 ;
      RECT 1814.630 0.000 1814.770 0.420 ;
    END
  END r0_rd_out[47]
  PIN r0_rd_out[48]
    DIRECTION OUTPUT ;
    USE SIGNAL ;
    SHAPE ABUTMENT ;
    PORT
      LAYER met2 ;
      RECT 1820.610 0.000 1820.750 0.420 ;
    END
  END r0_rd_out[48]
  PIN r0_rd_out[49]
    DIRECTION OUTPUT ;
    USE SIGNAL ;
    SHAPE ABUTMENT ;
    PORT
      LAYER met2 ;
      RECT 1826.590 0.000 1826.730 0.420 ;
    END
  END r0_rd_out[49]
  PIN r0_rd_out[50]
    DIRECTION OUTPUT ;
    USE SIGNAL ;
    SHAPE ABUTMENT ;
    PORT
      LAYER met2 ;
      RECT 1832.570 0.000 1832.710 0.420 ;
    END
  END r0_rd_out[50]
  PIN r0_rd_out[51]
    DIRECTION OUTPUT ;
    USE SIGNAL ;
    SHAPE ABUTMENT ;
    PORT
      LAYER met2 ;
      RECT 1838.550 0.000 1838.690 0.420 ;
    END
  END r0_rd_out[51]
  PIN r0_rd_out[52]
    DIRECTION OUTPUT ;
    USE SIGNAL ;
    SHAPE ABUTMENT ;
    PORT
      LAYER met2 ;
      RECT 1844.530 0.000 1844.670 0.420 ;
    END
  END r0_rd_out[52]
  PIN r0_rd_out[53]
    DIRECTION OUTPUT ;
    USE SIGNAL ;
    SHAPE ABUTMENT ;
    PORT
      LAYER met2 ;
      RECT 1850.510 0.000 1850.650 0.420 ;
    END
  END r0_rd_out[53]
  PIN r0_rd_out[54]
    DIRECTION OUTPUT ;
    USE SIGNAL ;
    SHAPE ABUTMENT ;
    PORT
      LAYER met2 ;
      RECT 1856.490 0.000 1856.630 0.420 ;
    END
  END r0_rd_out[54]
  PIN r0_rd_out[55]
    DIRECTION OUTPUT ;
    USE SIGNAL ;
    SHAPE ABUTMENT ;
    PORT
      LAYER met2 ;
      RECT 1862.470 0.000 1862.610 0.420 ;
    END
  END r0_rd_out[55]
  PIN r0_rd_out[56]
    DIRECTION OUTPUT ;
    USE SIGNAL ;
    SHAPE ABUTMENT ;
    PORT
      LAYER met2 ;
      RECT 1868.450 0.000 1868.590 0.420 ;
    END
  END r0_rd_out[56]
  PIN r0_rd_out[57]
    DIRECTION OUTPUT ;
    USE SIGNAL ;
    SHAPE ABUTMENT ;
    PORT
      LAYER met2 ;
      RECT 1874.430 0.000 1874.570 0.420 ;
    END
  END r0_rd_out[57]
  PIN r0_rd_out[58]
    DIRECTION OUTPUT ;
    USE SIGNAL ;
    SHAPE ABUTMENT ;
    PORT
      LAYER met2 ;
      RECT 1880.410 0.000 1880.550 0.420 ;
    END
  END r0_rd_out[58]
  PIN r0_rd_out[59]
    DIRECTION OUTPUT ;
    USE SIGNAL ;
    SHAPE ABUTMENT ;
    PORT
      LAYER met2 ;
      RECT 1886.390 0.000 1886.530 0.420 ;
    END
  END r0_rd_out[59]
  PIN r0_rd_out[60]
    DIRECTION OUTPUT ;
    USE SIGNAL ;
    SHAPE ABUTMENT ;
    PORT
      LAYER met2 ;
      RECT 1892.370 0.000 1892.510 0.420 ;
    END
  END r0_rd_out[60]
  PIN r0_rd_out[61]
    DIRECTION OUTPUT ;
    USE SIGNAL ;
    SHAPE ABUTMENT ;
    PORT
      LAYER met2 ;
      RECT 1898.350 0.000 1898.490 0.420 ;
    END
  END r0_rd_out[61]
  PIN r0_rd_out[62]
    DIRECTION OUTPUT ;
    USE SIGNAL ;
    SHAPE ABUTMENT ;
    PORT
      LAYER met2 ;
      RECT 1904.330 0.000 1904.470 0.420 ;
    END
  END r0_rd_out[62]
  PIN r0_rd_out[63]
    DIRECTION OUTPUT ;
    USE SIGNAL ;
    SHAPE ABUTMENT ;
    PORT
      LAYER met2 ;
      RECT 1910.310 0.000 1910.450 0.420 ;
    END
  END r0_rd_out[63]
  PIN r0_rd_out[64]
    DIRECTION OUTPUT ;
    USE SIGNAL ;
    SHAPE ABUTMENT ;
    PORT
      LAYER met2 ;
      RECT 1916.290 0.000 1916.430 0.420 ;
    END
  END r0_rd_out[64]
  PIN r0_rd_out[65]
    DIRECTION OUTPUT ;
    USE SIGNAL ;
    SHAPE ABUTMENT ;
    PORT
      LAYER met2 ;
      RECT 1922.270 0.000 1922.410 0.420 ;
    END
  END r0_rd_out[65]
  PIN r0_rd_out[66]
    DIRECTION OUTPUT ;
    USE SIGNAL ;
    SHAPE ABUTMENT ;
    PORT
      LAYER met2 ;
      RECT 1928.250 0.000 1928.390 0.420 ;
    END
  END r0_rd_out[66]
  PIN r0_rd_out[67]
    DIRECTION OUTPUT ;
    USE SIGNAL ;
    SHAPE ABUTMENT ;
    PORT
      LAYER met2 ;
      RECT 1934.230 0.000 1934.370 0.420 ;
    END
  END r0_rd_out[67]
  PIN r0_rd_out[68]
    DIRECTION OUTPUT ;
    USE SIGNAL ;
    SHAPE ABUTMENT ;
    PORT
      LAYER met2 ;
      RECT 1940.210 0.000 1940.350 0.420 ;
    END
  END r0_rd_out[68]
  PIN r0_rd_out[69]
    DIRECTION OUTPUT ;
    USE SIGNAL ;
    SHAPE ABUTMENT ;
    PORT
      LAYER met2 ;
      RECT 1946.190 0.000 1946.330 0.420 ;
    END
  END r0_rd_out[69]
  PIN r0_rd_out[70]
    DIRECTION OUTPUT ;
    USE SIGNAL ;
    SHAPE ABUTMENT ;
    PORT
      LAYER met2 ;
      RECT 1952.170 0.000 1952.310 0.420 ;
    END
  END r0_rd_out[70]
  PIN r0_rd_out[71]
    DIRECTION OUTPUT ;
    USE SIGNAL ;
    SHAPE ABUTMENT ;
    PORT
      LAYER met2 ;
      RECT 1958.150 0.000 1958.290 0.420 ;
    END
  END r0_rd_out[71]
  PIN r0_rd_out[72]
    DIRECTION OUTPUT ;
    USE SIGNAL ;
    SHAPE ABUTMENT ;
    PORT
      LAYER met2 ;
      RECT 1964.130 0.000 1964.270 0.420 ;
    END
  END r0_rd_out[72]
  PIN r0_rd_out[73]
    DIRECTION OUTPUT ;
    USE SIGNAL ;
    SHAPE ABUTMENT ;
    PORT
      LAYER met2 ;
      RECT 1970.110 0.000 1970.250 0.420 ;
    END
  END r0_rd_out[73]
  PIN r0_rd_out[74]
    DIRECTION OUTPUT ;
    USE SIGNAL ;
    SHAPE ABUTMENT ;
    PORT
      LAYER met2 ;
      RECT 1976.090 0.000 1976.230 0.420 ;
    END
  END r0_rd_out[74]
  PIN r0_rd_out[75]
    DIRECTION OUTPUT ;
    USE SIGNAL ;
    SHAPE ABUTMENT ;
    PORT
      LAYER met2 ;
      RECT 1982.070 0.000 1982.210 0.420 ;
    END
  END r0_rd_out[75]
  PIN r0_rd_out[76]
    DIRECTION OUTPUT ;
    USE SIGNAL ;
    SHAPE ABUTMENT ;
    PORT
      LAYER met2 ;
      RECT 1988.050 0.000 1988.190 0.420 ;
    END
  END r0_rd_out[76]
  PIN r0_rd_out[77]
    DIRECTION OUTPUT ;
    USE SIGNAL ;
    SHAPE ABUTMENT ;
    PORT
      LAYER met2 ;
      RECT 1994.030 0.000 1994.170 0.420 ;
    END
  END r0_rd_out[77]
  PIN r0_rd_out[78]
    DIRECTION OUTPUT ;
    USE SIGNAL ;
    SHAPE ABUTMENT ;
    PORT
      LAYER met2 ;
      RECT 2000.010 0.000 2000.150 0.420 ;
    END
  END r0_rd_out[78]
  PIN r0_rd_out[79]
    DIRECTION OUTPUT ;
    USE SIGNAL ;
    SHAPE ABUTMENT ;
    PORT
      LAYER met2 ;
      RECT 2005.990 0.000 2006.130 0.420 ;
    END
  END r0_rd_out[79]
  PIN r0_rd_out[80]
    DIRECTION OUTPUT ;
    USE SIGNAL ;
    SHAPE ABUTMENT ;
    PORT
      LAYER met2 ;
      RECT 2011.970 0.000 2012.110 0.420 ;
    END
  END r0_rd_out[80]
  PIN r0_rd_out[81]
    DIRECTION OUTPUT ;
    USE SIGNAL ;
    SHAPE ABUTMENT ;
    PORT
      LAYER met2 ;
      RECT 2017.950 0.000 2018.090 0.420 ;
    END
  END r0_rd_out[81]
  PIN r0_rd_out[82]
    DIRECTION OUTPUT ;
    USE SIGNAL ;
    SHAPE ABUTMENT ;
    PORT
      LAYER met2 ;
      RECT 2023.930 0.000 2024.070 0.420 ;
    END
  END r0_rd_out[82]
  PIN r0_rd_out[83]
    DIRECTION OUTPUT ;
    USE SIGNAL ;
    SHAPE ABUTMENT ;
    PORT
      LAYER met2 ;
      RECT 2029.910 0.000 2030.050 0.420 ;
    END
  END r0_rd_out[83]
  PIN r0_rd_out[84]
    DIRECTION OUTPUT ;
    USE SIGNAL ;
    SHAPE ABUTMENT ;
    PORT
      LAYER met2 ;
      RECT 2035.890 0.000 2036.030 0.420 ;
    END
  END r0_rd_out[84]
  PIN r0_rd_out[85]
    DIRECTION OUTPUT ;
    USE SIGNAL ;
    SHAPE ABUTMENT ;
    PORT
      LAYER met2 ;
      RECT 2041.870 0.000 2042.010 0.420 ;
    END
  END r0_rd_out[85]
  PIN r0_rd_out[86]
    DIRECTION OUTPUT ;
    USE SIGNAL ;
    SHAPE ABUTMENT ;
    PORT
      LAYER met2 ;
      RECT 2047.850 0.000 2047.990 0.420 ;
    END
  END r0_rd_out[86]
  PIN r0_rd_out[87]
    DIRECTION OUTPUT ;
    USE SIGNAL ;
    SHAPE ABUTMENT ;
    PORT
      LAYER met2 ;
      RECT 2053.830 0.000 2053.970 0.420 ;
    END
  END r0_rd_out[87]
  PIN r0_rd_out[88]
    DIRECTION OUTPUT ;
    USE SIGNAL ;
    SHAPE ABUTMENT ;
    PORT
      LAYER met2 ;
      RECT 2059.810 0.000 2059.950 0.420 ;
    END
  END r0_rd_out[88]
  PIN r0_rd_out[89]
    DIRECTION OUTPUT ;
    USE SIGNAL ;
    SHAPE ABUTMENT ;
    PORT
      LAYER met2 ;
      RECT 2065.790 0.000 2065.930 0.420 ;
    END
  END r0_rd_out[89]
  PIN r0_rd_out[90]
    DIRECTION OUTPUT ;
    USE SIGNAL ;
    SHAPE ABUTMENT ;
    PORT
      LAYER met2 ;
      RECT 2071.770 0.000 2071.910 0.420 ;
    END
  END r0_rd_out[90]
  PIN r0_rd_out[91]
    DIRECTION OUTPUT ;
    USE SIGNAL ;
    SHAPE ABUTMENT ;
    PORT
      LAYER met2 ;
      RECT 2077.750 0.000 2077.890 0.420 ;
    END
  END r0_rd_out[91]
  PIN r0_rd_out[92]
    DIRECTION OUTPUT ;
    USE SIGNAL ;
    SHAPE ABUTMENT ;
    PORT
      LAYER met2 ;
      RECT 2083.730 0.000 2083.870 0.420 ;
    END
  END r0_rd_out[92]
  PIN r0_rd_out[93]
    DIRECTION OUTPUT ;
    USE SIGNAL ;
    SHAPE ABUTMENT ;
    PORT
      LAYER met2 ;
      RECT 2089.710 0.000 2089.850 0.420 ;
    END
  END r0_rd_out[93]
  PIN r0_rd_out[94]
    DIRECTION OUTPUT ;
    USE SIGNAL ;
    SHAPE ABUTMENT ;
    PORT
      LAYER met2 ;
      RECT 2095.690 0.000 2095.830 0.420 ;
    END
  END r0_rd_out[94]
  PIN r0_rd_out[95]
    DIRECTION OUTPUT ;
    USE SIGNAL ;
    SHAPE ABUTMENT ;
    PORT
      LAYER met2 ;
      RECT 2101.670 0.000 2101.810 0.420 ;
    END
  END r0_rd_out[95]
  PIN r0_rd_out[96]
    DIRECTION OUTPUT ;
    USE SIGNAL ;
    SHAPE ABUTMENT ;
    PORT
      LAYER met2 ;
      RECT 2107.650 0.000 2107.790 0.420 ;
    END
  END r0_rd_out[96]
  PIN r0_rd_out[97]
    DIRECTION OUTPUT ;
    USE SIGNAL ;
    SHAPE ABUTMENT ;
    PORT
      LAYER met2 ;
      RECT 2113.630 0.000 2113.770 0.420 ;
    END
  END r0_rd_out[97]
  PIN r0_rd_out[98]
    DIRECTION OUTPUT ;
    USE SIGNAL ;
    SHAPE ABUTMENT ;
    PORT
      LAYER met2 ;
      RECT 2119.610 0.000 2119.750 0.420 ;
    END
  END r0_rd_out[98]
  PIN r0_rd_out[99]
    DIRECTION OUTPUT ;
    USE SIGNAL ;
    SHAPE ABUTMENT ;
    PORT
      LAYER met2 ;
      RECT 2125.590 0.000 2125.730 0.420 ;
    END
  END r0_rd_out[99]
  PIN r0_rd_out[100]
    DIRECTION OUTPUT ;
    USE SIGNAL ;
    SHAPE ABUTMENT ;
    PORT
      LAYER met2 ;
      RECT 2131.570 0.000 2131.710 0.420 ;
    END
  END r0_rd_out[100]
  PIN r0_rd_out[101]
    DIRECTION OUTPUT ;
    USE SIGNAL ;
    SHAPE ABUTMENT ;
    PORT
      LAYER met2 ;
      RECT 2137.550 0.000 2137.690 0.420 ;
    END
  END r0_rd_out[101]
  PIN r0_rd_out[102]
    DIRECTION OUTPUT ;
    USE SIGNAL ;
    SHAPE ABUTMENT ;
    PORT
      LAYER met2 ;
      RECT 2143.530 0.000 2143.670 0.420 ;
    END
  END r0_rd_out[102]
  PIN r0_rd_out[103]
    DIRECTION OUTPUT ;
    USE SIGNAL ;
    SHAPE ABUTMENT ;
    PORT
      LAYER met2 ;
      RECT 2149.510 0.000 2149.650 0.420 ;
    END
  END r0_rd_out[103]
  PIN r0_rd_out[104]
    DIRECTION OUTPUT ;
    USE SIGNAL ;
    SHAPE ABUTMENT ;
    PORT
      LAYER met2 ;
      RECT 2155.490 0.000 2155.630 0.420 ;
    END
  END r0_rd_out[104]
  PIN r0_rd_out[105]
    DIRECTION OUTPUT ;
    USE SIGNAL ;
    SHAPE ABUTMENT ;
    PORT
      LAYER met2 ;
      RECT 2161.470 0.000 2161.610 0.420 ;
    END
  END r0_rd_out[105]
  PIN r0_rd_out[106]
    DIRECTION OUTPUT ;
    USE SIGNAL ;
    SHAPE ABUTMENT ;
    PORT
      LAYER met2 ;
      RECT 2167.450 0.000 2167.590 0.420 ;
    END
  END r0_rd_out[106]
  PIN r0_rd_out[107]
    DIRECTION OUTPUT ;
    USE SIGNAL ;
    SHAPE ABUTMENT ;
    PORT
      LAYER met2 ;
      RECT 2173.430 0.000 2173.570 0.420 ;
    END
  END r0_rd_out[107]
  PIN r0_rd_out[108]
    DIRECTION OUTPUT ;
    USE SIGNAL ;
    SHAPE ABUTMENT ;
    PORT
      LAYER met2 ;
      RECT 2179.410 0.000 2179.550 0.420 ;
    END
  END r0_rd_out[108]
  PIN r0_rd_out[109]
    DIRECTION OUTPUT ;
    USE SIGNAL ;
    SHAPE ABUTMENT ;
    PORT
      LAYER met2 ;
      RECT 2185.390 0.000 2185.530 0.420 ;
    END
  END r0_rd_out[109]
  PIN r0_rd_out[110]
    DIRECTION OUTPUT ;
    USE SIGNAL ;
    SHAPE ABUTMENT ;
    PORT
      LAYER met2 ;
      RECT 2191.370 0.000 2191.510 0.420 ;
    END
  END r0_rd_out[110]
  PIN r0_rd_out[111]
    DIRECTION OUTPUT ;
    USE SIGNAL ;
    SHAPE ABUTMENT ;
    PORT
      LAYER met2 ;
      RECT 2197.350 0.000 2197.490 0.420 ;
    END
  END r0_rd_out[111]
  PIN r0_rd_out[112]
    DIRECTION OUTPUT ;
    USE SIGNAL ;
    SHAPE ABUTMENT ;
    PORT
      LAYER met2 ;
      RECT 2203.330 0.000 2203.470 0.420 ;
    END
  END r0_rd_out[112]
  PIN r0_rd_out[113]
    DIRECTION OUTPUT ;
    USE SIGNAL ;
    SHAPE ABUTMENT ;
    PORT
      LAYER met2 ;
      RECT 2209.310 0.000 2209.450 0.420 ;
    END
  END r0_rd_out[113]
  PIN r0_rd_out[114]
    DIRECTION OUTPUT ;
    USE SIGNAL ;
    SHAPE ABUTMENT ;
    PORT
      LAYER met2 ;
      RECT 2215.290 0.000 2215.430 0.420 ;
    END
  END r0_rd_out[114]
  PIN r0_rd_out[115]
    DIRECTION OUTPUT ;
    USE SIGNAL ;
    SHAPE ABUTMENT ;
    PORT
      LAYER met2 ;
      RECT 2221.270 0.000 2221.410 0.420 ;
    END
  END r0_rd_out[115]
  PIN r0_rd_out[116]
    DIRECTION OUTPUT ;
    USE SIGNAL ;
    SHAPE ABUTMENT ;
    PORT
      LAYER met2 ;
      RECT 2227.250 0.000 2227.390 0.420 ;
    END
  END r0_rd_out[116]
  PIN r0_rd_out[117]
    DIRECTION OUTPUT ;
    USE SIGNAL ;
    SHAPE ABUTMENT ;
    PORT
      LAYER met2 ;
      RECT 2233.230 0.000 2233.370 0.420 ;
    END
  END r0_rd_out[117]
  PIN r0_rd_out[118]
    DIRECTION OUTPUT ;
    USE SIGNAL ;
    SHAPE ABUTMENT ;
    PORT
      LAYER met2 ;
      RECT 2239.210 0.000 2239.350 0.420 ;
    END
  END r0_rd_out[118]
  PIN r0_rd_out[119]
    DIRECTION OUTPUT ;
    USE SIGNAL ;
    SHAPE ABUTMENT ;
    PORT
      LAYER met2 ;
      RECT 2245.190 0.000 2245.330 0.420 ;
    END
  END r0_rd_out[119]
  PIN r0_rd_out[120]
    DIRECTION OUTPUT ;
    USE SIGNAL ;
    SHAPE ABUTMENT ;
    PORT
      LAYER met2 ;
      RECT 2251.170 0.000 2251.310 0.420 ;
    END
  END r0_rd_out[120]
  PIN r0_rd_out[121]
    DIRECTION OUTPUT ;
    USE SIGNAL ;
    SHAPE ABUTMENT ;
    PORT
      LAYER met2 ;
      RECT 2257.150 0.000 2257.290 0.420 ;
    END
  END r0_rd_out[121]
  PIN r0_rd_out[122]
    DIRECTION OUTPUT ;
    USE SIGNAL ;
    SHAPE ABUTMENT ;
    PORT
      LAYER met2 ;
      RECT 2263.130 0.000 2263.270 0.420 ;
    END
  END r0_rd_out[122]
  PIN r0_rd_out[123]
    DIRECTION OUTPUT ;
    USE SIGNAL ;
    SHAPE ABUTMENT ;
    PORT
      LAYER met2 ;
      RECT 2269.110 0.000 2269.250 0.420 ;
    END
  END r0_rd_out[123]
  PIN r0_rd_out[124]
    DIRECTION OUTPUT ;
    USE SIGNAL ;
    SHAPE ABUTMENT ;
    PORT
      LAYER met2 ;
      RECT 2275.090 0.000 2275.230 0.420 ;
    END
  END r0_rd_out[124]
  PIN r0_rd_out[125]
    DIRECTION OUTPUT ;
    USE SIGNAL ;
    SHAPE ABUTMENT ;
    PORT
      LAYER met2 ;
      RECT 2281.070 0.000 2281.210 0.420 ;
    END
  END r0_rd_out[125]
  PIN r0_rd_out[126]
    DIRECTION OUTPUT ;
    USE SIGNAL ;
    SHAPE ABUTMENT ;
    PORT
      LAYER met2 ;
      RECT 2287.050 0.000 2287.190 0.420 ;
    END
  END r0_rd_out[126]
  PIN r0_rd_out[127]
    DIRECTION OUTPUT ;
    USE SIGNAL ;
    SHAPE ABUTMENT ;
    PORT
      LAYER met2 ;
      RECT 2293.030 0.000 2293.170 0.420 ;
    END
  END r0_rd_out[127]
  PIN r0_rd_out[128]
    DIRECTION OUTPUT ;
    USE SIGNAL ;
    SHAPE ABUTMENT ;
    PORT
      LAYER met2 ;
      RECT 2299.010 0.000 2299.150 0.420 ;
    END
  END r0_rd_out[128]
  PIN r0_rd_out[129]
    DIRECTION OUTPUT ;
    USE SIGNAL ;
    SHAPE ABUTMENT ;
    PORT
      LAYER met2 ;
      RECT 2304.990 0.000 2305.130 0.420 ;
    END
  END r0_rd_out[129]
  PIN r0_rd_out[130]
    DIRECTION OUTPUT ;
    USE SIGNAL ;
    SHAPE ABUTMENT ;
    PORT
      LAYER met2 ;
      RECT 2310.970 0.000 2311.110 0.420 ;
    END
  END r0_rd_out[130]
  PIN r0_rd_out[131]
    DIRECTION OUTPUT ;
    USE SIGNAL ;
    SHAPE ABUTMENT ;
    PORT
      LAYER met2 ;
      RECT 2316.950 0.000 2317.090 0.420 ;
    END
  END r0_rd_out[131]
  PIN r0_rd_out[132]
    DIRECTION OUTPUT ;
    USE SIGNAL ;
    SHAPE ABUTMENT ;
    PORT
      LAYER met2 ;
      RECT 2322.930 0.000 2323.070 0.420 ;
    END
  END r0_rd_out[132]
  PIN r0_rd_out[133]
    DIRECTION OUTPUT ;
    USE SIGNAL ;
    SHAPE ABUTMENT ;
    PORT
      LAYER met2 ;
      RECT 2328.910 0.000 2329.050 0.420 ;
    END
  END r0_rd_out[133]
  PIN r0_rd_out[134]
    DIRECTION OUTPUT ;
    USE SIGNAL ;
    SHAPE ABUTMENT ;
    PORT
      LAYER met2 ;
      RECT 2334.890 0.000 2335.030 0.420 ;
    END
  END r0_rd_out[134]
  PIN r0_rd_out[135]
    DIRECTION OUTPUT ;
    USE SIGNAL ;
    SHAPE ABUTMENT ;
    PORT
      LAYER met2 ;
      RECT 2340.870 0.000 2341.010 0.420 ;
    END
  END r0_rd_out[135]
  PIN r0_rd_out[136]
    DIRECTION OUTPUT ;
    USE SIGNAL ;
    SHAPE ABUTMENT ;
    PORT
      LAYER met2 ;
      RECT 2346.850 0.000 2346.990 0.420 ;
    END
  END r0_rd_out[136]
  PIN r0_rd_out[137]
    DIRECTION OUTPUT ;
    USE SIGNAL ;
    SHAPE ABUTMENT ;
    PORT
      LAYER met2 ;
      RECT 2352.830 0.000 2352.970 0.420 ;
    END
  END r0_rd_out[137]
  PIN r0_rd_out[138]
    DIRECTION OUTPUT ;
    USE SIGNAL ;
    SHAPE ABUTMENT ;
    PORT
      LAYER met2 ;
      RECT 2358.810 0.000 2358.950 0.420 ;
    END
  END r0_rd_out[138]
  PIN r0_rd_out[139]
    DIRECTION OUTPUT ;
    USE SIGNAL ;
    SHAPE ABUTMENT ;
    PORT
      LAYER met2 ;
      RECT 2364.790 0.000 2364.930 0.420 ;
    END
  END r0_rd_out[139]
  PIN r0_rd_out[140]
    DIRECTION OUTPUT ;
    USE SIGNAL ;
    SHAPE ABUTMENT ;
    PORT
      LAYER met2 ;
      RECT 2370.770 0.000 2370.910 0.420 ;
    END
  END r0_rd_out[140]
  PIN r0_rd_out[141]
    DIRECTION OUTPUT ;
    USE SIGNAL ;
    SHAPE ABUTMENT ;
    PORT
      LAYER met2 ;
      RECT 2376.750 0.000 2376.890 0.420 ;
    END
  END r0_rd_out[141]
  PIN r0_rd_out[142]
    DIRECTION OUTPUT ;
    USE SIGNAL ;
    SHAPE ABUTMENT ;
    PORT
      LAYER met2 ;
      RECT 2382.730 0.000 2382.870 0.420 ;
    END
  END r0_rd_out[142]
  PIN r0_rd_out[143]
    DIRECTION OUTPUT ;
    USE SIGNAL ;
    SHAPE ABUTMENT ;
    PORT
      LAYER met2 ;
      RECT 2388.710 0.000 2388.850 0.420 ;
    END
  END r0_rd_out[143]
  PIN r0_rd_out[144]
    DIRECTION OUTPUT ;
    USE SIGNAL ;
    SHAPE ABUTMENT ;
    PORT
      LAYER met2 ;
      RECT 2394.690 0.000 2394.830 0.420 ;
    END
  END r0_rd_out[144]
  PIN r0_rd_out[145]
    DIRECTION OUTPUT ;
    USE SIGNAL ;
    SHAPE ABUTMENT ;
    PORT
      LAYER met2 ;
      RECT 2400.670 0.000 2400.810 0.420 ;
    END
  END r0_rd_out[145]
  PIN r0_rd_out[146]
    DIRECTION OUTPUT ;
    USE SIGNAL ;
    SHAPE ABUTMENT ;
    PORT
      LAYER met2 ;
      RECT 2406.650 0.000 2406.790 0.420 ;
    END
  END r0_rd_out[146]
  PIN r0_rd_out[147]
    DIRECTION OUTPUT ;
    USE SIGNAL ;
    SHAPE ABUTMENT ;
    PORT
      LAYER met2 ;
      RECT 2412.630 0.000 2412.770 0.420 ;
    END
  END r0_rd_out[147]
  PIN r0_rd_out[148]
    DIRECTION OUTPUT ;
    USE SIGNAL ;
    SHAPE ABUTMENT ;
    PORT
      LAYER met2 ;
      RECT 2418.610 0.000 2418.750 0.420 ;
    END
  END r0_rd_out[148]
  PIN r0_rd_out[149]
    DIRECTION OUTPUT ;
    USE SIGNAL ;
    SHAPE ABUTMENT ;
    PORT
      LAYER met2 ;
      RECT 2424.590 0.000 2424.730 0.420 ;
    END
  END r0_rd_out[149]
  PIN r0_rd_out[150]
    DIRECTION OUTPUT ;
    USE SIGNAL ;
    SHAPE ABUTMENT ;
    PORT
      LAYER met2 ;
      RECT 2430.570 0.000 2430.710 0.420 ;
    END
  END r0_rd_out[150]
  PIN r0_rd_out[151]
    DIRECTION OUTPUT ;
    USE SIGNAL ;
    SHAPE ABUTMENT ;
    PORT
      LAYER met2 ;
      RECT 2436.550 0.000 2436.690 0.420 ;
    END
  END r0_rd_out[151]
  PIN r0_rd_out[152]
    DIRECTION OUTPUT ;
    USE SIGNAL ;
    SHAPE ABUTMENT ;
    PORT
      LAYER met2 ;
      RECT 2442.530 0.000 2442.670 0.420 ;
    END
  END r0_rd_out[152]
  PIN r0_rd_out[153]
    DIRECTION OUTPUT ;
    USE SIGNAL ;
    SHAPE ABUTMENT ;
    PORT
      LAYER met2 ;
      RECT 2448.510 0.000 2448.650 0.420 ;
    END
  END r0_rd_out[153]
  PIN r0_rd_out[154]
    DIRECTION OUTPUT ;
    USE SIGNAL ;
    SHAPE ABUTMENT ;
    PORT
      LAYER met2 ;
      RECT 2454.490 0.000 2454.630 0.420 ;
    END
  END r0_rd_out[154]
  PIN r0_rd_out[155]
    DIRECTION OUTPUT ;
    USE SIGNAL ;
    SHAPE ABUTMENT ;
    PORT
      LAYER met2 ;
      RECT 2460.470 0.000 2460.610 0.420 ;
    END
  END r0_rd_out[155]
  PIN r0_rd_out[156]
    DIRECTION OUTPUT ;
    USE SIGNAL ;
    SHAPE ABUTMENT ;
    PORT
      LAYER met2 ;
      RECT 2466.450 0.000 2466.590 0.420 ;
    END
  END r0_rd_out[156]
  PIN r0_rd_out[157]
    DIRECTION OUTPUT ;
    USE SIGNAL ;
    SHAPE ABUTMENT ;
    PORT
      LAYER met2 ;
      RECT 2472.430 0.000 2472.570 0.420 ;
    END
  END r0_rd_out[157]
  PIN r0_rd_out[158]
    DIRECTION OUTPUT ;
    USE SIGNAL ;
    SHAPE ABUTMENT ;
    PORT
      LAYER met2 ;
      RECT 2478.410 0.000 2478.550 0.420 ;
    END
  END r0_rd_out[158]
  PIN r0_rd_out[159]
    DIRECTION OUTPUT ;
    USE SIGNAL ;
    SHAPE ABUTMENT ;
    PORT
      LAYER met2 ;
      RECT 2484.390 0.000 2484.530 0.420 ;
    END
  END r0_rd_out[159]
  PIN r0_rd_out[160]
    DIRECTION OUTPUT ;
    USE SIGNAL ;
    SHAPE ABUTMENT ;
    PORT
      LAYER met2 ;
      RECT 2490.370 0.000 2490.510 0.420 ;
    END
  END r0_rd_out[160]
  PIN r0_rd_out[161]
    DIRECTION OUTPUT ;
    USE SIGNAL ;
    SHAPE ABUTMENT ;
    PORT
      LAYER met2 ;
      RECT 2496.350 0.000 2496.490 0.420 ;
    END
  END r0_rd_out[161]
  PIN r0_rd_out[162]
    DIRECTION OUTPUT ;
    USE SIGNAL ;
    SHAPE ABUTMENT ;
    PORT
      LAYER met2 ;
      RECT 2502.330 0.000 2502.470 0.420 ;
    END
  END r0_rd_out[162]
  PIN r0_rd_out[163]
    DIRECTION OUTPUT ;
    USE SIGNAL ;
    SHAPE ABUTMENT ;
    PORT
      LAYER met2 ;
      RECT 2508.310 0.000 2508.450 0.420 ;
    END
  END r0_rd_out[163]
  PIN r0_rd_out[164]
    DIRECTION OUTPUT ;
    USE SIGNAL ;
    SHAPE ABUTMENT ;
    PORT
      LAYER met2 ;
      RECT 2514.290 0.000 2514.430 0.420 ;
    END
  END r0_rd_out[164]
  PIN r0_rd_out[165]
    DIRECTION OUTPUT ;
    USE SIGNAL ;
    SHAPE ABUTMENT ;
    PORT
      LAYER met2 ;
      RECT 2520.270 0.000 2520.410 0.420 ;
    END
  END r0_rd_out[165]
  PIN r0_rd_out[166]
    DIRECTION OUTPUT ;
    USE SIGNAL ;
    SHAPE ABUTMENT ;
    PORT
      LAYER met2 ;
      RECT 2526.250 0.000 2526.390 0.420 ;
    END
  END r0_rd_out[166]
  PIN r0_rd_out[167]
    DIRECTION OUTPUT ;
    USE SIGNAL ;
    SHAPE ABUTMENT ;
    PORT
      LAYER met2 ;
      RECT 2532.230 0.000 2532.370 0.420 ;
    END
  END r0_rd_out[167]
  PIN r0_rd_out[168]
    DIRECTION OUTPUT ;
    USE SIGNAL ;
    SHAPE ABUTMENT ;
    PORT
      LAYER met2 ;
      RECT 2538.210 0.000 2538.350 0.420 ;
    END
  END r0_rd_out[168]
  PIN r0_rd_out[169]
    DIRECTION OUTPUT ;
    USE SIGNAL ;
    SHAPE ABUTMENT ;
    PORT
      LAYER met2 ;
      RECT 2544.190 0.000 2544.330 0.420 ;
    END
  END r0_rd_out[169]
  PIN r0_rd_out[170]
    DIRECTION OUTPUT ;
    USE SIGNAL ;
    SHAPE ABUTMENT ;
    PORT
      LAYER met2 ;
      RECT 2550.170 0.000 2550.310 0.420 ;
    END
  END r0_rd_out[170]
  PIN r0_rd_out[171]
    DIRECTION OUTPUT ;
    USE SIGNAL ;
    SHAPE ABUTMENT ;
    PORT
      LAYER met2 ;
      RECT 2556.150 0.000 2556.290 0.420 ;
    END
  END r0_rd_out[171]
  PIN r0_rd_out[172]
    DIRECTION OUTPUT ;
    USE SIGNAL ;
    SHAPE ABUTMENT ;
    PORT
      LAYER met2 ;
      RECT 2562.130 0.000 2562.270 0.420 ;
    END
  END r0_rd_out[172]
  PIN r0_rd_out[173]
    DIRECTION OUTPUT ;
    USE SIGNAL ;
    SHAPE ABUTMENT ;
    PORT
      LAYER met2 ;
      RECT 2568.110 0.000 2568.250 0.420 ;
    END
  END r0_rd_out[173]
  PIN r0_rd_out[174]
    DIRECTION OUTPUT ;
    USE SIGNAL ;
    SHAPE ABUTMENT ;
    PORT
      LAYER met2 ;
      RECT 2574.090 0.000 2574.230 0.420 ;
    END
  END r0_rd_out[174]
  PIN r0_rd_out[175]
    DIRECTION OUTPUT ;
    USE SIGNAL ;
    SHAPE ABUTMENT ;
    PORT
      LAYER met2 ;
      RECT 2580.070 0.000 2580.210 0.420 ;
    END
  END r0_rd_out[175]
  PIN r0_rd_out[176]
    DIRECTION OUTPUT ;
    USE SIGNAL ;
    SHAPE ABUTMENT ;
    PORT
      LAYER met2 ;
      RECT 2586.050 0.000 2586.190 0.420 ;
    END
  END r0_rd_out[176]
  PIN r0_rd_out[177]
    DIRECTION OUTPUT ;
    USE SIGNAL ;
    SHAPE ABUTMENT ;
    PORT
      LAYER met2 ;
      RECT 2592.030 0.000 2592.170 0.420 ;
    END
  END r0_rd_out[177]
  PIN r0_rd_out[178]
    DIRECTION OUTPUT ;
    USE SIGNAL ;
    SHAPE ABUTMENT ;
    PORT
      LAYER met2 ;
      RECT 2598.010 0.000 2598.150 0.420 ;
    END
  END r0_rd_out[178]
  PIN r0_rd_out[179]
    DIRECTION OUTPUT ;
    USE SIGNAL ;
    SHAPE ABUTMENT ;
    PORT
      LAYER met2 ;
      RECT 2603.990 0.000 2604.130 0.420 ;
    END
  END r0_rd_out[179]
  PIN r0_rd_out[180]
    DIRECTION OUTPUT ;
    USE SIGNAL ;
    SHAPE ABUTMENT ;
    PORT
      LAYER met2 ;
      RECT 2609.970 0.000 2610.110 0.420 ;
    END
  END r0_rd_out[180]
  PIN r0_rd_out[181]
    DIRECTION OUTPUT ;
    USE SIGNAL ;
    SHAPE ABUTMENT ;
    PORT
      LAYER met2 ;
      RECT 2615.950 0.000 2616.090 0.420 ;
    END
  END r0_rd_out[181]
  PIN r0_rd_out[182]
    DIRECTION OUTPUT ;
    USE SIGNAL ;
    SHAPE ABUTMENT ;
    PORT
      LAYER met2 ;
      RECT 2621.930 0.000 2622.070 0.420 ;
    END
  END r0_rd_out[182]
  PIN r0_rd_out[183]
    DIRECTION OUTPUT ;
    USE SIGNAL ;
    SHAPE ABUTMENT ;
    PORT
      LAYER met2 ;
      RECT 2627.910 0.000 2628.050 0.420 ;
    END
  END r0_rd_out[183]
  PIN r0_rd_out[184]
    DIRECTION OUTPUT ;
    USE SIGNAL ;
    SHAPE ABUTMENT ;
    PORT
      LAYER met2 ;
      RECT 2633.890 0.000 2634.030 0.420 ;
    END
  END r0_rd_out[184]
  PIN r0_rd_out[185]
    DIRECTION OUTPUT ;
    USE SIGNAL ;
    SHAPE ABUTMENT ;
    PORT
      LAYER met2 ;
      RECT 2639.870 0.000 2640.010 0.420 ;
    END
  END r0_rd_out[185]
  PIN r0_rd_out[186]
    DIRECTION OUTPUT ;
    USE SIGNAL ;
    SHAPE ABUTMENT ;
    PORT
      LAYER met2 ;
      RECT 2645.850 0.000 2645.990 0.420 ;
    END
  END r0_rd_out[186]
  PIN r0_rd_out[187]
    DIRECTION OUTPUT ;
    USE SIGNAL ;
    SHAPE ABUTMENT ;
    PORT
      LAYER met2 ;
      RECT 2651.830 0.000 2651.970 0.420 ;
    END
  END r0_rd_out[187]
  PIN r0_rd_out[188]
    DIRECTION OUTPUT ;
    USE SIGNAL ;
    SHAPE ABUTMENT ;
    PORT
      LAYER met2 ;
      RECT 2657.810 0.000 2657.950 0.420 ;
    END
  END r0_rd_out[188]
  PIN r0_rd_out[189]
    DIRECTION OUTPUT ;
    USE SIGNAL ;
    SHAPE ABUTMENT ;
    PORT
      LAYER met2 ;
      RECT 2663.790 0.000 2663.930 0.420 ;
    END
  END r0_rd_out[189]
  PIN r0_rd_out[190]
    DIRECTION OUTPUT ;
    USE SIGNAL ;
    SHAPE ABUTMENT ;
    PORT
      LAYER met2 ;
      RECT 2669.770 0.000 2669.910 0.420 ;
    END
  END r0_rd_out[190]
  PIN r0_rd_out[191]
    DIRECTION OUTPUT ;
    USE SIGNAL ;
    SHAPE ABUTMENT ;
    PORT
      LAYER met2 ;
      RECT 2675.750 0.000 2675.890 0.420 ;
    END
  END r0_rd_out[191]
  PIN r0_rd_out[192]
    DIRECTION OUTPUT ;
    USE SIGNAL ;
    SHAPE ABUTMENT ;
    PORT
      LAYER met2 ;
      RECT 2681.730 0.000 2681.870 0.420 ;
    END
  END r0_rd_out[192]
  PIN r0_rd_out[193]
    DIRECTION OUTPUT ;
    USE SIGNAL ;
    SHAPE ABUTMENT ;
    PORT
      LAYER met2 ;
      RECT 2687.710 0.000 2687.850 0.420 ;
    END
  END r0_rd_out[193]
  PIN r0_rd_out[194]
    DIRECTION OUTPUT ;
    USE SIGNAL ;
    SHAPE ABUTMENT ;
    PORT
      LAYER met2 ;
      RECT 2693.690 0.000 2693.830 0.420 ;
    END
  END r0_rd_out[194]
  PIN r0_rd_out[195]
    DIRECTION OUTPUT ;
    USE SIGNAL ;
    SHAPE ABUTMENT ;
    PORT
      LAYER met2 ;
      RECT 2699.670 0.000 2699.810 0.420 ;
    END
  END r0_rd_out[195]
  PIN r0_rd_out[196]
    DIRECTION OUTPUT ;
    USE SIGNAL ;
    SHAPE ABUTMENT ;
    PORT
      LAYER met2 ;
      RECT 2705.650 0.000 2705.790 0.420 ;
    END
  END r0_rd_out[196]
  PIN r0_rd_out[197]
    DIRECTION OUTPUT ;
    USE SIGNAL ;
    SHAPE ABUTMENT ;
    PORT
      LAYER met2 ;
      RECT 2711.630 0.000 2711.770 0.420 ;
    END
  END r0_rd_out[197]
  PIN r0_rd_out[198]
    DIRECTION OUTPUT ;
    USE SIGNAL ;
    SHAPE ABUTMENT ;
    PORT
      LAYER met2 ;
      RECT 2717.610 0.000 2717.750 0.420 ;
    END
  END r0_rd_out[198]
  PIN r0_rd_out[199]
    DIRECTION OUTPUT ;
    USE SIGNAL ;
    SHAPE ABUTMENT ;
    PORT
      LAYER met2 ;
      RECT 2723.590 0.000 2723.730 0.420 ;
    END
  END r0_rd_out[199]
  PIN r0_rd_out[200]
    DIRECTION OUTPUT ;
    USE SIGNAL ;
    SHAPE ABUTMENT ;
    PORT
      LAYER met2 ;
      RECT 2729.570 0.000 2729.710 0.420 ;
    END
  END r0_rd_out[200]
  PIN r0_rd_out[201]
    DIRECTION OUTPUT ;
    USE SIGNAL ;
    SHAPE ABUTMENT ;
    PORT
      LAYER met2 ;
      RECT 2735.550 0.000 2735.690 0.420 ;
    END
  END r0_rd_out[201]
  PIN r0_rd_out[202]
    DIRECTION OUTPUT ;
    USE SIGNAL ;
    SHAPE ABUTMENT ;
    PORT
      LAYER met2 ;
      RECT 2741.530 0.000 2741.670 0.420 ;
    END
  END r0_rd_out[202]
  PIN r0_rd_out[203]
    DIRECTION OUTPUT ;
    USE SIGNAL ;
    SHAPE ABUTMENT ;
    PORT
      LAYER met2 ;
      RECT 2747.510 0.000 2747.650 0.420 ;
    END
  END r0_rd_out[203]
  PIN r0_rd_out[204]
    DIRECTION OUTPUT ;
    USE SIGNAL ;
    SHAPE ABUTMENT ;
    PORT
      LAYER met2 ;
      RECT 2753.490 0.000 2753.630 0.420 ;
    END
  END r0_rd_out[204]
  PIN r0_rd_out[205]
    DIRECTION OUTPUT ;
    USE SIGNAL ;
    SHAPE ABUTMENT ;
    PORT
      LAYER met2 ;
      RECT 2759.470 0.000 2759.610 0.420 ;
    END
  END r0_rd_out[205]
  PIN r0_rd_out[206]
    DIRECTION OUTPUT ;
    USE SIGNAL ;
    SHAPE ABUTMENT ;
    PORT
      LAYER met2 ;
      RECT 2765.450 0.000 2765.590 0.420 ;
    END
  END r0_rd_out[206]
  PIN r0_rd_out[207]
    DIRECTION OUTPUT ;
    USE SIGNAL ;
    SHAPE ABUTMENT ;
    PORT
      LAYER met2 ;
      RECT 2771.430 0.000 2771.570 0.420 ;
    END
  END r0_rd_out[207]
  PIN r0_rd_out[208]
    DIRECTION OUTPUT ;
    USE SIGNAL ;
    SHAPE ABUTMENT ;
    PORT
      LAYER met2 ;
      RECT 2777.410 0.000 2777.550 0.420 ;
    END
  END r0_rd_out[208]
  PIN r0_rd_out[209]
    DIRECTION OUTPUT ;
    USE SIGNAL ;
    SHAPE ABUTMENT ;
    PORT
      LAYER met2 ;
      RECT 2783.390 0.000 2783.530 0.420 ;
    END
  END r0_rd_out[209]
  PIN r0_rd_out[210]
    DIRECTION OUTPUT ;
    USE SIGNAL ;
    SHAPE ABUTMENT ;
    PORT
      LAYER met2 ;
      RECT 2789.370 0.000 2789.510 0.420 ;
    END
  END r0_rd_out[210]
  PIN r0_rd_out[211]
    DIRECTION OUTPUT ;
    USE SIGNAL ;
    SHAPE ABUTMENT ;
    PORT
      LAYER met2 ;
      RECT 2795.350 0.000 2795.490 0.420 ;
    END
  END r0_rd_out[211]
  PIN r0_rd_out[212]
    DIRECTION OUTPUT ;
    USE SIGNAL ;
    SHAPE ABUTMENT ;
    PORT
      LAYER met2 ;
      RECT 2801.330 0.000 2801.470 0.420 ;
    END
  END r0_rd_out[212]
  PIN r0_rd_out[213]
    DIRECTION OUTPUT ;
    USE SIGNAL ;
    SHAPE ABUTMENT ;
    PORT
      LAYER met2 ;
      RECT 2807.310 0.000 2807.450 0.420 ;
    END
  END r0_rd_out[213]
  PIN r0_rd_out[214]
    DIRECTION OUTPUT ;
    USE SIGNAL ;
    SHAPE ABUTMENT ;
    PORT
      LAYER met2 ;
      RECT 2813.290 0.000 2813.430 0.420 ;
    END
  END r0_rd_out[214]
  PIN r0_rd_out[215]
    DIRECTION OUTPUT ;
    USE SIGNAL ;
    SHAPE ABUTMENT ;
    PORT
      LAYER met2 ;
      RECT 2819.270 0.000 2819.410 0.420 ;
    END
  END r0_rd_out[215]
  PIN r0_rd_out[216]
    DIRECTION OUTPUT ;
    USE SIGNAL ;
    SHAPE ABUTMENT ;
    PORT
      LAYER met2 ;
      RECT 2825.250 0.000 2825.390 0.420 ;
    END
  END r0_rd_out[216]
  PIN r0_rd_out[217]
    DIRECTION OUTPUT ;
    USE SIGNAL ;
    SHAPE ABUTMENT ;
    PORT
      LAYER met2 ;
      RECT 2831.230 0.000 2831.370 0.420 ;
    END
  END r0_rd_out[217]
  PIN r0_rd_out[218]
    DIRECTION OUTPUT ;
    USE SIGNAL ;
    SHAPE ABUTMENT ;
    PORT
      LAYER met2 ;
      RECT 2837.210 0.000 2837.350 0.420 ;
    END
  END r0_rd_out[218]
  PIN r0_rd_out[219]
    DIRECTION OUTPUT ;
    USE SIGNAL ;
    SHAPE ABUTMENT ;
    PORT
      LAYER met2 ;
      RECT 2843.190 0.000 2843.330 0.420 ;
    END
  END r0_rd_out[219]
  PIN r0_rd_out[220]
    DIRECTION OUTPUT ;
    USE SIGNAL ;
    SHAPE ABUTMENT ;
    PORT
      LAYER met2 ;
      RECT 2849.170 0.000 2849.310 0.420 ;
    END
  END r0_rd_out[220]
  PIN r0_rd_out[221]
    DIRECTION OUTPUT ;
    USE SIGNAL ;
    SHAPE ABUTMENT ;
    PORT
      LAYER met2 ;
      RECT 2855.150 0.000 2855.290 0.420 ;
    END
  END r0_rd_out[221]
  PIN r0_rd_out[222]
    DIRECTION OUTPUT ;
    USE SIGNAL ;
    SHAPE ABUTMENT ;
    PORT
      LAYER met2 ;
      RECT 2861.130 0.000 2861.270 0.420 ;
    END
  END r0_rd_out[222]
  PIN r0_rd_out[223]
    DIRECTION OUTPUT ;
    USE SIGNAL ;
    SHAPE ABUTMENT ;
    PORT
      LAYER met2 ;
      RECT 2867.110 0.000 2867.250 0.420 ;
    END
  END r0_rd_out[223]
  PIN r0_rd_out[224]
    DIRECTION OUTPUT ;
    USE SIGNAL ;
    SHAPE ABUTMENT ;
    PORT
      LAYER met2 ;
      RECT 2873.090 0.000 2873.230 0.420 ;
    END
  END r0_rd_out[224]
  PIN r0_rd_out[225]
    DIRECTION OUTPUT ;
    USE SIGNAL ;
    SHAPE ABUTMENT ;
    PORT
      LAYER met2 ;
      RECT 2879.070 0.000 2879.210 0.420 ;
    END
  END r0_rd_out[225]
  PIN r0_rd_out[226]
    DIRECTION OUTPUT ;
    USE SIGNAL ;
    SHAPE ABUTMENT ;
    PORT
      LAYER met2 ;
      RECT 2885.050 0.000 2885.190 0.420 ;
    END
  END r0_rd_out[226]
  PIN r0_rd_out[227]
    DIRECTION OUTPUT ;
    USE SIGNAL ;
    SHAPE ABUTMENT ;
    PORT
      LAYER met2 ;
      RECT 2891.030 0.000 2891.170 0.420 ;
    END
  END r0_rd_out[227]
  PIN r0_rd_out[228]
    DIRECTION OUTPUT ;
    USE SIGNAL ;
    SHAPE ABUTMENT ;
    PORT
      LAYER met2 ;
      RECT 2897.010 0.000 2897.150 0.420 ;
    END
  END r0_rd_out[228]
  PIN r0_rd_out[229]
    DIRECTION OUTPUT ;
    USE SIGNAL ;
    SHAPE ABUTMENT ;
    PORT
      LAYER met2 ;
      RECT 2902.990 0.000 2903.130 0.420 ;
    END
  END r0_rd_out[229]
  PIN r0_rd_out[230]
    DIRECTION OUTPUT ;
    USE SIGNAL ;
    SHAPE ABUTMENT ;
    PORT
      LAYER met2 ;
      RECT 2908.970 0.000 2909.110 0.420 ;
    END
  END r0_rd_out[230]
  PIN r0_rd_out[231]
    DIRECTION OUTPUT ;
    USE SIGNAL ;
    SHAPE ABUTMENT ;
    PORT
      LAYER met2 ;
      RECT 2914.950 0.000 2915.090 0.420 ;
    END
  END r0_rd_out[231]
  PIN r0_rd_out[232]
    DIRECTION OUTPUT ;
    USE SIGNAL ;
    SHAPE ABUTMENT ;
    PORT
      LAYER met2 ;
      RECT 2920.930 0.000 2921.070 0.420 ;
    END
  END r0_rd_out[232]
  PIN r0_rd_out[233]
    DIRECTION OUTPUT ;
    USE SIGNAL ;
    SHAPE ABUTMENT ;
    PORT
      LAYER met2 ;
      RECT 2926.910 0.000 2927.050 0.420 ;
    END
  END r0_rd_out[233]
  PIN r0_rd_out[234]
    DIRECTION OUTPUT ;
    USE SIGNAL ;
    SHAPE ABUTMENT ;
    PORT
      LAYER met2 ;
      RECT 2932.890 0.000 2933.030 0.420 ;
    END
  END r0_rd_out[234]
  PIN r0_rd_out[235]
    DIRECTION OUTPUT ;
    USE SIGNAL ;
    SHAPE ABUTMENT ;
    PORT
      LAYER met2 ;
      RECT 2938.870 0.000 2939.010 0.420 ;
    END
  END r0_rd_out[235]
  PIN r0_rd_out[236]
    DIRECTION OUTPUT ;
    USE SIGNAL ;
    SHAPE ABUTMENT ;
    PORT
      LAYER met2 ;
      RECT 2944.850 0.000 2944.990 0.420 ;
    END
  END r0_rd_out[236]
  PIN r0_rd_out[237]
    DIRECTION OUTPUT ;
    USE SIGNAL ;
    SHAPE ABUTMENT ;
    PORT
      LAYER met2 ;
      RECT 2950.830 0.000 2950.970 0.420 ;
    END
  END r0_rd_out[237]
  PIN r0_rd_out[238]
    DIRECTION OUTPUT ;
    USE SIGNAL ;
    SHAPE ABUTMENT ;
    PORT
      LAYER met2 ;
      RECT 2956.810 0.000 2956.950 0.420 ;
    END
  END r0_rd_out[238]
  PIN r0_rd_out[239]
    DIRECTION OUTPUT ;
    USE SIGNAL ;
    SHAPE ABUTMENT ;
    PORT
      LAYER met2 ;
      RECT 2962.790 0.000 2962.930 0.420 ;
    END
  END r0_rd_out[239]
  PIN r0_rd_out[240]
    DIRECTION OUTPUT ;
    USE SIGNAL ;
    SHAPE ABUTMENT ;
    PORT
      LAYER met2 ;
      RECT 2968.770 0.000 2968.910 0.420 ;
    END
  END r0_rd_out[240]
  PIN r0_rd_out[241]
    DIRECTION OUTPUT ;
    USE SIGNAL ;
    SHAPE ABUTMENT ;
    PORT
      LAYER met2 ;
      RECT 2974.750 0.000 2974.890 0.420 ;
    END
  END r0_rd_out[241]
  PIN r0_rd_out[242]
    DIRECTION OUTPUT ;
    USE SIGNAL ;
    SHAPE ABUTMENT ;
    PORT
      LAYER met2 ;
      RECT 2980.730 0.000 2980.870 0.420 ;
    END
  END r0_rd_out[242]
  PIN r0_rd_out[243]
    DIRECTION OUTPUT ;
    USE SIGNAL ;
    SHAPE ABUTMENT ;
    PORT
      LAYER met2 ;
      RECT 2986.710 0.000 2986.850 0.420 ;
    END
  END r0_rd_out[243]
  PIN r0_rd_out[244]
    DIRECTION OUTPUT ;
    USE SIGNAL ;
    SHAPE ABUTMENT ;
    PORT
      LAYER met2 ;
      RECT 2992.690 0.000 2992.830 0.420 ;
    END
  END r0_rd_out[244]
  PIN r0_rd_out[245]
    DIRECTION OUTPUT ;
    USE SIGNAL ;
    SHAPE ABUTMENT ;
    PORT
      LAYER met2 ;
      RECT 2998.670 0.000 2998.810 0.420 ;
    END
  END r0_rd_out[245]
  PIN r0_rd_out[246]
    DIRECTION OUTPUT ;
    USE SIGNAL ;
    SHAPE ABUTMENT ;
    PORT
      LAYER met2 ;
      RECT 3004.650 0.000 3004.790 0.420 ;
    END
  END r0_rd_out[246]
  PIN r0_rd_out[247]
    DIRECTION OUTPUT ;
    USE SIGNAL ;
    SHAPE ABUTMENT ;
    PORT
      LAYER met2 ;
      RECT 3010.630 0.000 3010.770 0.420 ;
    END
  END r0_rd_out[247]
  PIN r0_rd_out[248]
    DIRECTION OUTPUT ;
    USE SIGNAL ;
    SHAPE ABUTMENT ;
    PORT
      LAYER met2 ;
      RECT 3016.610 0.000 3016.750 0.420 ;
    END
  END r0_rd_out[248]
  PIN r0_rd_out[249]
    DIRECTION OUTPUT ;
    USE SIGNAL ;
    SHAPE ABUTMENT ;
    PORT
      LAYER met2 ;
      RECT 3022.590 0.000 3022.730 0.420 ;
    END
  END r0_rd_out[249]
  PIN r0_rd_out[250]
    DIRECTION OUTPUT ;
    USE SIGNAL ;
    SHAPE ABUTMENT ;
    PORT
      LAYER met2 ;
      RECT 3028.570 0.000 3028.710 0.420 ;
    END
  END r0_rd_out[250]
  PIN r0_rd_out[251]
    DIRECTION OUTPUT ;
    USE SIGNAL ;
    SHAPE ABUTMENT ;
    PORT
      LAYER met2 ;
      RECT 3034.550 0.000 3034.690 0.420 ;
    END
  END r0_rd_out[251]
  PIN r0_rd_out[252]
    DIRECTION OUTPUT ;
    USE SIGNAL ;
    SHAPE ABUTMENT ;
    PORT
      LAYER met2 ;
      RECT 3040.530 0.000 3040.670 0.420 ;
    END
  END r0_rd_out[252]
  PIN r0_rd_out[253]
    DIRECTION OUTPUT ;
    USE SIGNAL ;
    SHAPE ABUTMENT ;
    PORT
      LAYER met2 ;
      RECT 3046.510 0.000 3046.650 0.420 ;
    END
  END r0_rd_out[253]
  PIN r0_rd_out[254]
    DIRECTION OUTPUT ;
    USE SIGNAL ;
    SHAPE ABUTMENT ;
    PORT
      LAYER met2 ;
      RECT 3052.490 0.000 3052.630 0.420 ;
    END
  END r0_rd_out[254]
  PIN r0_rd_out[255]
    DIRECTION OUTPUT ;
    USE SIGNAL ;
    SHAPE ABUTMENT ;
    PORT
      LAYER met2 ;
      RECT 3058.470 0.000 3058.610 0.420 ;
    END
  END r0_rd_out[255]
  PIN r0_rd_out[256]
    DIRECTION OUTPUT ;
    USE SIGNAL ;
    SHAPE ABUTMENT ;
    PORT
      LAYER met2 ;
      RECT 2.690 1558.140 2.830 1558.560 ;
    END
  END r0_rd_out[256]
  PIN r0_rd_out[257]
    DIRECTION OUTPUT ;
    USE SIGNAL ;
    SHAPE ABUTMENT ;
    PORT
      LAYER met2 ;
      RECT 15.110 1558.140 15.250 1558.560 ;
    END
  END r0_rd_out[257]
  PIN r0_rd_out[258]
    DIRECTION OUTPUT ;
    USE SIGNAL ;
    SHAPE ABUTMENT ;
    PORT
      LAYER met2 ;
      RECT 27.530 1558.140 27.670 1558.560 ;
    END
  END r0_rd_out[258]
  PIN r0_rd_out[259]
    DIRECTION OUTPUT ;
    USE SIGNAL ;
    SHAPE ABUTMENT ;
    PORT
      LAYER met2 ;
      RECT 39.950 1558.140 40.090 1558.560 ;
    END
  END r0_rd_out[259]
  PIN r0_rd_out[260]
    DIRECTION OUTPUT ;
    USE SIGNAL ;
    SHAPE ABUTMENT ;
    PORT
      LAYER met2 ;
      RECT 52.370 1558.140 52.510 1558.560 ;
    END
  END r0_rd_out[260]
  PIN r0_rd_out[261]
    DIRECTION OUTPUT ;
    USE SIGNAL ;
    SHAPE ABUTMENT ;
    PORT
      LAYER met2 ;
      RECT 64.790 1558.140 64.930 1558.560 ;
    END
  END r0_rd_out[261]
  PIN r0_rd_out[262]
    DIRECTION OUTPUT ;
    USE SIGNAL ;
    SHAPE ABUTMENT ;
    PORT
      LAYER met2 ;
      RECT 77.210 1558.140 77.350 1558.560 ;
    END
  END r0_rd_out[262]
  PIN r0_rd_out[263]
    DIRECTION OUTPUT ;
    USE SIGNAL ;
    SHAPE ABUTMENT ;
    PORT
      LAYER met2 ;
      RECT 89.630 1558.140 89.770 1558.560 ;
    END
  END r0_rd_out[263]
  PIN r0_rd_out[264]
    DIRECTION OUTPUT ;
    USE SIGNAL ;
    SHAPE ABUTMENT ;
    PORT
      LAYER met2 ;
      RECT 102.050 1558.140 102.190 1558.560 ;
    END
  END r0_rd_out[264]
  PIN r0_rd_out[265]
    DIRECTION OUTPUT ;
    USE SIGNAL ;
    SHAPE ABUTMENT ;
    PORT
      LAYER met2 ;
      RECT 114.470 1558.140 114.610 1558.560 ;
    END
  END r0_rd_out[265]
  PIN r0_rd_out[266]
    DIRECTION OUTPUT ;
    USE SIGNAL ;
    SHAPE ABUTMENT ;
    PORT
      LAYER met2 ;
      RECT 126.890 1558.140 127.030 1558.560 ;
    END
  END r0_rd_out[266]
  PIN r0_rd_out[267]
    DIRECTION OUTPUT ;
    USE SIGNAL ;
    SHAPE ABUTMENT ;
    PORT
      LAYER met2 ;
      RECT 139.310 1558.140 139.450 1558.560 ;
    END
  END r0_rd_out[267]
  PIN r0_rd_out[268]
    DIRECTION OUTPUT ;
    USE SIGNAL ;
    SHAPE ABUTMENT ;
    PORT
      LAYER met2 ;
      RECT 151.730 1558.140 151.870 1558.560 ;
    END
  END r0_rd_out[268]
  PIN r0_rd_out[269]
    DIRECTION OUTPUT ;
    USE SIGNAL ;
    SHAPE ABUTMENT ;
    PORT
      LAYER met2 ;
      RECT 164.150 1558.140 164.290 1558.560 ;
    END
  END r0_rd_out[269]
  PIN r0_rd_out[270]
    DIRECTION OUTPUT ;
    USE SIGNAL ;
    SHAPE ABUTMENT ;
    PORT
      LAYER met2 ;
      RECT 176.570 1558.140 176.710 1558.560 ;
    END
  END r0_rd_out[270]
  PIN r0_rd_out[271]
    DIRECTION OUTPUT ;
    USE SIGNAL ;
    SHAPE ABUTMENT ;
    PORT
      LAYER met2 ;
      RECT 188.990 1558.140 189.130 1558.560 ;
    END
  END r0_rd_out[271]
  PIN r0_rd_out[272]
    DIRECTION OUTPUT ;
    USE SIGNAL ;
    SHAPE ABUTMENT ;
    PORT
      LAYER met2 ;
      RECT 201.410 1558.140 201.550 1558.560 ;
    END
  END r0_rd_out[272]
  PIN r0_rd_out[273]
    DIRECTION OUTPUT ;
    USE SIGNAL ;
    SHAPE ABUTMENT ;
    PORT
      LAYER met2 ;
      RECT 213.830 1558.140 213.970 1558.560 ;
    END
  END r0_rd_out[273]
  PIN r0_rd_out[274]
    DIRECTION OUTPUT ;
    USE SIGNAL ;
    SHAPE ABUTMENT ;
    PORT
      LAYER met2 ;
      RECT 226.250 1558.140 226.390 1558.560 ;
    END
  END r0_rd_out[274]
  PIN r0_rd_out[275]
    DIRECTION OUTPUT ;
    USE SIGNAL ;
    SHAPE ABUTMENT ;
    PORT
      LAYER met2 ;
      RECT 238.670 1558.140 238.810 1558.560 ;
    END
  END r0_rd_out[275]
  PIN r0_rd_out[276]
    DIRECTION OUTPUT ;
    USE SIGNAL ;
    SHAPE ABUTMENT ;
    PORT
      LAYER met2 ;
      RECT 251.090 1558.140 251.230 1558.560 ;
    END
  END r0_rd_out[276]
  PIN r0_rd_out[277]
    DIRECTION OUTPUT ;
    USE SIGNAL ;
    SHAPE ABUTMENT ;
    PORT
      LAYER met2 ;
      RECT 263.510 1558.140 263.650 1558.560 ;
    END
  END r0_rd_out[277]
  PIN r0_rd_out[278]
    DIRECTION OUTPUT ;
    USE SIGNAL ;
    SHAPE ABUTMENT ;
    PORT
      LAYER met2 ;
      RECT 275.930 1558.140 276.070 1558.560 ;
    END
  END r0_rd_out[278]
  PIN r0_rd_out[279]
    DIRECTION OUTPUT ;
    USE SIGNAL ;
    SHAPE ABUTMENT ;
    PORT
      LAYER met2 ;
      RECT 288.350 1558.140 288.490 1558.560 ;
    END
  END r0_rd_out[279]
  PIN r0_rd_out[280]
    DIRECTION OUTPUT ;
    USE SIGNAL ;
    SHAPE ABUTMENT ;
    PORT
      LAYER met2 ;
      RECT 300.770 1558.140 300.910 1558.560 ;
    END
  END r0_rd_out[280]
  PIN r0_rd_out[281]
    DIRECTION OUTPUT ;
    USE SIGNAL ;
    SHAPE ABUTMENT ;
    PORT
      LAYER met2 ;
      RECT 313.190 1558.140 313.330 1558.560 ;
    END
  END r0_rd_out[281]
  PIN r0_rd_out[282]
    DIRECTION OUTPUT ;
    USE SIGNAL ;
    SHAPE ABUTMENT ;
    PORT
      LAYER met2 ;
      RECT 325.610 1558.140 325.750 1558.560 ;
    END
  END r0_rd_out[282]
  PIN r0_rd_out[283]
    DIRECTION OUTPUT ;
    USE SIGNAL ;
    SHAPE ABUTMENT ;
    PORT
      LAYER met2 ;
      RECT 338.030 1558.140 338.170 1558.560 ;
    END
  END r0_rd_out[283]
  PIN r0_rd_out[284]
    DIRECTION OUTPUT ;
    USE SIGNAL ;
    SHAPE ABUTMENT ;
    PORT
      LAYER met2 ;
      RECT 350.450 1558.140 350.590 1558.560 ;
    END
  END r0_rd_out[284]
  PIN r0_rd_out[285]
    DIRECTION OUTPUT ;
    USE SIGNAL ;
    SHAPE ABUTMENT ;
    PORT
      LAYER met2 ;
      RECT 362.870 1558.140 363.010 1558.560 ;
    END
  END r0_rd_out[285]
  PIN r0_rd_out[286]
    DIRECTION OUTPUT ;
    USE SIGNAL ;
    SHAPE ABUTMENT ;
    PORT
      LAYER met2 ;
      RECT 375.290 1558.140 375.430 1558.560 ;
    END
  END r0_rd_out[286]
  PIN r0_rd_out[287]
    DIRECTION OUTPUT ;
    USE SIGNAL ;
    SHAPE ABUTMENT ;
    PORT
      LAYER met2 ;
      RECT 387.710 1558.140 387.850 1558.560 ;
    END
  END r0_rd_out[287]
  PIN r0_rd_out[288]
    DIRECTION OUTPUT ;
    USE SIGNAL ;
    SHAPE ABUTMENT ;
    PORT
      LAYER met2 ;
      RECT 400.130 1558.140 400.270 1558.560 ;
    END
  END r0_rd_out[288]
  PIN r0_rd_out[289]
    DIRECTION OUTPUT ;
    USE SIGNAL ;
    SHAPE ABUTMENT ;
    PORT
      LAYER met2 ;
      RECT 412.550 1558.140 412.690 1558.560 ;
    END
  END r0_rd_out[289]
  PIN r0_rd_out[290]
    DIRECTION OUTPUT ;
    USE SIGNAL ;
    SHAPE ABUTMENT ;
    PORT
      LAYER met2 ;
      RECT 424.970 1558.140 425.110 1558.560 ;
    END
  END r0_rd_out[290]
  PIN r0_rd_out[291]
    DIRECTION OUTPUT ;
    USE SIGNAL ;
    SHAPE ABUTMENT ;
    PORT
      LAYER met2 ;
      RECT 437.390 1558.140 437.530 1558.560 ;
    END
  END r0_rd_out[291]
  PIN r0_rd_out[292]
    DIRECTION OUTPUT ;
    USE SIGNAL ;
    SHAPE ABUTMENT ;
    PORT
      LAYER met2 ;
      RECT 449.810 1558.140 449.950 1558.560 ;
    END
  END r0_rd_out[292]
  PIN r0_rd_out[293]
    DIRECTION OUTPUT ;
    USE SIGNAL ;
    SHAPE ABUTMENT ;
    PORT
      LAYER met2 ;
      RECT 462.230 1558.140 462.370 1558.560 ;
    END
  END r0_rd_out[293]
  PIN r0_rd_out[294]
    DIRECTION OUTPUT ;
    USE SIGNAL ;
    SHAPE ABUTMENT ;
    PORT
      LAYER met2 ;
      RECT 474.650 1558.140 474.790 1558.560 ;
    END
  END r0_rd_out[294]
  PIN r0_rd_out[295]
    DIRECTION OUTPUT ;
    USE SIGNAL ;
    SHAPE ABUTMENT ;
    PORT
      LAYER met2 ;
      RECT 487.070 1558.140 487.210 1558.560 ;
    END
  END r0_rd_out[295]
  PIN r0_rd_out[296]
    DIRECTION OUTPUT ;
    USE SIGNAL ;
    SHAPE ABUTMENT ;
    PORT
      LAYER met2 ;
      RECT 499.490 1558.140 499.630 1558.560 ;
    END
  END r0_rd_out[296]
  PIN r0_rd_out[297]
    DIRECTION OUTPUT ;
    USE SIGNAL ;
    SHAPE ABUTMENT ;
    PORT
      LAYER met2 ;
      RECT 511.910 1558.140 512.050 1558.560 ;
    END
  END r0_rd_out[297]
  PIN r0_rd_out[298]
    DIRECTION OUTPUT ;
    USE SIGNAL ;
    SHAPE ABUTMENT ;
    PORT
      LAYER met2 ;
      RECT 524.330 1558.140 524.470 1558.560 ;
    END
  END r0_rd_out[298]
  PIN r0_rd_out[299]
    DIRECTION OUTPUT ;
    USE SIGNAL ;
    SHAPE ABUTMENT ;
    PORT
      LAYER met2 ;
      RECT 536.750 1558.140 536.890 1558.560 ;
    END
  END r0_rd_out[299]
  PIN r0_rd_out[300]
    DIRECTION OUTPUT ;
    USE SIGNAL ;
    SHAPE ABUTMENT ;
    PORT
      LAYER met2 ;
      RECT 549.170 1558.140 549.310 1558.560 ;
    END
  END r0_rd_out[300]
  PIN r0_rd_out[301]
    DIRECTION OUTPUT ;
    USE SIGNAL ;
    SHAPE ABUTMENT ;
    PORT
      LAYER met2 ;
      RECT 561.590 1558.140 561.730 1558.560 ;
    END
  END r0_rd_out[301]
  PIN r0_rd_out[302]
    DIRECTION OUTPUT ;
    USE SIGNAL ;
    SHAPE ABUTMENT ;
    PORT
      LAYER met2 ;
      RECT 574.010 1558.140 574.150 1558.560 ;
    END
  END r0_rd_out[302]
  PIN r0_rd_out[303]
    DIRECTION OUTPUT ;
    USE SIGNAL ;
    SHAPE ABUTMENT ;
    PORT
      LAYER met2 ;
      RECT 586.430 1558.140 586.570 1558.560 ;
    END
  END r0_rd_out[303]
  PIN r0_rd_out[304]
    DIRECTION OUTPUT ;
    USE SIGNAL ;
    SHAPE ABUTMENT ;
    PORT
      LAYER met2 ;
      RECT 598.850 1558.140 598.990 1558.560 ;
    END
  END r0_rd_out[304]
  PIN r0_rd_out[305]
    DIRECTION OUTPUT ;
    USE SIGNAL ;
    SHAPE ABUTMENT ;
    PORT
      LAYER met2 ;
      RECT 611.270 1558.140 611.410 1558.560 ;
    END
  END r0_rd_out[305]
  PIN r0_rd_out[306]
    DIRECTION OUTPUT ;
    USE SIGNAL ;
    SHAPE ABUTMENT ;
    PORT
      LAYER met2 ;
      RECT 623.690 1558.140 623.830 1558.560 ;
    END
  END r0_rd_out[306]
  PIN r0_rd_out[307]
    DIRECTION OUTPUT ;
    USE SIGNAL ;
    SHAPE ABUTMENT ;
    PORT
      LAYER met2 ;
      RECT 636.110 1558.140 636.250 1558.560 ;
    END
  END r0_rd_out[307]
  PIN r0_rd_out[308]
    DIRECTION OUTPUT ;
    USE SIGNAL ;
    SHAPE ABUTMENT ;
    PORT
      LAYER met2 ;
      RECT 648.530 1558.140 648.670 1558.560 ;
    END
  END r0_rd_out[308]
  PIN r0_rd_out[309]
    DIRECTION OUTPUT ;
    USE SIGNAL ;
    SHAPE ABUTMENT ;
    PORT
      LAYER met2 ;
      RECT 660.950 1558.140 661.090 1558.560 ;
    END
  END r0_rd_out[309]
  PIN r0_rd_out[310]
    DIRECTION OUTPUT ;
    USE SIGNAL ;
    SHAPE ABUTMENT ;
    PORT
      LAYER met2 ;
      RECT 673.370 1558.140 673.510 1558.560 ;
    END
  END r0_rd_out[310]
  PIN r0_rd_out[311]
    DIRECTION OUTPUT ;
    USE SIGNAL ;
    SHAPE ABUTMENT ;
    PORT
      LAYER met2 ;
      RECT 685.790 1558.140 685.930 1558.560 ;
    END
  END r0_rd_out[311]
  PIN r0_rd_out[312]
    DIRECTION OUTPUT ;
    USE SIGNAL ;
    SHAPE ABUTMENT ;
    PORT
      LAYER met2 ;
      RECT 698.210 1558.140 698.350 1558.560 ;
    END
  END r0_rd_out[312]
  PIN r0_rd_out[313]
    DIRECTION OUTPUT ;
    USE SIGNAL ;
    SHAPE ABUTMENT ;
    PORT
      LAYER met2 ;
      RECT 710.630 1558.140 710.770 1558.560 ;
    END
  END r0_rd_out[313]
  PIN r0_rd_out[314]
    DIRECTION OUTPUT ;
    USE SIGNAL ;
    SHAPE ABUTMENT ;
    PORT
      LAYER met2 ;
      RECT 723.050 1558.140 723.190 1558.560 ;
    END
  END r0_rd_out[314]
  PIN r0_rd_out[315]
    DIRECTION OUTPUT ;
    USE SIGNAL ;
    SHAPE ABUTMENT ;
    PORT
      LAYER met2 ;
      RECT 735.470 1558.140 735.610 1558.560 ;
    END
  END r0_rd_out[315]
  PIN r0_rd_out[316]
    DIRECTION OUTPUT ;
    USE SIGNAL ;
    SHAPE ABUTMENT ;
    PORT
      LAYER met2 ;
      RECT 747.890 1558.140 748.030 1558.560 ;
    END
  END r0_rd_out[316]
  PIN r0_rd_out[317]
    DIRECTION OUTPUT ;
    USE SIGNAL ;
    SHAPE ABUTMENT ;
    PORT
      LAYER met2 ;
      RECT 760.310 1558.140 760.450 1558.560 ;
    END
  END r0_rd_out[317]
  PIN r0_rd_out[318]
    DIRECTION OUTPUT ;
    USE SIGNAL ;
    SHAPE ABUTMENT ;
    PORT
      LAYER met2 ;
      RECT 772.730 1558.140 772.870 1558.560 ;
    END
  END r0_rd_out[318]
  PIN r0_rd_out[319]
    DIRECTION OUTPUT ;
    USE SIGNAL ;
    SHAPE ABUTMENT ;
    PORT
      LAYER met2 ;
      RECT 785.150 1558.140 785.290 1558.560 ;
    END
  END r0_rd_out[319]
  PIN r0_rd_out[320]
    DIRECTION OUTPUT ;
    USE SIGNAL ;
    SHAPE ABUTMENT ;
    PORT
      LAYER met2 ;
      RECT 797.570 1558.140 797.710 1558.560 ;
    END
  END r0_rd_out[320]
  PIN r0_rd_out[321]
    DIRECTION OUTPUT ;
    USE SIGNAL ;
    SHAPE ABUTMENT ;
    PORT
      LAYER met2 ;
      RECT 809.990 1558.140 810.130 1558.560 ;
    END
  END r0_rd_out[321]
  PIN r0_rd_out[322]
    DIRECTION OUTPUT ;
    USE SIGNAL ;
    SHAPE ABUTMENT ;
    PORT
      LAYER met2 ;
      RECT 822.410 1558.140 822.550 1558.560 ;
    END
  END r0_rd_out[322]
  PIN r0_rd_out[323]
    DIRECTION OUTPUT ;
    USE SIGNAL ;
    SHAPE ABUTMENT ;
    PORT
      LAYER met2 ;
      RECT 834.830 1558.140 834.970 1558.560 ;
    END
  END r0_rd_out[323]
  PIN r0_rd_out[324]
    DIRECTION OUTPUT ;
    USE SIGNAL ;
    SHAPE ABUTMENT ;
    PORT
      LAYER met2 ;
      RECT 847.250 1558.140 847.390 1558.560 ;
    END
  END r0_rd_out[324]
  PIN r0_rd_out[325]
    DIRECTION OUTPUT ;
    USE SIGNAL ;
    SHAPE ABUTMENT ;
    PORT
      LAYER met2 ;
      RECT 859.670 1558.140 859.810 1558.560 ;
    END
  END r0_rd_out[325]
  PIN r0_rd_out[326]
    DIRECTION OUTPUT ;
    USE SIGNAL ;
    SHAPE ABUTMENT ;
    PORT
      LAYER met2 ;
      RECT 872.090 1558.140 872.230 1558.560 ;
    END
  END r0_rd_out[326]
  PIN r0_rd_out[327]
    DIRECTION OUTPUT ;
    USE SIGNAL ;
    SHAPE ABUTMENT ;
    PORT
      LAYER met2 ;
      RECT 884.510 1558.140 884.650 1558.560 ;
    END
  END r0_rd_out[327]
  PIN r0_rd_out[328]
    DIRECTION OUTPUT ;
    USE SIGNAL ;
    SHAPE ABUTMENT ;
    PORT
      LAYER met2 ;
      RECT 896.930 1558.140 897.070 1558.560 ;
    END
  END r0_rd_out[328]
  PIN r0_rd_out[329]
    DIRECTION OUTPUT ;
    USE SIGNAL ;
    SHAPE ABUTMENT ;
    PORT
      LAYER met2 ;
      RECT 909.350 1558.140 909.490 1558.560 ;
    END
  END r0_rd_out[329]
  PIN r0_rd_out[330]
    DIRECTION OUTPUT ;
    USE SIGNAL ;
    SHAPE ABUTMENT ;
    PORT
      LAYER met2 ;
      RECT 921.770 1558.140 921.910 1558.560 ;
    END
  END r0_rd_out[330]
  PIN r0_rd_out[331]
    DIRECTION OUTPUT ;
    USE SIGNAL ;
    SHAPE ABUTMENT ;
    PORT
      LAYER met2 ;
      RECT 934.190 1558.140 934.330 1558.560 ;
    END
  END r0_rd_out[331]
  PIN r0_rd_out[332]
    DIRECTION OUTPUT ;
    USE SIGNAL ;
    SHAPE ABUTMENT ;
    PORT
      LAYER met2 ;
      RECT 946.610 1558.140 946.750 1558.560 ;
    END
  END r0_rd_out[332]
  PIN r0_rd_out[333]
    DIRECTION OUTPUT ;
    USE SIGNAL ;
    SHAPE ABUTMENT ;
    PORT
      LAYER met2 ;
      RECT 959.030 1558.140 959.170 1558.560 ;
    END
  END r0_rd_out[333]
  PIN r0_rd_out[334]
    DIRECTION OUTPUT ;
    USE SIGNAL ;
    SHAPE ABUTMENT ;
    PORT
      LAYER met2 ;
      RECT 971.450 1558.140 971.590 1558.560 ;
    END
  END r0_rd_out[334]
  PIN r0_rd_out[335]
    DIRECTION OUTPUT ;
    USE SIGNAL ;
    SHAPE ABUTMENT ;
    PORT
      LAYER met2 ;
      RECT 983.870 1558.140 984.010 1558.560 ;
    END
  END r0_rd_out[335]
  PIN r0_rd_out[336]
    DIRECTION OUTPUT ;
    USE SIGNAL ;
    SHAPE ABUTMENT ;
    PORT
      LAYER met2 ;
      RECT 996.290 1558.140 996.430 1558.560 ;
    END
  END r0_rd_out[336]
  PIN r0_rd_out[337]
    DIRECTION OUTPUT ;
    USE SIGNAL ;
    SHAPE ABUTMENT ;
    PORT
      LAYER met2 ;
      RECT 1008.710 1558.140 1008.850 1558.560 ;
    END
  END r0_rd_out[337]
  PIN r0_rd_out[338]
    DIRECTION OUTPUT ;
    USE SIGNAL ;
    SHAPE ABUTMENT ;
    PORT
      LAYER met2 ;
      RECT 1021.130 1558.140 1021.270 1558.560 ;
    END
  END r0_rd_out[338]
  PIN r0_rd_out[339]
    DIRECTION OUTPUT ;
    USE SIGNAL ;
    SHAPE ABUTMENT ;
    PORT
      LAYER met2 ;
      RECT 1033.550 1558.140 1033.690 1558.560 ;
    END
  END r0_rd_out[339]
  PIN r0_rd_out[340]
    DIRECTION OUTPUT ;
    USE SIGNAL ;
    SHAPE ABUTMENT ;
    PORT
      LAYER met2 ;
      RECT 1045.970 1558.140 1046.110 1558.560 ;
    END
  END r0_rd_out[340]
  PIN r0_rd_out[341]
    DIRECTION OUTPUT ;
    USE SIGNAL ;
    SHAPE ABUTMENT ;
    PORT
      LAYER met2 ;
      RECT 1058.390 1558.140 1058.530 1558.560 ;
    END
  END r0_rd_out[341]
  PIN r0_rd_out[342]
    DIRECTION OUTPUT ;
    USE SIGNAL ;
    SHAPE ABUTMENT ;
    PORT
      LAYER met2 ;
      RECT 1070.810 1558.140 1070.950 1558.560 ;
    END
  END r0_rd_out[342]
  PIN r0_rd_out[343]
    DIRECTION OUTPUT ;
    USE SIGNAL ;
    SHAPE ABUTMENT ;
    PORT
      LAYER met2 ;
      RECT 1083.230 1558.140 1083.370 1558.560 ;
    END
  END r0_rd_out[343]
  PIN r0_rd_out[344]
    DIRECTION OUTPUT ;
    USE SIGNAL ;
    SHAPE ABUTMENT ;
    PORT
      LAYER met2 ;
      RECT 1095.650 1558.140 1095.790 1558.560 ;
    END
  END r0_rd_out[344]
  PIN r0_rd_out[345]
    DIRECTION OUTPUT ;
    USE SIGNAL ;
    SHAPE ABUTMENT ;
    PORT
      LAYER met2 ;
      RECT 1108.070 1558.140 1108.210 1558.560 ;
    END
  END r0_rd_out[345]
  PIN r0_rd_out[346]
    DIRECTION OUTPUT ;
    USE SIGNAL ;
    SHAPE ABUTMENT ;
    PORT
      LAYER met2 ;
      RECT 1120.490 1558.140 1120.630 1558.560 ;
    END
  END r0_rd_out[346]
  PIN r0_rd_out[347]
    DIRECTION OUTPUT ;
    USE SIGNAL ;
    SHAPE ABUTMENT ;
    PORT
      LAYER met2 ;
      RECT 1132.910 1558.140 1133.050 1558.560 ;
    END
  END r0_rd_out[347]
  PIN r0_rd_out[348]
    DIRECTION OUTPUT ;
    USE SIGNAL ;
    SHAPE ABUTMENT ;
    PORT
      LAYER met2 ;
      RECT 1145.330 1558.140 1145.470 1558.560 ;
    END
  END r0_rd_out[348]
  PIN r0_rd_out[349]
    DIRECTION OUTPUT ;
    USE SIGNAL ;
    SHAPE ABUTMENT ;
    PORT
      LAYER met2 ;
      RECT 1157.750 1558.140 1157.890 1558.560 ;
    END
  END r0_rd_out[349]
  PIN r0_rd_out[350]
    DIRECTION OUTPUT ;
    USE SIGNAL ;
    SHAPE ABUTMENT ;
    PORT
      LAYER met2 ;
      RECT 1170.170 1558.140 1170.310 1558.560 ;
    END
  END r0_rd_out[350]
  PIN r0_rd_out[351]
    DIRECTION OUTPUT ;
    USE SIGNAL ;
    SHAPE ABUTMENT ;
    PORT
      LAYER met2 ;
      RECT 1182.590 1558.140 1182.730 1558.560 ;
    END
  END r0_rd_out[351]
  PIN r0_rd_out[352]
    DIRECTION OUTPUT ;
    USE SIGNAL ;
    SHAPE ABUTMENT ;
    PORT
      LAYER met2 ;
      RECT 1195.010 1558.140 1195.150 1558.560 ;
    END
  END r0_rd_out[352]
  PIN r0_rd_out[353]
    DIRECTION OUTPUT ;
    USE SIGNAL ;
    SHAPE ABUTMENT ;
    PORT
      LAYER met2 ;
      RECT 1207.430 1558.140 1207.570 1558.560 ;
    END
  END r0_rd_out[353]
  PIN r0_rd_out[354]
    DIRECTION OUTPUT ;
    USE SIGNAL ;
    SHAPE ABUTMENT ;
    PORT
      LAYER met2 ;
      RECT 1219.850 1558.140 1219.990 1558.560 ;
    END
  END r0_rd_out[354]
  PIN r0_rd_out[355]
    DIRECTION OUTPUT ;
    USE SIGNAL ;
    SHAPE ABUTMENT ;
    PORT
      LAYER met2 ;
      RECT 1232.270 1558.140 1232.410 1558.560 ;
    END
  END r0_rd_out[355]
  PIN r0_rd_out[356]
    DIRECTION OUTPUT ;
    USE SIGNAL ;
    SHAPE ABUTMENT ;
    PORT
      LAYER met2 ;
      RECT 1244.690 1558.140 1244.830 1558.560 ;
    END
  END r0_rd_out[356]
  PIN r0_rd_out[357]
    DIRECTION OUTPUT ;
    USE SIGNAL ;
    SHAPE ABUTMENT ;
    PORT
      LAYER met2 ;
      RECT 1257.110 1558.140 1257.250 1558.560 ;
    END
  END r0_rd_out[357]
  PIN r0_rd_out[358]
    DIRECTION OUTPUT ;
    USE SIGNAL ;
    SHAPE ABUTMENT ;
    PORT
      LAYER met2 ;
      RECT 1269.530 1558.140 1269.670 1558.560 ;
    END
  END r0_rd_out[358]
  PIN r0_rd_out[359]
    DIRECTION OUTPUT ;
    USE SIGNAL ;
    SHAPE ABUTMENT ;
    PORT
      LAYER met2 ;
      RECT 1281.950 1558.140 1282.090 1558.560 ;
    END
  END r0_rd_out[359]
  PIN r0_rd_out[360]
    DIRECTION OUTPUT ;
    USE SIGNAL ;
    SHAPE ABUTMENT ;
    PORT
      LAYER met2 ;
      RECT 1294.370 1558.140 1294.510 1558.560 ;
    END
  END r0_rd_out[360]
  PIN r0_rd_out[361]
    DIRECTION OUTPUT ;
    USE SIGNAL ;
    SHAPE ABUTMENT ;
    PORT
      LAYER met2 ;
      RECT 1306.790 1558.140 1306.930 1558.560 ;
    END
  END r0_rd_out[361]
  PIN r0_rd_out[362]
    DIRECTION OUTPUT ;
    USE SIGNAL ;
    SHAPE ABUTMENT ;
    PORT
      LAYER met2 ;
      RECT 1319.210 1558.140 1319.350 1558.560 ;
    END
  END r0_rd_out[362]
  PIN r0_rd_out[363]
    DIRECTION OUTPUT ;
    USE SIGNAL ;
    SHAPE ABUTMENT ;
    PORT
      LAYER met2 ;
      RECT 1331.630 1558.140 1331.770 1558.560 ;
    END
  END r0_rd_out[363]
  PIN r0_rd_out[364]
    DIRECTION OUTPUT ;
    USE SIGNAL ;
    SHAPE ABUTMENT ;
    PORT
      LAYER met2 ;
      RECT 1344.050 1558.140 1344.190 1558.560 ;
    END
  END r0_rd_out[364]
  PIN r0_rd_out[365]
    DIRECTION OUTPUT ;
    USE SIGNAL ;
    SHAPE ABUTMENT ;
    PORT
      LAYER met2 ;
      RECT 1356.470 1558.140 1356.610 1558.560 ;
    END
  END r0_rd_out[365]
  PIN r0_rd_out[366]
    DIRECTION OUTPUT ;
    USE SIGNAL ;
    SHAPE ABUTMENT ;
    PORT
      LAYER met2 ;
      RECT 1368.890 1558.140 1369.030 1558.560 ;
    END
  END r0_rd_out[366]
  PIN r0_rd_out[367]
    DIRECTION OUTPUT ;
    USE SIGNAL ;
    SHAPE ABUTMENT ;
    PORT
      LAYER met2 ;
      RECT 1381.310 1558.140 1381.450 1558.560 ;
    END
  END r0_rd_out[367]
  PIN r0_rd_out[368]
    DIRECTION OUTPUT ;
    USE SIGNAL ;
    SHAPE ABUTMENT ;
    PORT
      LAYER met2 ;
      RECT 1393.730 1558.140 1393.870 1558.560 ;
    END
  END r0_rd_out[368]
  PIN r0_rd_out[369]
    DIRECTION OUTPUT ;
    USE SIGNAL ;
    SHAPE ABUTMENT ;
    PORT
      LAYER met2 ;
      RECT 1406.150 1558.140 1406.290 1558.560 ;
    END
  END r0_rd_out[369]
  PIN r0_rd_out[370]
    DIRECTION OUTPUT ;
    USE SIGNAL ;
    SHAPE ABUTMENT ;
    PORT
      LAYER met2 ;
      RECT 1418.570 1558.140 1418.710 1558.560 ;
    END
  END r0_rd_out[370]
  PIN r0_rd_out[371]
    DIRECTION OUTPUT ;
    USE SIGNAL ;
    SHAPE ABUTMENT ;
    PORT
      LAYER met2 ;
      RECT 1430.990 1558.140 1431.130 1558.560 ;
    END
  END r0_rd_out[371]
  PIN r0_rd_out[372]
    DIRECTION OUTPUT ;
    USE SIGNAL ;
    SHAPE ABUTMENT ;
    PORT
      LAYER met2 ;
      RECT 1443.410 1558.140 1443.550 1558.560 ;
    END
  END r0_rd_out[372]
  PIN r0_rd_out[373]
    DIRECTION OUTPUT ;
    USE SIGNAL ;
    SHAPE ABUTMENT ;
    PORT
      LAYER met2 ;
      RECT 1455.830 1558.140 1455.970 1558.560 ;
    END
  END r0_rd_out[373]
  PIN r0_rd_out[374]
    DIRECTION OUTPUT ;
    USE SIGNAL ;
    SHAPE ABUTMENT ;
    PORT
      LAYER met2 ;
      RECT 1468.250 1558.140 1468.390 1558.560 ;
    END
  END r0_rd_out[374]
  PIN r0_rd_out[375]
    DIRECTION OUTPUT ;
    USE SIGNAL ;
    SHAPE ABUTMENT ;
    PORT
      LAYER met2 ;
      RECT 1480.670 1558.140 1480.810 1558.560 ;
    END
  END r0_rd_out[375]
  PIN r0_rd_out[376]
    DIRECTION OUTPUT ;
    USE SIGNAL ;
    SHAPE ABUTMENT ;
    PORT
      LAYER met2 ;
      RECT 1493.090 1558.140 1493.230 1558.560 ;
    END
  END r0_rd_out[376]
  PIN r0_rd_out[377]
    DIRECTION OUTPUT ;
    USE SIGNAL ;
    SHAPE ABUTMENT ;
    PORT
      LAYER met2 ;
      RECT 1505.510 1558.140 1505.650 1558.560 ;
    END
  END r0_rd_out[377]
  PIN r0_rd_out[378]
    DIRECTION OUTPUT ;
    USE SIGNAL ;
    SHAPE ABUTMENT ;
    PORT
      LAYER met2 ;
      RECT 1517.930 1558.140 1518.070 1558.560 ;
    END
  END r0_rd_out[378]
  PIN r0_rd_out[379]
    DIRECTION OUTPUT ;
    USE SIGNAL ;
    SHAPE ABUTMENT ;
    PORT
      LAYER met2 ;
      RECT 1530.350 1558.140 1530.490 1558.560 ;
    END
  END r0_rd_out[379]
  PIN r0_rd_out[380]
    DIRECTION OUTPUT ;
    USE SIGNAL ;
    SHAPE ABUTMENT ;
    PORT
      LAYER met2 ;
      RECT 1542.770 1558.140 1542.910 1558.560 ;
    END
  END r0_rd_out[380]
  PIN r0_rd_out[381]
    DIRECTION OUTPUT ;
    USE SIGNAL ;
    SHAPE ABUTMENT ;
    PORT
      LAYER met2 ;
      RECT 1555.190 1558.140 1555.330 1558.560 ;
    END
  END r0_rd_out[381]
  PIN r0_rd_out[382]
    DIRECTION OUTPUT ;
    USE SIGNAL ;
    SHAPE ABUTMENT ;
    PORT
      LAYER met2 ;
      RECT 1567.610 1558.140 1567.750 1558.560 ;
    END
  END r0_rd_out[382]
  PIN r0_rd_out[383]
    DIRECTION OUTPUT ;
    USE SIGNAL ;
    SHAPE ABUTMENT ;
    PORT
      LAYER met2 ;
      RECT 1580.030 1558.140 1580.170 1558.560 ;
    END
  END r0_rd_out[383]
  PIN r0_rd_out[384]
    DIRECTION OUTPUT ;
    USE SIGNAL ;
    SHAPE ABUTMENT ;
    PORT
      LAYER met2 ;
      RECT 1592.450 1558.140 1592.590 1558.560 ;
    END
  END r0_rd_out[384]
  PIN r0_rd_out[385]
    DIRECTION OUTPUT ;
    USE SIGNAL ;
    SHAPE ABUTMENT ;
    PORT
      LAYER met2 ;
      RECT 1604.870 1558.140 1605.010 1558.560 ;
    END
  END r0_rd_out[385]
  PIN r0_rd_out[386]
    DIRECTION OUTPUT ;
    USE SIGNAL ;
    SHAPE ABUTMENT ;
    PORT
      LAYER met2 ;
      RECT 1617.290 1558.140 1617.430 1558.560 ;
    END
  END r0_rd_out[386]
  PIN r0_rd_out[387]
    DIRECTION OUTPUT ;
    USE SIGNAL ;
    SHAPE ABUTMENT ;
    PORT
      LAYER met2 ;
      RECT 1629.710 1558.140 1629.850 1558.560 ;
    END
  END r0_rd_out[387]
  PIN r0_rd_out[388]
    DIRECTION OUTPUT ;
    USE SIGNAL ;
    SHAPE ABUTMENT ;
    PORT
      LAYER met2 ;
      RECT 1642.130 1558.140 1642.270 1558.560 ;
    END
  END r0_rd_out[388]
  PIN r0_rd_out[389]
    DIRECTION OUTPUT ;
    USE SIGNAL ;
    SHAPE ABUTMENT ;
    PORT
      LAYER met2 ;
      RECT 1654.550 1558.140 1654.690 1558.560 ;
    END
  END r0_rd_out[389]
  PIN r0_rd_out[390]
    DIRECTION OUTPUT ;
    USE SIGNAL ;
    SHAPE ABUTMENT ;
    PORT
      LAYER met2 ;
      RECT 1666.970 1558.140 1667.110 1558.560 ;
    END
  END r0_rd_out[390]
  PIN r0_rd_out[391]
    DIRECTION OUTPUT ;
    USE SIGNAL ;
    SHAPE ABUTMENT ;
    PORT
      LAYER met2 ;
      RECT 1679.390 1558.140 1679.530 1558.560 ;
    END
  END r0_rd_out[391]
  PIN r0_rd_out[392]
    DIRECTION OUTPUT ;
    USE SIGNAL ;
    SHAPE ABUTMENT ;
    PORT
      LAYER met2 ;
      RECT 1691.810 1558.140 1691.950 1558.560 ;
    END
  END r0_rd_out[392]
  PIN r0_rd_out[393]
    DIRECTION OUTPUT ;
    USE SIGNAL ;
    SHAPE ABUTMENT ;
    PORT
      LAYER met2 ;
      RECT 1704.230 1558.140 1704.370 1558.560 ;
    END
  END r0_rd_out[393]
  PIN r0_rd_out[394]
    DIRECTION OUTPUT ;
    USE SIGNAL ;
    SHAPE ABUTMENT ;
    PORT
      LAYER met2 ;
      RECT 1716.650 1558.140 1716.790 1558.560 ;
    END
  END r0_rd_out[394]
  PIN r0_rd_out[395]
    DIRECTION OUTPUT ;
    USE SIGNAL ;
    SHAPE ABUTMENT ;
    PORT
      LAYER met2 ;
      RECT 1729.070 1558.140 1729.210 1558.560 ;
    END
  END r0_rd_out[395]
  PIN r0_rd_out[396]
    DIRECTION OUTPUT ;
    USE SIGNAL ;
    SHAPE ABUTMENT ;
    PORT
      LAYER met2 ;
      RECT 1741.490 1558.140 1741.630 1558.560 ;
    END
  END r0_rd_out[396]
  PIN r0_rd_out[397]
    DIRECTION OUTPUT ;
    USE SIGNAL ;
    SHAPE ABUTMENT ;
    PORT
      LAYER met2 ;
      RECT 1753.910 1558.140 1754.050 1558.560 ;
    END
  END r0_rd_out[397]
  PIN r0_rd_out[398]
    DIRECTION OUTPUT ;
    USE SIGNAL ;
    SHAPE ABUTMENT ;
    PORT
      LAYER met2 ;
      RECT 1766.330 1558.140 1766.470 1558.560 ;
    END
  END r0_rd_out[398]
  PIN r0_rd_out[399]
    DIRECTION OUTPUT ;
    USE SIGNAL ;
    SHAPE ABUTMENT ;
    PORT
      LAYER met2 ;
      RECT 1778.750 1558.140 1778.890 1558.560 ;
    END
  END r0_rd_out[399]
  PIN r0_rd_out[400]
    DIRECTION OUTPUT ;
    USE SIGNAL ;
    SHAPE ABUTMENT ;
    PORT
      LAYER met2 ;
      RECT 1791.170 1558.140 1791.310 1558.560 ;
    END
  END r0_rd_out[400]
  PIN r0_rd_out[401]
    DIRECTION OUTPUT ;
    USE SIGNAL ;
    SHAPE ABUTMENT ;
    PORT
      LAYER met2 ;
      RECT 1803.590 1558.140 1803.730 1558.560 ;
    END
  END r0_rd_out[401]
  PIN r0_rd_out[402]
    DIRECTION OUTPUT ;
    USE SIGNAL ;
    SHAPE ABUTMENT ;
    PORT
      LAYER met2 ;
      RECT 1816.010 1558.140 1816.150 1558.560 ;
    END
  END r0_rd_out[402]
  PIN r0_rd_out[403]
    DIRECTION OUTPUT ;
    USE SIGNAL ;
    SHAPE ABUTMENT ;
    PORT
      LAYER met2 ;
      RECT 1828.430 1558.140 1828.570 1558.560 ;
    END
  END r0_rd_out[403]
  PIN r0_rd_out[404]
    DIRECTION OUTPUT ;
    USE SIGNAL ;
    SHAPE ABUTMENT ;
    PORT
      LAYER met2 ;
      RECT 1840.850 1558.140 1840.990 1558.560 ;
    END
  END r0_rd_out[404]
  PIN r0_rd_out[405]
    DIRECTION OUTPUT ;
    USE SIGNAL ;
    SHAPE ABUTMENT ;
    PORT
      LAYER met2 ;
      RECT 1853.270 1558.140 1853.410 1558.560 ;
    END
  END r0_rd_out[405]
  PIN r0_rd_out[406]
    DIRECTION OUTPUT ;
    USE SIGNAL ;
    SHAPE ABUTMENT ;
    PORT
      LAYER met2 ;
      RECT 1865.690 1558.140 1865.830 1558.560 ;
    END
  END r0_rd_out[406]
  PIN r0_rd_out[407]
    DIRECTION OUTPUT ;
    USE SIGNAL ;
    SHAPE ABUTMENT ;
    PORT
      LAYER met2 ;
      RECT 1878.110 1558.140 1878.250 1558.560 ;
    END
  END r0_rd_out[407]
  PIN r0_rd_out[408]
    DIRECTION OUTPUT ;
    USE SIGNAL ;
    SHAPE ABUTMENT ;
    PORT
      LAYER met2 ;
      RECT 1890.530 1558.140 1890.670 1558.560 ;
    END
  END r0_rd_out[408]
  PIN r0_rd_out[409]
    DIRECTION OUTPUT ;
    USE SIGNAL ;
    SHAPE ABUTMENT ;
    PORT
      LAYER met2 ;
      RECT 1902.950 1558.140 1903.090 1558.560 ;
    END
  END r0_rd_out[409]
  PIN r0_rd_out[410]
    DIRECTION OUTPUT ;
    USE SIGNAL ;
    SHAPE ABUTMENT ;
    PORT
      LAYER met2 ;
      RECT 1915.370 1558.140 1915.510 1558.560 ;
    END
  END r0_rd_out[410]
  PIN r0_rd_out[411]
    DIRECTION OUTPUT ;
    USE SIGNAL ;
    SHAPE ABUTMENT ;
    PORT
      LAYER met2 ;
      RECT 1927.790 1558.140 1927.930 1558.560 ;
    END
  END r0_rd_out[411]
  PIN r0_rd_out[412]
    DIRECTION OUTPUT ;
    USE SIGNAL ;
    SHAPE ABUTMENT ;
    PORT
      LAYER met2 ;
      RECT 1940.210 1558.140 1940.350 1558.560 ;
    END
  END r0_rd_out[412]
  PIN r0_rd_out[413]
    DIRECTION OUTPUT ;
    USE SIGNAL ;
    SHAPE ABUTMENT ;
    PORT
      LAYER met2 ;
      RECT 1952.630 1558.140 1952.770 1558.560 ;
    END
  END r0_rd_out[413]
  PIN r0_rd_out[414]
    DIRECTION OUTPUT ;
    USE SIGNAL ;
    SHAPE ABUTMENT ;
    PORT
      LAYER met2 ;
      RECT 1965.050 1558.140 1965.190 1558.560 ;
    END
  END r0_rd_out[414]
  PIN r0_rd_out[415]
    DIRECTION OUTPUT ;
    USE SIGNAL ;
    SHAPE ABUTMENT ;
    PORT
      LAYER met2 ;
      RECT 1977.470 1558.140 1977.610 1558.560 ;
    END
  END r0_rd_out[415]
  PIN r0_rd_out[416]
    DIRECTION OUTPUT ;
    USE SIGNAL ;
    SHAPE ABUTMENT ;
    PORT
      LAYER met2 ;
      RECT 1989.890 1558.140 1990.030 1558.560 ;
    END
  END r0_rd_out[416]
  PIN r0_rd_out[417]
    DIRECTION OUTPUT ;
    USE SIGNAL ;
    SHAPE ABUTMENT ;
    PORT
      LAYER met2 ;
      RECT 2002.310 1558.140 2002.450 1558.560 ;
    END
  END r0_rd_out[417]
  PIN r0_rd_out[418]
    DIRECTION OUTPUT ;
    USE SIGNAL ;
    SHAPE ABUTMENT ;
    PORT
      LAYER met2 ;
      RECT 2014.730 1558.140 2014.870 1558.560 ;
    END
  END r0_rd_out[418]
  PIN r0_rd_out[419]
    DIRECTION OUTPUT ;
    USE SIGNAL ;
    SHAPE ABUTMENT ;
    PORT
      LAYER met2 ;
      RECT 2027.150 1558.140 2027.290 1558.560 ;
    END
  END r0_rd_out[419]
  PIN r0_rd_out[420]
    DIRECTION OUTPUT ;
    USE SIGNAL ;
    SHAPE ABUTMENT ;
    PORT
      LAYER met2 ;
      RECT 2039.570 1558.140 2039.710 1558.560 ;
    END
  END r0_rd_out[420]
  PIN r0_rd_out[421]
    DIRECTION OUTPUT ;
    USE SIGNAL ;
    SHAPE ABUTMENT ;
    PORT
      LAYER met2 ;
      RECT 2051.990 1558.140 2052.130 1558.560 ;
    END
  END r0_rd_out[421]
  PIN r0_rd_out[422]
    DIRECTION OUTPUT ;
    USE SIGNAL ;
    SHAPE ABUTMENT ;
    PORT
      LAYER met2 ;
      RECT 2064.410 1558.140 2064.550 1558.560 ;
    END
  END r0_rd_out[422]
  PIN r0_rd_out[423]
    DIRECTION OUTPUT ;
    USE SIGNAL ;
    SHAPE ABUTMENT ;
    PORT
      LAYER met2 ;
      RECT 2076.830 1558.140 2076.970 1558.560 ;
    END
  END r0_rd_out[423]
  PIN r0_rd_out[424]
    DIRECTION OUTPUT ;
    USE SIGNAL ;
    SHAPE ABUTMENT ;
    PORT
      LAYER met2 ;
      RECT 2089.250 1558.140 2089.390 1558.560 ;
    END
  END r0_rd_out[424]
  PIN r0_rd_out[425]
    DIRECTION OUTPUT ;
    USE SIGNAL ;
    SHAPE ABUTMENT ;
    PORT
      LAYER met2 ;
      RECT 2101.670 1558.140 2101.810 1558.560 ;
    END
  END r0_rd_out[425]
  PIN r0_rd_out[426]
    DIRECTION OUTPUT ;
    USE SIGNAL ;
    SHAPE ABUTMENT ;
    PORT
      LAYER met2 ;
      RECT 2114.090 1558.140 2114.230 1558.560 ;
    END
  END r0_rd_out[426]
  PIN r0_rd_out[427]
    DIRECTION OUTPUT ;
    USE SIGNAL ;
    SHAPE ABUTMENT ;
    PORT
      LAYER met2 ;
      RECT 2126.510 1558.140 2126.650 1558.560 ;
    END
  END r0_rd_out[427]
  PIN r0_rd_out[428]
    DIRECTION OUTPUT ;
    USE SIGNAL ;
    SHAPE ABUTMENT ;
    PORT
      LAYER met2 ;
      RECT 2138.930 1558.140 2139.070 1558.560 ;
    END
  END r0_rd_out[428]
  PIN r0_rd_out[429]
    DIRECTION OUTPUT ;
    USE SIGNAL ;
    SHAPE ABUTMENT ;
    PORT
      LAYER met2 ;
      RECT 2151.350 1558.140 2151.490 1558.560 ;
    END
  END r0_rd_out[429]
  PIN r0_rd_out[430]
    DIRECTION OUTPUT ;
    USE SIGNAL ;
    SHAPE ABUTMENT ;
    PORT
      LAYER met2 ;
      RECT 2163.770 1558.140 2163.910 1558.560 ;
    END
  END r0_rd_out[430]
  PIN r0_rd_out[431]
    DIRECTION OUTPUT ;
    USE SIGNAL ;
    SHAPE ABUTMENT ;
    PORT
      LAYER met2 ;
      RECT 2176.190 1558.140 2176.330 1558.560 ;
    END
  END r0_rd_out[431]
  PIN r0_rd_out[432]
    DIRECTION OUTPUT ;
    USE SIGNAL ;
    SHAPE ABUTMENT ;
    PORT
      LAYER met2 ;
      RECT 2188.610 1558.140 2188.750 1558.560 ;
    END
  END r0_rd_out[432]
  PIN r0_rd_out[433]
    DIRECTION OUTPUT ;
    USE SIGNAL ;
    SHAPE ABUTMENT ;
    PORT
      LAYER met2 ;
      RECT 2201.030 1558.140 2201.170 1558.560 ;
    END
  END r0_rd_out[433]
  PIN r0_rd_out[434]
    DIRECTION OUTPUT ;
    USE SIGNAL ;
    SHAPE ABUTMENT ;
    PORT
      LAYER met2 ;
      RECT 2213.450 1558.140 2213.590 1558.560 ;
    END
  END r0_rd_out[434]
  PIN r0_rd_out[435]
    DIRECTION OUTPUT ;
    USE SIGNAL ;
    SHAPE ABUTMENT ;
    PORT
      LAYER met2 ;
      RECT 2225.870 1558.140 2226.010 1558.560 ;
    END
  END r0_rd_out[435]
  PIN r0_rd_out[436]
    DIRECTION OUTPUT ;
    USE SIGNAL ;
    SHAPE ABUTMENT ;
    PORT
      LAYER met2 ;
      RECT 2238.290 1558.140 2238.430 1558.560 ;
    END
  END r0_rd_out[436]
  PIN r0_rd_out[437]
    DIRECTION OUTPUT ;
    USE SIGNAL ;
    SHAPE ABUTMENT ;
    PORT
      LAYER met2 ;
      RECT 2250.710 1558.140 2250.850 1558.560 ;
    END
  END r0_rd_out[437]
  PIN r0_rd_out[438]
    DIRECTION OUTPUT ;
    USE SIGNAL ;
    SHAPE ABUTMENT ;
    PORT
      LAYER met2 ;
      RECT 2263.130 1558.140 2263.270 1558.560 ;
    END
  END r0_rd_out[438]
  PIN r0_rd_out[439]
    DIRECTION OUTPUT ;
    USE SIGNAL ;
    SHAPE ABUTMENT ;
    PORT
      LAYER met2 ;
      RECT 2275.550 1558.140 2275.690 1558.560 ;
    END
  END r0_rd_out[439]
  PIN r0_rd_out[440]
    DIRECTION OUTPUT ;
    USE SIGNAL ;
    SHAPE ABUTMENT ;
    PORT
      LAYER met2 ;
      RECT 2287.970 1558.140 2288.110 1558.560 ;
    END
  END r0_rd_out[440]
  PIN r0_rd_out[441]
    DIRECTION OUTPUT ;
    USE SIGNAL ;
    SHAPE ABUTMENT ;
    PORT
      LAYER met2 ;
      RECT 2300.390 1558.140 2300.530 1558.560 ;
    END
  END r0_rd_out[441]
  PIN r0_rd_out[442]
    DIRECTION OUTPUT ;
    USE SIGNAL ;
    SHAPE ABUTMENT ;
    PORT
      LAYER met2 ;
      RECT 2312.810 1558.140 2312.950 1558.560 ;
    END
  END r0_rd_out[442]
  PIN r0_rd_out[443]
    DIRECTION OUTPUT ;
    USE SIGNAL ;
    SHAPE ABUTMENT ;
    PORT
      LAYER met2 ;
      RECT 2325.230 1558.140 2325.370 1558.560 ;
    END
  END r0_rd_out[443]
  PIN r0_rd_out[444]
    DIRECTION OUTPUT ;
    USE SIGNAL ;
    SHAPE ABUTMENT ;
    PORT
      LAYER met2 ;
      RECT 2337.650 1558.140 2337.790 1558.560 ;
    END
  END r0_rd_out[444]
  PIN r0_rd_out[445]
    DIRECTION OUTPUT ;
    USE SIGNAL ;
    SHAPE ABUTMENT ;
    PORT
      LAYER met2 ;
      RECT 2350.070 1558.140 2350.210 1558.560 ;
    END
  END r0_rd_out[445]
  PIN r0_rd_out[446]
    DIRECTION OUTPUT ;
    USE SIGNAL ;
    SHAPE ABUTMENT ;
    PORT
      LAYER met2 ;
      RECT 2362.490 1558.140 2362.630 1558.560 ;
    END
  END r0_rd_out[446]
  PIN r0_rd_out[447]
    DIRECTION OUTPUT ;
    USE SIGNAL ;
    SHAPE ABUTMENT ;
    PORT
      LAYER met2 ;
      RECT 2374.910 1558.140 2375.050 1558.560 ;
    END
  END r0_rd_out[447]
  PIN r0_rd_out[448]
    DIRECTION OUTPUT ;
    USE SIGNAL ;
    SHAPE ABUTMENT ;
    PORT
      LAYER met2 ;
      RECT 2387.330 1558.140 2387.470 1558.560 ;
    END
  END r0_rd_out[448]
  PIN r0_rd_out[449]
    DIRECTION OUTPUT ;
    USE SIGNAL ;
    SHAPE ABUTMENT ;
    PORT
      LAYER met2 ;
      RECT 2399.750 1558.140 2399.890 1558.560 ;
    END
  END r0_rd_out[449]
  PIN r0_rd_out[450]
    DIRECTION OUTPUT ;
    USE SIGNAL ;
    SHAPE ABUTMENT ;
    PORT
      LAYER met2 ;
      RECT 2412.170 1558.140 2412.310 1558.560 ;
    END
  END r0_rd_out[450]
  PIN r0_rd_out[451]
    DIRECTION OUTPUT ;
    USE SIGNAL ;
    SHAPE ABUTMENT ;
    PORT
      LAYER met2 ;
      RECT 2424.590 1558.140 2424.730 1558.560 ;
    END
  END r0_rd_out[451]
  PIN r0_rd_out[452]
    DIRECTION OUTPUT ;
    USE SIGNAL ;
    SHAPE ABUTMENT ;
    PORT
      LAYER met2 ;
      RECT 2437.010 1558.140 2437.150 1558.560 ;
    END
  END r0_rd_out[452]
  PIN r0_rd_out[453]
    DIRECTION OUTPUT ;
    USE SIGNAL ;
    SHAPE ABUTMENT ;
    PORT
      LAYER met2 ;
      RECT 2449.430 1558.140 2449.570 1558.560 ;
    END
  END r0_rd_out[453]
  PIN r0_rd_out[454]
    DIRECTION OUTPUT ;
    USE SIGNAL ;
    SHAPE ABUTMENT ;
    PORT
      LAYER met2 ;
      RECT 2461.850 1558.140 2461.990 1558.560 ;
    END
  END r0_rd_out[454]
  PIN r0_rd_out[455]
    DIRECTION OUTPUT ;
    USE SIGNAL ;
    SHAPE ABUTMENT ;
    PORT
      LAYER met2 ;
      RECT 2474.270 1558.140 2474.410 1558.560 ;
    END
  END r0_rd_out[455]
  PIN r0_rd_out[456]
    DIRECTION OUTPUT ;
    USE SIGNAL ;
    SHAPE ABUTMENT ;
    PORT
      LAYER met2 ;
      RECT 2486.690 1558.140 2486.830 1558.560 ;
    END
  END r0_rd_out[456]
  PIN r0_rd_out[457]
    DIRECTION OUTPUT ;
    USE SIGNAL ;
    SHAPE ABUTMENT ;
    PORT
      LAYER met2 ;
      RECT 2499.110 1558.140 2499.250 1558.560 ;
    END
  END r0_rd_out[457]
  PIN r0_rd_out[458]
    DIRECTION OUTPUT ;
    USE SIGNAL ;
    SHAPE ABUTMENT ;
    PORT
      LAYER met2 ;
      RECT 2511.530 1558.140 2511.670 1558.560 ;
    END
  END r0_rd_out[458]
  PIN r0_rd_out[459]
    DIRECTION OUTPUT ;
    USE SIGNAL ;
    SHAPE ABUTMENT ;
    PORT
      LAYER met2 ;
      RECT 2523.950 1558.140 2524.090 1558.560 ;
    END
  END r0_rd_out[459]
  PIN r0_rd_out[460]
    DIRECTION OUTPUT ;
    USE SIGNAL ;
    SHAPE ABUTMENT ;
    PORT
      LAYER met2 ;
      RECT 2536.370 1558.140 2536.510 1558.560 ;
    END
  END r0_rd_out[460]
  PIN r0_rd_out[461]
    DIRECTION OUTPUT ;
    USE SIGNAL ;
    SHAPE ABUTMENT ;
    PORT
      LAYER met2 ;
      RECT 2548.790 1558.140 2548.930 1558.560 ;
    END
  END r0_rd_out[461]
  PIN r0_rd_out[462]
    DIRECTION OUTPUT ;
    USE SIGNAL ;
    SHAPE ABUTMENT ;
    PORT
      LAYER met2 ;
      RECT 2561.210 1558.140 2561.350 1558.560 ;
    END
  END r0_rd_out[462]
  PIN r0_rd_out[463]
    DIRECTION OUTPUT ;
    USE SIGNAL ;
    SHAPE ABUTMENT ;
    PORT
      LAYER met2 ;
      RECT 2573.630 1558.140 2573.770 1558.560 ;
    END
  END r0_rd_out[463]
  PIN r0_rd_out[464]
    DIRECTION OUTPUT ;
    USE SIGNAL ;
    SHAPE ABUTMENT ;
    PORT
      LAYER met2 ;
      RECT 2586.050 1558.140 2586.190 1558.560 ;
    END
  END r0_rd_out[464]
  PIN r0_rd_out[465]
    DIRECTION OUTPUT ;
    USE SIGNAL ;
    SHAPE ABUTMENT ;
    PORT
      LAYER met2 ;
      RECT 2598.470 1558.140 2598.610 1558.560 ;
    END
  END r0_rd_out[465]
  PIN r0_rd_out[466]
    DIRECTION OUTPUT ;
    USE SIGNAL ;
    SHAPE ABUTMENT ;
    PORT
      LAYER met2 ;
      RECT 2610.890 1558.140 2611.030 1558.560 ;
    END
  END r0_rd_out[466]
  PIN r0_rd_out[467]
    DIRECTION OUTPUT ;
    USE SIGNAL ;
    SHAPE ABUTMENT ;
    PORT
      LAYER met2 ;
      RECT 2623.310 1558.140 2623.450 1558.560 ;
    END
  END r0_rd_out[467]
  PIN r0_rd_out[468]
    DIRECTION OUTPUT ;
    USE SIGNAL ;
    SHAPE ABUTMENT ;
    PORT
      LAYER met2 ;
      RECT 2635.730 1558.140 2635.870 1558.560 ;
    END
  END r0_rd_out[468]
  PIN r0_rd_out[469]
    DIRECTION OUTPUT ;
    USE SIGNAL ;
    SHAPE ABUTMENT ;
    PORT
      LAYER met2 ;
      RECT 2648.150 1558.140 2648.290 1558.560 ;
    END
  END r0_rd_out[469]
  PIN r0_rd_out[470]
    DIRECTION OUTPUT ;
    USE SIGNAL ;
    SHAPE ABUTMENT ;
    PORT
      LAYER met2 ;
      RECT 2660.570 1558.140 2660.710 1558.560 ;
    END
  END r0_rd_out[470]
  PIN r0_rd_out[471]
    DIRECTION OUTPUT ;
    USE SIGNAL ;
    SHAPE ABUTMENT ;
    PORT
      LAYER met2 ;
      RECT 2672.990 1558.140 2673.130 1558.560 ;
    END
  END r0_rd_out[471]
  PIN r0_rd_out[472]
    DIRECTION OUTPUT ;
    USE SIGNAL ;
    SHAPE ABUTMENT ;
    PORT
      LAYER met2 ;
      RECT 2685.410 1558.140 2685.550 1558.560 ;
    END
  END r0_rd_out[472]
  PIN r0_rd_out[473]
    DIRECTION OUTPUT ;
    USE SIGNAL ;
    SHAPE ABUTMENT ;
    PORT
      LAYER met2 ;
      RECT 2697.830 1558.140 2697.970 1558.560 ;
    END
  END r0_rd_out[473]
  PIN r0_rd_out[474]
    DIRECTION OUTPUT ;
    USE SIGNAL ;
    SHAPE ABUTMENT ;
    PORT
      LAYER met2 ;
      RECT 2710.250 1558.140 2710.390 1558.560 ;
    END
  END r0_rd_out[474]
  PIN r0_rd_out[475]
    DIRECTION OUTPUT ;
    USE SIGNAL ;
    SHAPE ABUTMENT ;
    PORT
      LAYER met2 ;
      RECT 2722.670 1558.140 2722.810 1558.560 ;
    END
  END r0_rd_out[475]
  PIN r0_rd_out[476]
    DIRECTION OUTPUT ;
    USE SIGNAL ;
    SHAPE ABUTMENT ;
    PORT
      LAYER met2 ;
      RECT 2735.090 1558.140 2735.230 1558.560 ;
    END
  END r0_rd_out[476]
  PIN r0_rd_out[477]
    DIRECTION OUTPUT ;
    USE SIGNAL ;
    SHAPE ABUTMENT ;
    PORT
      LAYER met2 ;
      RECT 2747.510 1558.140 2747.650 1558.560 ;
    END
  END r0_rd_out[477]
  PIN r0_rd_out[478]
    DIRECTION OUTPUT ;
    USE SIGNAL ;
    SHAPE ABUTMENT ;
    PORT
      LAYER met2 ;
      RECT 2759.930 1558.140 2760.070 1558.560 ;
    END
  END r0_rd_out[478]
  PIN r0_rd_out[479]
    DIRECTION OUTPUT ;
    USE SIGNAL ;
    SHAPE ABUTMENT ;
    PORT
      LAYER met2 ;
      RECT 2772.350 1558.140 2772.490 1558.560 ;
    END
  END r0_rd_out[479]
  PIN r0_rd_out[480]
    DIRECTION OUTPUT ;
    USE SIGNAL ;
    SHAPE ABUTMENT ;
    PORT
      LAYER met2 ;
      RECT 2784.770 1558.140 2784.910 1558.560 ;
    END
  END r0_rd_out[480]
  PIN r0_rd_out[481]
    DIRECTION OUTPUT ;
    USE SIGNAL ;
    SHAPE ABUTMENT ;
    PORT
      LAYER met2 ;
      RECT 2797.190 1558.140 2797.330 1558.560 ;
    END
  END r0_rd_out[481]
  PIN r0_rd_out[482]
    DIRECTION OUTPUT ;
    USE SIGNAL ;
    SHAPE ABUTMENT ;
    PORT
      LAYER met2 ;
      RECT 2809.610 1558.140 2809.750 1558.560 ;
    END
  END r0_rd_out[482]
  PIN r0_rd_out[483]
    DIRECTION OUTPUT ;
    USE SIGNAL ;
    SHAPE ABUTMENT ;
    PORT
      LAYER met2 ;
      RECT 2822.030 1558.140 2822.170 1558.560 ;
    END
  END r0_rd_out[483]
  PIN r0_rd_out[484]
    DIRECTION OUTPUT ;
    USE SIGNAL ;
    SHAPE ABUTMENT ;
    PORT
      LAYER met2 ;
      RECT 2834.450 1558.140 2834.590 1558.560 ;
    END
  END r0_rd_out[484]
  PIN r0_rd_out[485]
    DIRECTION OUTPUT ;
    USE SIGNAL ;
    SHAPE ABUTMENT ;
    PORT
      LAYER met2 ;
      RECT 2846.870 1558.140 2847.010 1558.560 ;
    END
  END r0_rd_out[485]
  PIN r0_rd_out[486]
    DIRECTION OUTPUT ;
    USE SIGNAL ;
    SHAPE ABUTMENT ;
    PORT
      LAYER met2 ;
      RECT 2859.290 1558.140 2859.430 1558.560 ;
    END
  END r0_rd_out[486]
  PIN r0_rd_out[487]
    DIRECTION OUTPUT ;
    USE SIGNAL ;
    SHAPE ABUTMENT ;
    PORT
      LAYER met2 ;
      RECT 2871.710 1558.140 2871.850 1558.560 ;
    END
  END r0_rd_out[487]
  PIN r0_rd_out[488]
    DIRECTION OUTPUT ;
    USE SIGNAL ;
    SHAPE ABUTMENT ;
    PORT
      LAYER met2 ;
      RECT 2884.130 1558.140 2884.270 1558.560 ;
    END
  END r0_rd_out[488]
  PIN r0_rd_out[489]
    DIRECTION OUTPUT ;
    USE SIGNAL ;
    SHAPE ABUTMENT ;
    PORT
      LAYER met2 ;
      RECT 2896.550 1558.140 2896.690 1558.560 ;
    END
  END r0_rd_out[489]
  PIN r0_rd_out[490]
    DIRECTION OUTPUT ;
    USE SIGNAL ;
    SHAPE ABUTMENT ;
    PORT
      LAYER met2 ;
      RECT 2908.970 1558.140 2909.110 1558.560 ;
    END
  END r0_rd_out[490]
  PIN r0_rd_out[491]
    DIRECTION OUTPUT ;
    USE SIGNAL ;
    SHAPE ABUTMENT ;
    PORT
      LAYER met2 ;
      RECT 2921.390 1558.140 2921.530 1558.560 ;
    END
  END r0_rd_out[491]
  PIN r0_rd_out[492]
    DIRECTION OUTPUT ;
    USE SIGNAL ;
    SHAPE ABUTMENT ;
    PORT
      LAYER met2 ;
      RECT 2933.810 1558.140 2933.950 1558.560 ;
    END
  END r0_rd_out[492]
  PIN r0_rd_out[493]
    DIRECTION OUTPUT ;
    USE SIGNAL ;
    SHAPE ABUTMENT ;
    PORT
      LAYER met2 ;
      RECT 2946.230 1558.140 2946.370 1558.560 ;
    END
  END r0_rd_out[493]
  PIN r0_rd_out[494]
    DIRECTION OUTPUT ;
    USE SIGNAL ;
    SHAPE ABUTMENT ;
    PORT
      LAYER met2 ;
      RECT 2958.650 1558.140 2958.790 1558.560 ;
    END
  END r0_rd_out[494]
  PIN r0_rd_out[495]
    DIRECTION OUTPUT ;
    USE SIGNAL ;
    SHAPE ABUTMENT ;
    PORT
      LAYER met2 ;
      RECT 2971.070 1558.140 2971.210 1558.560 ;
    END
  END r0_rd_out[495]
  PIN r0_rd_out[496]
    DIRECTION OUTPUT ;
    USE SIGNAL ;
    SHAPE ABUTMENT ;
    PORT
      LAYER met2 ;
      RECT 2983.490 1558.140 2983.630 1558.560 ;
    END
  END r0_rd_out[496]
  PIN r0_rd_out[497]
    DIRECTION OUTPUT ;
    USE SIGNAL ;
    SHAPE ABUTMENT ;
    PORT
      LAYER met2 ;
      RECT 2995.910 1558.140 2996.050 1558.560 ;
    END
  END r0_rd_out[497]
  PIN r0_rd_out[498]
    DIRECTION OUTPUT ;
    USE SIGNAL ;
    SHAPE ABUTMENT ;
    PORT
      LAYER met2 ;
      RECT 3008.330 1558.140 3008.470 1558.560 ;
    END
  END r0_rd_out[498]
  PIN r0_rd_out[499]
    DIRECTION OUTPUT ;
    USE SIGNAL ;
    SHAPE ABUTMENT ;
    PORT
      LAYER met2 ;
      RECT 3020.750 1558.140 3020.890 1558.560 ;
    END
  END r0_rd_out[499]
  PIN r0_rd_out[500]
    DIRECTION OUTPUT ;
    USE SIGNAL ;
    SHAPE ABUTMENT ;
    PORT
      LAYER met2 ;
      RECT 3033.170 1558.140 3033.310 1558.560 ;
    END
  END r0_rd_out[500]
  PIN r0_rd_out[501]
    DIRECTION OUTPUT ;
    USE SIGNAL ;
    SHAPE ABUTMENT ;
    PORT
      LAYER met2 ;
      RECT 3045.590 1558.140 3045.730 1558.560 ;
    END
  END r0_rd_out[501]
  PIN r0_rd_out[502]
    DIRECTION OUTPUT ;
    USE SIGNAL ;
    SHAPE ABUTMENT ;
    PORT
      LAYER met2 ;
      RECT 3058.010 1558.140 3058.150 1558.560 ;
    END
  END r0_rd_out[502]
  PIN r0_rd_out[503]
    DIRECTION OUTPUT ;
    USE SIGNAL ;
    SHAPE ABUTMENT ;
    PORT
      LAYER met2 ;
      RECT 3070.430 1558.140 3070.570 1558.560 ;
    END
  END r0_rd_out[503]
  PIN r0_rd_out[504]
    DIRECTION OUTPUT ;
    USE SIGNAL ;
    SHAPE ABUTMENT ;
    PORT
      LAYER met2 ;
      RECT 3082.850 1558.140 3082.990 1558.560 ;
    END
  END r0_rd_out[504]
  PIN r0_rd_out[505]
    DIRECTION OUTPUT ;
    USE SIGNAL ;
    SHAPE ABUTMENT ;
    PORT
      LAYER met2 ;
      RECT 3095.270 1558.140 3095.410 1558.560 ;
    END
  END r0_rd_out[505]
  PIN r0_rd_out[506]
    DIRECTION OUTPUT ;
    USE SIGNAL ;
    SHAPE ABUTMENT ;
    PORT
      LAYER met2 ;
      RECT 3107.690 1558.140 3107.830 1558.560 ;
    END
  END r0_rd_out[506]
  PIN r0_rd_out[507]
    DIRECTION OUTPUT ;
    USE SIGNAL ;
    SHAPE ABUTMENT ;
    PORT
      LAYER met2 ;
      RECT 3120.110 1558.140 3120.250 1558.560 ;
    END
  END r0_rd_out[507]
  PIN r0_rd_out[508]
    DIRECTION OUTPUT ;
    USE SIGNAL ;
    SHAPE ABUTMENT ;
    PORT
      LAYER met2 ;
      RECT 3132.530 1558.140 3132.670 1558.560 ;
    END
  END r0_rd_out[508]
  PIN r0_rd_out[509]
    DIRECTION OUTPUT ;
    USE SIGNAL ;
    SHAPE ABUTMENT ;
    PORT
      LAYER met2 ;
      RECT 3144.950 1558.140 3145.090 1558.560 ;
    END
  END r0_rd_out[509]
  PIN r0_rd_out[510]
    DIRECTION OUTPUT ;
    USE SIGNAL ;
    SHAPE ABUTMENT ;
    PORT
      LAYER met2 ;
      RECT 3157.370 1558.140 3157.510 1558.560 ;
    END
  END r0_rd_out[510]
  PIN r0_rd_out[511]
    DIRECTION OUTPUT ;
    USE SIGNAL ;
    SHAPE ABUTMENT ;
    PORT
      LAYER met2 ;
      RECT 3169.790 1558.140 3169.930 1558.560 ;
    END
  END r0_rd_out[511]
  PIN w0_addr_in[0]
    DIRECTION INPUT ;
    USE SIGNAL ;
    SHAPE ABUTMENT ;
    PORT
      LAYER met3 ;
      RECT 0.000 1396.570 0.900 1396.870 ;
    END
  END w0_addr_in[0]
  PIN w0_addr_in[1]
    DIRECTION INPUT ;
    USE SIGNAL ;
    SHAPE ABUTMENT ;
    PORT
      LAYER met3 ;
      RECT 0.000 1407.450 0.900 1407.750 ;
    END
  END w0_addr_in[1]
  PIN w0_addr_in[2]
    DIRECTION INPUT ;
    USE SIGNAL ;
    SHAPE ABUTMENT ;
    PORT
      LAYER met3 ;
      RECT 0.000 1418.330 0.900 1418.630 ;
    END
  END w0_addr_in[2]
  PIN w0_addr_in[3]
    DIRECTION INPUT ;
    USE SIGNAL ;
    SHAPE ABUTMENT ;
    PORT
      LAYER met3 ;
      RECT 0.000 1429.210 0.900 1429.510 ;
    END
  END w0_addr_in[3]
  PIN w0_addr_in[4]
    DIRECTION INPUT ;
    USE SIGNAL ;
    SHAPE ABUTMENT ;
    PORT
      LAYER met3 ;
      RECT 0.000 1440.090 0.900 1440.390 ;
    END
  END w0_addr_in[4]
  PIN w0_addr_in[5]
    DIRECTION INPUT ;
    USE SIGNAL ;
    SHAPE ABUTMENT ;
    PORT
      LAYER met3 ;
      RECT 3260.500 1396.570 3261.400 1396.870 ;
    END
  END w0_addr_in[5]
  PIN w0_addr_in[6]
    DIRECTION INPUT ;
    USE SIGNAL ;
    SHAPE ABUTMENT ;
    PORT
      LAYER met3 ;
      RECT 3260.500 1407.450 3261.400 1407.750 ;
    END
  END w0_addr_in[6]
  PIN w0_addr_in[7]
    DIRECTION INPUT ;
    USE SIGNAL ;
    SHAPE ABUTMENT ;
    PORT
      LAYER met3 ;
      RECT 3260.500 1418.330 3261.400 1418.630 ;
    END
  END w0_addr_in[7]
  PIN w0_addr_in[8]
    DIRECTION INPUT ;
    USE SIGNAL ;
    SHAPE ABUTMENT ;
    PORT
      LAYER met3 ;
      RECT 3260.500 1429.210 3261.400 1429.510 ;
    END
  END w0_addr_in[8]
  PIN w0_addr_in[9]
    DIRECTION INPUT ;
    USE SIGNAL ;
    SHAPE ABUTMENT ;
    PORT
      LAYER met3 ;
      RECT 3260.500 1440.090 3261.400 1440.390 ;
    END
  END w0_addr_in[9]
  PIN r0_addr_in[0]
    DIRECTION INPUT ;
    USE SIGNAL ;
    SHAPE ABUTMENT ;
    PORT
      LAYER met3 ;
      RECT 0.000 1450.970 0.900 1451.270 ;
    END
  END r0_addr_in[0]
  PIN r0_addr_in[1]
    DIRECTION INPUT ;
    USE SIGNAL ;
    SHAPE ABUTMENT ;
    PORT
      LAYER met3 ;
      RECT 0.000 1461.850 0.900 1462.150 ;
    END
  END r0_addr_in[1]
  PIN r0_addr_in[2]
    DIRECTION INPUT ;
    USE SIGNAL ;
    SHAPE ABUTMENT ;
    PORT
      LAYER met3 ;
      RECT 0.000 1472.730 0.900 1473.030 ;
    END
  END r0_addr_in[2]
  PIN r0_addr_in[3]
    DIRECTION INPUT ;
    USE SIGNAL ;
    SHAPE ABUTMENT ;
    PORT
      LAYER met3 ;
      RECT 0.000 1483.610 0.900 1483.910 ;
    END
  END r0_addr_in[3]
  PIN r0_addr_in[4]
    DIRECTION INPUT ;
    USE SIGNAL ;
    SHAPE ABUTMENT ;
    PORT
      LAYER met3 ;
      RECT 0.000 1494.490 0.900 1494.790 ;
    END
  END r0_addr_in[4]
  PIN r0_addr_in[5]
    DIRECTION INPUT ;
    USE SIGNAL ;
    SHAPE ABUTMENT ;
    PORT
      LAYER met3 ;
      RECT 3260.500 1450.970 3261.400 1451.270 ;
    END
  END r0_addr_in[5]
  PIN r0_addr_in[6]
    DIRECTION INPUT ;
    USE SIGNAL ;
    SHAPE ABUTMENT ;
    PORT
      LAYER met3 ;
      RECT 3260.500 1461.850 3261.400 1462.150 ;
    END
  END r0_addr_in[6]
  PIN r0_addr_in[7]
    DIRECTION INPUT ;
    USE SIGNAL ;
    SHAPE ABUTMENT ;
    PORT
      LAYER met3 ;
      RECT 3260.500 1472.730 3261.400 1473.030 ;
    END
  END r0_addr_in[7]
  PIN r0_addr_in[8]
    DIRECTION INPUT ;
    USE SIGNAL ;
    SHAPE ABUTMENT ;
    PORT
      LAYER met3 ;
      RECT 3260.500 1483.610 3261.400 1483.910 ;
    END
  END r0_addr_in[8]
  PIN r0_addr_in[9]
    DIRECTION INPUT ;
    USE SIGNAL ;
    SHAPE ABUTMENT ;
    PORT
      LAYER met3 ;
      RECT 3260.500 1494.490 3261.400 1494.790 ;
    END
  END r0_addr_in[9]
  PIN w0_we_in
    DIRECTION INPUT ;
    USE SIGNAL ;
    SHAPE ABUTMENT ;
    PORT
      LAYER met2 ;
      RECT 3182.210 1558.140 3182.350 1558.560 ;
    END
  END w0_we_in
  PIN w0_ce_in
    DIRECTION INPUT ;
    USE SIGNAL ;
    SHAPE ABUTMENT ;
    PORT
      LAYER met2 ;
      RECT 3194.630 1558.140 3194.770 1558.560 ;
    END
  END w0_ce_in
  PIN w0_clk
    DIRECTION INPUT ;
    USE SIGNAL ;
    SHAPE ABUTMENT ;
    PORT
      LAYER met2 ;
      RECT 3207.050 1558.140 3207.190 1558.560 ;
    END
  END w0_clk
  PIN r0_ce_in
    DIRECTION INPUT ;
    USE SIGNAL ;
    SHAPE ABUTMENT ;
    PORT
      LAYER met2 ;
      RECT 3219.470 1558.140 3219.610 1558.560 ;
    END
  END r0_ce_in
  PIN r0_clk
    DIRECTION INPUT ;
    USE SIGNAL ;
    SHAPE ABUTMENT ;
    PORT
      LAYER met2 ;
      RECT 3231.890 1558.140 3232.030 1558.560 ;
    END
  END r0_clk
  PIN VSS
    DIRECTION INOUT ;
    USE GROUND ;
    PORT
      LAYER met4 ;
      RECT 2.160 4.080 3.360 1554.480 ;
      RECT 13.040 4.080 14.240 1554.480 ;
      RECT 23.920 4.080 25.120 1554.480 ;
      RECT 34.800 4.080 36.000 1554.480 ;
      RECT 45.680 4.080 46.880 1554.480 ;
      RECT 56.560 4.080 57.760 1554.480 ;
      RECT 67.440 4.080 68.640 1554.480 ;
      RECT 78.320 4.080 79.520 1554.480 ;
      RECT 89.200 4.080 90.400 1554.480 ;
      RECT 100.080 4.080 101.280 1554.480 ;
      RECT 110.960 4.080 112.160 1554.480 ;
      RECT 121.840 4.080 123.040 1554.480 ;
      RECT 132.720 4.080 133.920 1554.480 ;
      RECT 143.600 4.080 144.800 1554.480 ;
      RECT 154.480 4.080 155.680 1554.480 ;
      RECT 165.360 4.080 166.560 1554.480 ;
      RECT 176.240 4.080 177.440 1554.480 ;
      RECT 187.120 4.080 188.320 1554.480 ;
      RECT 198.000 4.080 199.200 1554.480 ;
      RECT 208.880 4.080 210.080 1554.480 ;
      RECT 219.760 4.080 220.960 1554.480 ;
      RECT 230.640 4.080 231.840 1554.480 ;
      RECT 241.520 4.080 242.720 1554.480 ;
      RECT 252.400 4.080 253.600 1554.480 ;
      RECT 263.280 4.080 264.480 1554.480 ;
      RECT 274.160 4.080 275.360 1554.480 ;
      RECT 285.040 4.080 286.240 1554.480 ;
      RECT 295.920 4.080 297.120 1554.480 ;
      RECT 306.800 4.080 308.000 1554.480 ;
      RECT 317.680 4.080 318.880 1554.480 ;
      RECT 328.560 4.080 329.760 1554.480 ;
      RECT 339.440 4.080 340.640 1554.480 ;
      RECT 350.320 4.080 351.520 1554.480 ;
      RECT 361.200 4.080 362.400 1554.480 ;
      RECT 372.080 4.080 373.280 1554.480 ;
      RECT 382.960 4.080 384.160 1554.480 ;
      RECT 393.840 4.080 395.040 1554.480 ;
      RECT 404.720 4.080 405.920 1554.480 ;
      RECT 415.600 4.080 416.800 1554.480 ;
      RECT 426.480 4.080 427.680 1554.480 ;
      RECT 437.360 4.080 438.560 1554.480 ;
      RECT 448.240 4.080 449.440 1554.480 ;
      RECT 459.120 4.080 460.320 1554.480 ;
      RECT 470.000 4.080 471.200 1554.480 ;
      RECT 480.880 4.080 482.080 1554.480 ;
      RECT 491.760 4.080 492.960 1554.480 ;
      RECT 502.640 4.080 503.840 1554.480 ;
      RECT 513.520 4.080 514.720 1554.480 ;
      RECT 524.400 4.080 525.600 1554.480 ;
      RECT 535.280 4.080 536.480 1554.480 ;
      RECT 546.160 4.080 547.360 1554.480 ;
      RECT 557.040 4.080 558.240 1554.480 ;
      RECT 567.920 4.080 569.120 1554.480 ;
      RECT 578.800 4.080 580.000 1554.480 ;
      RECT 589.680 4.080 590.880 1554.480 ;
      RECT 600.560 4.080 601.760 1554.480 ;
      RECT 611.440 4.080 612.640 1554.480 ;
      RECT 622.320 4.080 623.520 1554.480 ;
      RECT 633.200 4.080 634.400 1554.480 ;
      RECT 644.080 4.080 645.280 1554.480 ;
      RECT 654.960 4.080 656.160 1554.480 ;
      RECT 665.840 4.080 667.040 1554.480 ;
      RECT 676.720 4.080 677.920 1554.480 ;
      RECT 687.600 4.080 688.800 1554.480 ;
      RECT 698.480 4.080 699.680 1554.480 ;
      RECT 709.360 4.080 710.560 1554.480 ;
      RECT 720.240 4.080 721.440 1554.480 ;
      RECT 731.120 4.080 732.320 1554.480 ;
      RECT 742.000 4.080 743.200 1554.480 ;
      RECT 752.880 4.080 754.080 1554.480 ;
      RECT 763.760 4.080 764.960 1554.480 ;
      RECT 774.640 4.080 775.840 1554.480 ;
      RECT 785.520 4.080 786.720 1554.480 ;
      RECT 796.400 4.080 797.600 1554.480 ;
      RECT 807.280 4.080 808.480 1554.480 ;
      RECT 818.160 4.080 819.360 1554.480 ;
      RECT 829.040 4.080 830.240 1554.480 ;
      RECT 839.920 4.080 841.120 1554.480 ;
      RECT 850.800 4.080 852.000 1554.480 ;
      RECT 861.680 4.080 862.880 1554.480 ;
      RECT 872.560 4.080 873.760 1554.480 ;
      RECT 883.440 4.080 884.640 1554.480 ;
      RECT 894.320 4.080 895.520 1554.480 ;
      RECT 905.200 4.080 906.400 1554.480 ;
      RECT 916.080 4.080 917.280 1554.480 ;
      RECT 926.960 4.080 928.160 1554.480 ;
      RECT 937.840 4.080 939.040 1554.480 ;
      RECT 948.720 4.080 949.920 1554.480 ;
      RECT 959.600 4.080 960.800 1554.480 ;
      RECT 970.480 4.080 971.680 1554.480 ;
      RECT 981.360 4.080 982.560 1554.480 ;
      RECT 992.240 4.080 993.440 1554.480 ;
      RECT 1003.120 4.080 1004.320 1554.480 ;
      RECT 1014.000 4.080 1015.200 1554.480 ;
      RECT 1024.880 4.080 1026.080 1554.480 ;
      RECT 1035.760 4.080 1036.960 1554.480 ;
      RECT 1046.640 4.080 1047.840 1554.480 ;
      RECT 1057.520 4.080 1058.720 1554.480 ;
      RECT 1068.400 4.080 1069.600 1554.480 ;
      RECT 1079.280 4.080 1080.480 1554.480 ;
      RECT 1090.160 4.080 1091.360 1554.480 ;
      RECT 1101.040 4.080 1102.240 1554.480 ;
      RECT 1111.920 4.080 1113.120 1554.480 ;
      RECT 1122.800 4.080 1124.000 1554.480 ;
      RECT 1133.680 4.080 1134.880 1554.480 ;
      RECT 1144.560 4.080 1145.760 1554.480 ;
      RECT 1155.440 4.080 1156.640 1554.480 ;
      RECT 1166.320 4.080 1167.520 1554.480 ;
      RECT 1177.200 4.080 1178.400 1554.480 ;
      RECT 1188.080 4.080 1189.280 1554.480 ;
      RECT 1198.960 4.080 1200.160 1554.480 ;
      RECT 1209.840 4.080 1211.040 1554.480 ;
      RECT 1220.720 4.080 1221.920 1554.480 ;
      RECT 1231.600 4.080 1232.800 1554.480 ;
      RECT 1242.480 4.080 1243.680 1554.480 ;
      RECT 1253.360 4.080 1254.560 1554.480 ;
      RECT 1264.240 4.080 1265.440 1554.480 ;
      RECT 1275.120 4.080 1276.320 1554.480 ;
      RECT 1286.000 4.080 1287.200 1554.480 ;
      RECT 1296.880 4.080 1298.080 1554.480 ;
      RECT 1307.760 4.080 1308.960 1554.480 ;
      RECT 1318.640 4.080 1319.840 1554.480 ;
      RECT 1329.520 4.080 1330.720 1554.480 ;
      RECT 1340.400 4.080 1341.600 1554.480 ;
      RECT 1351.280 4.080 1352.480 1554.480 ;
      RECT 1362.160 4.080 1363.360 1554.480 ;
      RECT 1373.040 4.080 1374.240 1554.480 ;
      RECT 1383.920 4.080 1385.120 1554.480 ;
      RECT 1394.800 4.080 1396.000 1554.480 ;
      RECT 1405.680 4.080 1406.880 1554.480 ;
      RECT 1416.560 4.080 1417.760 1554.480 ;
      RECT 1427.440 4.080 1428.640 1554.480 ;
      RECT 1438.320 4.080 1439.520 1554.480 ;
      RECT 1449.200 4.080 1450.400 1554.480 ;
      RECT 1460.080 4.080 1461.280 1554.480 ;
      RECT 1470.960 4.080 1472.160 1554.480 ;
      RECT 1481.840 4.080 1483.040 1554.480 ;
      RECT 1492.720 4.080 1493.920 1554.480 ;
      RECT 1503.600 4.080 1504.800 1554.480 ;
      RECT 1514.480 4.080 1515.680 1554.480 ;
      RECT 1525.360 4.080 1526.560 1554.480 ;
      RECT 1536.240 4.080 1537.440 1554.480 ;
      RECT 1547.120 4.080 1548.320 1554.480 ;
      RECT 1558.000 4.080 1559.200 1554.480 ;
      RECT 1568.880 4.080 1570.080 1554.480 ;
      RECT 1579.760 4.080 1580.960 1554.480 ;
      RECT 1590.640 4.080 1591.840 1554.480 ;
      RECT 1601.520 4.080 1602.720 1554.480 ;
      RECT 1612.400 4.080 1613.600 1554.480 ;
      RECT 1623.280 4.080 1624.480 1554.480 ;
      RECT 1634.160 4.080 1635.360 1554.480 ;
      RECT 1645.040 4.080 1646.240 1554.480 ;
      RECT 1655.920 4.080 1657.120 1554.480 ;
      RECT 1666.800 4.080 1668.000 1554.480 ;
      RECT 1677.680 4.080 1678.880 1554.480 ;
      RECT 1688.560 4.080 1689.760 1554.480 ;
      RECT 1699.440 4.080 1700.640 1554.480 ;
      RECT 1710.320 4.080 1711.520 1554.480 ;
      RECT 1721.200 4.080 1722.400 1554.480 ;
      RECT 1732.080 4.080 1733.280 1554.480 ;
      RECT 1742.960 4.080 1744.160 1554.480 ;
      RECT 1753.840 4.080 1755.040 1554.480 ;
      RECT 1764.720 4.080 1765.920 1554.480 ;
      RECT 1775.600 4.080 1776.800 1554.480 ;
      RECT 1786.480 4.080 1787.680 1554.480 ;
      RECT 1797.360 4.080 1798.560 1554.480 ;
      RECT 1808.240 4.080 1809.440 1554.480 ;
      RECT 1819.120 4.080 1820.320 1554.480 ;
      RECT 1830.000 4.080 1831.200 1554.480 ;
      RECT 1840.880 4.080 1842.080 1554.480 ;
      RECT 1851.760 4.080 1852.960 1554.480 ;
      RECT 1862.640 4.080 1863.840 1554.480 ;
      RECT 1873.520 4.080 1874.720 1554.480 ;
      RECT 1884.400 4.080 1885.600 1554.480 ;
      RECT 1895.280 4.080 1896.480 1554.480 ;
      RECT 1906.160 4.080 1907.360 1554.480 ;
      RECT 1917.040 4.080 1918.240 1554.480 ;
      RECT 1927.920 4.080 1929.120 1554.480 ;
      RECT 1938.800 4.080 1940.000 1554.480 ;
      RECT 1949.680 4.080 1950.880 1554.480 ;
      RECT 1960.560 4.080 1961.760 1554.480 ;
      RECT 1971.440 4.080 1972.640 1554.480 ;
      RECT 1982.320 4.080 1983.520 1554.480 ;
      RECT 1993.200 4.080 1994.400 1554.480 ;
      RECT 2004.080 4.080 2005.280 1554.480 ;
      RECT 2014.960 4.080 2016.160 1554.480 ;
      RECT 2025.840 4.080 2027.040 1554.480 ;
      RECT 2036.720 4.080 2037.920 1554.480 ;
      RECT 2047.600 4.080 2048.800 1554.480 ;
      RECT 2058.480 4.080 2059.680 1554.480 ;
      RECT 2069.360 4.080 2070.560 1554.480 ;
      RECT 2080.240 4.080 2081.440 1554.480 ;
      RECT 2091.120 4.080 2092.320 1554.480 ;
      RECT 2102.000 4.080 2103.200 1554.480 ;
      RECT 2112.880 4.080 2114.080 1554.480 ;
      RECT 2123.760 4.080 2124.960 1554.480 ;
      RECT 2134.640 4.080 2135.840 1554.480 ;
      RECT 2145.520 4.080 2146.720 1554.480 ;
      RECT 2156.400 4.080 2157.600 1554.480 ;
      RECT 2167.280 4.080 2168.480 1554.480 ;
      RECT 2178.160 4.080 2179.360 1554.480 ;
      RECT 2189.040 4.080 2190.240 1554.480 ;
      RECT 2199.920 4.080 2201.120 1554.480 ;
      RECT 2210.800 4.080 2212.000 1554.480 ;
      RECT 2221.680 4.080 2222.880 1554.480 ;
      RECT 2232.560 4.080 2233.760 1554.480 ;
      RECT 2243.440 4.080 2244.640 1554.480 ;
      RECT 2254.320 4.080 2255.520 1554.480 ;
      RECT 2265.200 4.080 2266.400 1554.480 ;
      RECT 2276.080 4.080 2277.280 1554.480 ;
      RECT 2286.960 4.080 2288.160 1554.480 ;
      RECT 2297.840 4.080 2299.040 1554.480 ;
      RECT 2308.720 4.080 2309.920 1554.480 ;
      RECT 2319.600 4.080 2320.800 1554.480 ;
      RECT 2330.480 4.080 2331.680 1554.480 ;
      RECT 2341.360 4.080 2342.560 1554.480 ;
      RECT 2352.240 4.080 2353.440 1554.480 ;
      RECT 2363.120 4.080 2364.320 1554.480 ;
      RECT 2374.000 4.080 2375.200 1554.480 ;
      RECT 2384.880 4.080 2386.080 1554.480 ;
      RECT 2395.760 4.080 2396.960 1554.480 ;
      RECT 2406.640 4.080 2407.840 1554.480 ;
      RECT 2417.520 4.080 2418.720 1554.480 ;
      RECT 2428.400 4.080 2429.600 1554.480 ;
      RECT 2439.280 4.080 2440.480 1554.480 ;
      RECT 2450.160 4.080 2451.360 1554.480 ;
      RECT 2461.040 4.080 2462.240 1554.480 ;
      RECT 2471.920 4.080 2473.120 1554.480 ;
      RECT 2482.800 4.080 2484.000 1554.480 ;
      RECT 2493.680 4.080 2494.880 1554.480 ;
      RECT 2504.560 4.080 2505.760 1554.480 ;
      RECT 2515.440 4.080 2516.640 1554.480 ;
      RECT 2526.320 4.080 2527.520 1554.480 ;
      RECT 2537.200 4.080 2538.400 1554.480 ;
      RECT 2548.080 4.080 2549.280 1554.480 ;
      RECT 2558.960 4.080 2560.160 1554.480 ;
      RECT 2569.840 4.080 2571.040 1554.480 ;
      RECT 2580.720 4.080 2581.920 1554.480 ;
      RECT 2591.600 4.080 2592.800 1554.480 ;
      RECT 2602.480 4.080 2603.680 1554.480 ;
      RECT 2613.360 4.080 2614.560 1554.480 ;
      RECT 2624.240 4.080 2625.440 1554.480 ;
      RECT 2635.120 4.080 2636.320 1554.480 ;
      RECT 2646.000 4.080 2647.200 1554.480 ;
      RECT 2656.880 4.080 2658.080 1554.480 ;
      RECT 2667.760 4.080 2668.960 1554.480 ;
      RECT 2678.640 4.080 2679.840 1554.480 ;
      RECT 2689.520 4.080 2690.720 1554.480 ;
      RECT 2700.400 4.080 2701.600 1554.480 ;
      RECT 2711.280 4.080 2712.480 1554.480 ;
      RECT 2722.160 4.080 2723.360 1554.480 ;
      RECT 2733.040 4.080 2734.240 1554.480 ;
      RECT 2743.920 4.080 2745.120 1554.480 ;
      RECT 2754.800 4.080 2756.000 1554.480 ;
      RECT 2765.680 4.080 2766.880 1554.480 ;
      RECT 2776.560 4.080 2777.760 1554.480 ;
      RECT 2787.440 4.080 2788.640 1554.480 ;
      RECT 2798.320 4.080 2799.520 1554.480 ;
      RECT 2809.200 4.080 2810.400 1554.480 ;
      RECT 2820.080 4.080 2821.280 1554.480 ;
      RECT 2830.960 4.080 2832.160 1554.480 ;
      RECT 2841.840 4.080 2843.040 1554.480 ;
      RECT 2852.720 4.080 2853.920 1554.480 ;
      RECT 2863.600 4.080 2864.800 1554.480 ;
      RECT 2874.480 4.080 2875.680 1554.480 ;
      RECT 2885.360 4.080 2886.560 1554.480 ;
      RECT 2896.240 4.080 2897.440 1554.480 ;
      RECT 2907.120 4.080 2908.320 1554.480 ;
      RECT 2918.000 4.080 2919.200 1554.480 ;
      RECT 2928.880 4.080 2930.080 1554.480 ;
      RECT 2939.760 4.080 2940.960 1554.480 ;
      RECT 2950.640 4.080 2951.840 1554.480 ;
      RECT 2961.520 4.080 2962.720 1554.480 ;
      RECT 2972.400 4.080 2973.600 1554.480 ;
      RECT 2983.280 4.080 2984.480 1554.480 ;
      RECT 2994.160 4.080 2995.360 1554.480 ;
      RECT 3005.040 4.080 3006.240 1554.480 ;
      RECT 3015.920 4.080 3017.120 1554.480 ;
      RECT 3026.800 4.080 3028.000 1554.480 ;
      RECT 3037.680 4.080 3038.880 1554.480 ;
      RECT 3048.560 4.080 3049.760 1554.480 ;
      RECT 3059.440 4.080 3060.640 1554.480 ;
      RECT 3070.320 4.080 3071.520 1554.480 ;
      RECT 3081.200 4.080 3082.400 1554.480 ;
      RECT 3092.080 4.080 3093.280 1554.480 ;
      RECT 3102.960 4.080 3104.160 1554.480 ;
      RECT 3113.840 4.080 3115.040 1554.480 ;
      RECT 3124.720 4.080 3125.920 1554.480 ;
      RECT 3135.600 4.080 3136.800 1554.480 ;
      RECT 3146.480 4.080 3147.680 1554.480 ;
      RECT 3157.360 4.080 3158.560 1554.480 ;
      RECT 3168.240 4.080 3169.440 1554.480 ;
      RECT 3179.120 4.080 3180.320 1554.480 ;
      RECT 3190.000 4.080 3191.200 1554.480 ;
      RECT 3200.880 4.080 3202.080 1554.480 ;
      RECT 3211.760 4.080 3212.960 1554.480 ;
      RECT 3222.640 4.080 3223.840 1554.480 ;
      RECT 3233.520 4.080 3234.720 1554.480 ;
      RECT 3244.400 4.080 3245.600 1554.480 ;
      RECT 3255.280 4.080 3256.480 1554.480 ;
    END
  END VSS
  PIN VDD
    DIRECTION INOUT ;
    USE POWER ;
    PORT
      LAYER met4 ;
      RECT 2.160 4.080 3.360 1554.480 ;
      RECT 13.040 4.080 14.240 1554.480 ;
      RECT 23.920 4.080 25.120 1554.480 ;
      RECT 34.800 4.080 36.000 1554.480 ;
      RECT 45.680 4.080 46.880 1554.480 ;
      RECT 56.560 4.080 57.760 1554.480 ;
      RECT 67.440 4.080 68.640 1554.480 ;
      RECT 78.320 4.080 79.520 1554.480 ;
      RECT 89.200 4.080 90.400 1554.480 ;
      RECT 100.080 4.080 101.280 1554.480 ;
      RECT 110.960 4.080 112.160 1554.480 ;
      RECT 121.840 4.080 123.040 1554.480 ;
      RECT 132.720 4.080 133.920 1554.480 ;
      RECT 143.600 4.080 144.800 1554.480 ;
      RECT 154.480 4.080 155.680 1554.480 ;
      RECT 165.360 4.080 166.560 1554.480 ;
      RECT 176.240 4.080 177.440 1554.480 ;
      RECT 187.120 4.080 188.320 1554.480 ;
      RECT 198.000 4.080 199.200 1554.480 ;
      RECT 208.880 4.080 210.080 1554.480 ;
      RECT 219.760 4.080 220.960 1554.480 ;
      RECT 230.640 4.080 231.840 1554.480 ;
      RECT 241.520 4.080 242.720 1554.480 ;
      RECT 252.400 4.080 253.600 1554.480 ;
      RECT 263.280 4.080 264.480 1554.480 ;
      RECT 274.160 4.080 275.360 1554.480 ;
      RECT 285.040 4.080 286.240 1554.480 ;
      RECT 295.920 4.080 297.120 1554.480 ;
      RECT 306.800 4.080 308.000 1554.480 ;
      RECT 317.680 4.080 318.880 1554.480 ;
      RECT 328.560 4.080 329.760 1554.480 ;
      RECT 339.440 4.080 340.640 1554.480 ;
      RECT 350.320 4.080 351.520 1554.480 ;
      RECT 361.200 4.080 362.400 1554.480 ;
      RECT 372.080 4.080 373.280 1554.480 ;
      RECT 382.960 4.080 384.160 1554.480 ;
      RECT 393.840 4.080 395.040 1554.480 ;
      RECT 404.720 4.080 405.920 1554.480 ;
      RECT 415.600 4.080 416.800 1554.480 ;
      RECT 426.480 4.080 427.680 1554.480 ;
      RECT 437.360 4.080 438.560 1554.480 ;
      RECT 448.240 4.080 449.440 1554.480 ;
      RECT 459.120 4.080 460.320 1554.480 ;
      RECT 470.000 4.080 471.200 1554.480 ;
      RECT 480.880 4.080 482.080 1554.480 ;
      RECT 491.760 4.080 492.960 1554.480 ;
      RECT 502.640 4.080 503.840 1554.480 ;
      RECT 513.520 4.080 514.720 1554.480 ;
      RECT 524.400 4.080 525.600 1554.480 ;
      RECT 535.280 4.080 536.480 1554.480 ;
      RECT 546.160 4.080 547.360 1554.480 ;
      RECT 557.040 4.080 558.240 1554.480 ;
      RECT 567.920 4.080 569.120 1554.480 ;
      RECT 578.800 4.080 580.000 1554.480 ;
      RECT 589.680 4.080 590.880 1554.480 ;
      RECT 600.560 4.080 601.760 1554.480 ;
      RECT 611.440 4.080 612.640 1554.480 ;
      RECT 622.320 4.080 623.520 1554.480 ;
      RECT 633.200 4.080 634.400 1554.480 ;
      RECT 644.080 4.080 645.280 1554.480 ;
      RECT 654.960 4.080 656.160 1554.480 ;
      RECT 665.840 4.080 667.040 1554.480 ;
      RECT 676.720 4.080 677.920 1554.480 ;
      RECT 687.600 4.080 688.800 1554.480 ;
      RECT 698.480 4.080 699.680 1554.480 ;
      RECT 709.360 4.080 710.560 1554.480 ;
      RECT 720.240 4.080 721.440 1554.480 ;
      RECT 731.120 4.080 732.320 1554.480 ;
      RECT 742.000 4.080 743.200 1554.480 ;
      RECT 752.880 4.080 754.080 1554.480 ;
      RECT 763.760 4.080 764.960 1554.480 ;
      RECT 774.640 4.080 775.840 1554.480 ;
      RECT 785.520 4.080 786.720 1554.480 ;
      RECT 796.400 4.080 797.600 1554.480 ;
      RECT 807.280 4.080 808.480 1554.480 ;
      RECT 818.160 4.080 819.360 1554.480 ;
      RECT 829.040 4.080 830.240 1554.480 ;
      RECT 839.920 4.080 841.120 1554.480 ;
      RECT 850.800 4.080 852.000 1554.480 ;
      RECT 861.680 4.080 862.880 1554.480 ;
      RECT 872.560 4.080 873.760 1554.480 ;
      RECT 883.440 4.080 884.640 1554.480 ;
      RECT 894.320 4.080 895.520 1554.480 ;
      RECT 905.200 4.080 906.400 1554.480 ;
      RECT 916.080 4.080 917.280 1554.480 ;
      RECT 926.960 4.080 928.160 1554.480 ;
      RECT 937.840 4.080 939.040 1554.480 ;
      RECT 948.720 4.080 949.920 1554.480 ;
      RECT 959.600 4.080 960.800 1554.480 ;
      RECT 970.480 4.080 971.680 1554.480 ;
      RECT 981.360 4.080 982.560 1554.480 ;
      RECT 992.240 4.080 993.440 1554.480 ;
      RECT 1003.120 4.080 1004.320 1554.480 ;
      RECT 1014.000 4.080 1015.200 1554.480 ;
      RECT 1024.880 4.080 1026.080 1554.480 ;
      RECT 1035.760 4.080 1036.960 1554.480 ;
      RECT 1046.640 4.080 1047.840 1554.480 ;
      RECT 1057.520 4.080 1058.720 1554.480 ;
      RECT 1068.400 4.080 1069.600 1554.480 ;
      RECT 1079.280 4.080 1080.480 1554.480 ;
      RECT 1090.160 4.080 1091.360 1554.480 ;
      RECT 1101.040 4.080 1102.240 1554.480 ;
      RECT 1111.920 4.080 1113.120 1554.480 ;
      RECT 1122.800 4.080 1124.000 1554.480 ;
      RECT 1133.680 4.080 1134.880 1554.480 ;
      RECT 1144.560 4.080 1145.760 1554.480 ;
      RECT 1155.440 4.080 1156.640 1554.480 ;
      RECT 1166.320 4.080 1167.520 1554.480 ;
      RECT 1177.200 4.080 1178.400 1554.480 ;
      RECT 1188.080 4.080 1189.280 1554.480 ;
      RECT 1198.960 4.080 1200.160 1554.480 ;
      RECT 1209.840 4.080 1211.040 1554.480 ;
      RECT 1220.720 4.080 1221.920 1554.480 ;
      RECT 1231.600 4.080 1232.800 1554.480 ;
      RECT 1242.480 4.080 1243.680 1554.480 ;
      RECT 1253.360 4.080 1254.560 1554.480 ;
      RECT 1264.240 4.080 1265.440 1554.480 ;
      RECT 1275.120 4.080 1276.320 1554.480 ;
      RECT 1286.000 4.080 1287.200 1554.480 ;
      RECT 1296.880 4.080 1298.080 1554.480 ;
      RECT 1307.760 4.080 1308.960 1554.480 ;
      RECT 1318.640 4.080 1319.840 1554.480 ;
      RECT 1329.520 4.080 1330.720 1554.480 ;
      RECT 1340.400 4.080 1341.600 1554.480 ;
      RECT 1351.280 4.080 1352.480 1554.480 ;
      RECT 1362.160 4.080 1363.360 1554.480 ;
      RECT 1373.040 4.080 1374.240 1554.480 ;
      RECT 1383.920 4.080 1385.120 1554.480 ;
      RECT 1394.800 4.080 1396.000 1554.480 ;
      RECT 1405.680 4.080 1406.880 1554.480 ;
      RECT 1416.560 4.080 1417.760 1554.480 ;
      RECT 1427.440 4.080 1428.640 1554.480 ;
      RECT 1438.320 4.080 1439.520 1554.480 ;
      RECT 1449.200 4.080 1450.400 1554.480 ;
      RECT 1460.080 4.080 1461.280 1554.480 ;
      RECT 1470.960 4.080 1472.160 1554.480 ;
      RECT 1481.840 4.080 1483.040 1554.480 ;
      RECT 1492.720 4.080 1493.920 1554.480 ;
      RECT 1503.600 4.080 1504.800 1554.480 ;
      RECT 1514.480 4.080 1515.680 1554.480 ;
      RECT 1525.360 4.080 1526.560 1554.480 ;
      RECT 1536.240 4.080 1537.440 1554.480 ;
      RECT 1547.120 4.080 1548.320 1554.480 ;
      RECT 1558.000 4.080 1559.200 1554.480 ;
      RECT 1568.880 4.080 1570.080 1554.480 ;
      RECT 1579.760 4.080 1580.960 1554.480 ;
      RECT 1590.640 4.080 1591.840 1554.480 ;
      RECT 1601.520 4.080 1602.720 1554.480 ;
      RECT 1612.400 4.080 1613.600 1554.480 ;
      RECT 1623.280 4.080 1624.480 1554.480 ;
      RECT 1634.160 4.080 1635.360 1554.480 ;
      RECT 1645.040 4.080 1646.240 1554.480 ;
      RECT 1655.920 4.080 1657.120 1554.480 ;
      RECT 1666.800 4.080 1668.000 1554.480 ;
      RECT 1677.680 4.080 1678.880 1554.480 ;
      RECT 1688.560 4.080 1689.760 1554.480 ;
      RECT 1699.440 4.080 1700.640 1554.480 ;
      RECT 1710.320 4.080 1711.520 1554.480 ;
      RECT 1721.200 4.080 1722.400 1554.480 ;
      RECT 1732.080 4.080 1733.280 1554.480 ;
      RECT 1742.960 4.080 1744.160 1554.480 ;
      RECT 1753.840 4.080 1755.040 1554.480 ;
      RECT 1764.720 4.080 1765.920 1554.480 ;
      RECT 1775.600 4.080 1776.800 1554.480 ;
      RECT 1786.480 4.080 1787.680 1554.480 ;
      RECT 1797.360 4.080 1798.560 1554.480 ;
      RECT 1808.240 4.080 1809.440 1554.480 ;
      RECT 1819.120 4.080 1820.320 1554.480 ;
      RECT 1830.000 4.080 1831.200 1554.480 ;
      RECT 1840.880 4.080 1842.080 1554.480 ;
      RECT 1851.760 4.080 1852.960 1554.480 ;
      RECT 1862.640 4.080 1863.840 1554.480 ;
      RECT 1873.520 4.080 1874.720 1554.480 ;
      RECT 1884.400 4.080 1885.600 1554.480 ;
      RECT 1895.280 4.080 1896.480 1554.480 ;
      RECT 1906.160 4.080 1907.360 1554.480 ;
      RECT 1917.040 4.080 1918.240 1554.480 ;
      RECT 1927.920 4.080 1929.120 1554.480 ;
      RECT 1938.800 4.080 1940.000 1554.480 ;
      RECT 1949.680 4.080 1950.880 1554.480 ;
      RECT 1960.560 4.080 1961.760 1554.480 ;
      RECT 1971.440 4.080 1972.640 1554.480 ;
      RECT 1982.320 4.080 1983.520 1554.480 ;
      RECT 1993.200 4.080 1994.400 1554.480 ;
      RECT 2004.080 4.080 2005.280 1554.480 ;
      RECT 2014.960 4.080 2016.160 1554.480 ;
      RECT 2025.840 4.080 2027.040 1554.480 ;
      RECT 2036.720 4.080 2037.920 1554.480 ;
      RECT 2047.600 4.080 2048.800 1554.480 ;
      RECT 2058.480 4.080 2059.680 1554.480 ;
      RECT 2069.360 4.080 2070.560 1554.480 ;
      RECT 2080.240 4.080 2081.440 1554.480 ;
      RECT 2091.120 4.080 2092.320 1554.480 ;
      RECT 2102.000 4.080 2103.200 1554.480 ;
      RECT 2112.880 4.080 2114.080 1554.480 ;
      RECT 2123.760 4.080 2124.960 1554.480 ;
      RECT 2134.640 4.080 2135.840 1554.480 ;
      RECT 2145.520 4.080 2146.720 1554.480 ;
      RECT 2156.400 4.080 2157.600 1554.480 ;
      RECT 2167.280 4.080 2168.480 1554.480 ;
      RECT 2178.160 4.080 2179.360 1554.480 ;
      RECT 2189.040 4.080 2190.240 1554.480 ;
      RECT 2199.920 4.080 2201.120 1554.480 ;
      RECT 2210.800 4.080 2212.000 1554.480 ;
      RECT 2221.680 4.080 2222.880 1554.480 ;
      RECT 2232.560 4.080 2233.760 1554.480 ;
      RECT 2243.440 4.080 2244.640 1554.480 ;
      RECT 2254.320 4.080 2255.520 1554.480 ;
      RECT 2265.200 4.080 2266.400 1554.480 ;
      RECT 2276.080 4.080 2277.280 1554.480 ;
      RECT 2286.960 4.080 2288.160 1554.480 ;
      RECT 2297.840 4.080 2299.040 1554.480 ;
      RECT 2308.720 4.080 2309.920 1554.480 ;
      RECT 2319.600 4.080 2320.800 1554.480 ;
      RECT 2330.480 4.080 2331.680 1554.480 ;
      RECT 2341.360 4.080 2342.560 1554.480 ;
      RECT 2352.240 4.080 2353.440 1554.480 ;
      RECT 2363.120 4.080 2364.320 1554.480 ;
      RECT 2374.000 4.080 2375.200 1554.480 ;
      RECT 2384.880 4.080 2386.080 1554.480 ;
      RECT 2395.760 4.080 2396.960 1554.480 ;
      RECT 2406.640 4.080 2407.840 1554.480 ;
      RECT 2417.520 4.080 2418.720 1554.480 ;
      RECT 2428.400 4.080 2429.600 1554.480 ;
      RECT 2439.280 4.080 2440.480 1554.480 ;
      RECT 2450.160 4.080 2451.360 1554.480 ;
      RECT 2461.040 4.080 2462.240 1554.480 ;
      RECT 2471.920 4.080 2473.120 1554.480 ;
      RECT 2482.800 4.080 2484.000 1554.480 ;
      RECT 2493.680 4.080 2494.880 1554.480 ;
      RECT 2504.560 4.080 2505.760 1554.480 ;
      RECT 2515.440 4.080 2516.640 1554.480 ;
      RECT 2526.320 4.080 2527.520 1554.480 ;
      RECT 2537.200 4.080 2538.400 1554.480 ;
      RECT 2548.080 4.080 2549.280 1554.480 ;
      RECT 2558.960 4.080 2560.160 1554.480 ;
      RECT 2569.840 4.080 2571.040 1554.480 ;
      RECT 2580.720 4.080 2581.920 1554.480 ;
      RECT 2591.600 4.080 2592.800 1554.480 ;
      RECT 2602.480 4.080 2603.680 1554.480 ;
      RECT 2613.360 4.080 2614.560 1554.480 ;
      RECT 2624.240 4.080 2625.440 1554.480 ;
      RECT 2635.120 4.080 2636.320 1554.480 ;
      RECT 2646.000 4.080 2647.200 1554.480 ;
      RECT 2656.880 4.080 2658.080 1554.480 ;
      RECT 2667.760 4.080 2668.960 1554.480 ;
      RECT 2678.640 4.080 2679.840 1554.480 ;
      RECT 2689.520 4.080 2690.720 1554.480 ;
      RECT 2700.400 4.080 2701.600 1554.480 ;
      RECT 2711.280 4.080 2712.480 1554.480 ;
      RECT 2722.160 4.080 2723.360 1554.480 ;
      RECT 2733.040 4.080 2734.240 1554.480 ;
      RECT 2743.920 4.080 2745.120 1554.480 ;
      RECT 2754.800 4.080 2756.000 1554.480 ;
      RECT 2765.680 4.080 2766.880 1554.480 ;
      RECT 2776.560 4.080 2777.760 1554.480 ;
      RECT 2787.440 4.080 2788.640 1554.480 ;
      RECT 2798.320 4.080 2799.520 1554.480 ;
      RECT 2809.200 4.080 2810.400 1554.480 ;
      RECT 2820.080 4.080 2821.280 1554.480 ;
      RECT 2830.960 4.080 2832.160 1554.480 ;
      RECT 2841.840 4.080 2843.040 1554.480 ;
      RECT 2852.720 4.080 2853.920 1554.480 ;
      RECT 2863.600 4.080 2864.800 1554.480 ;
      RECT 2874.480 4.080 2875.680 1554.480 ;
      RECT 2885.360 4.080 2886.560 1554.480 ;
      RECT 2896.240 4.080 2897.440 1554.480 ;
      RECT 2907.120 4.080 2908.320 1554.480 ;
      RECT 2918.000 4.080 2919.200 1554.480 ;
      RECT 2928.880 4.080 2930.080 1554.480 ;
      RECT 2939.760 4.080 2940.960 1554.480 ;
      RECT 2950.640 4.080 2951.840 1554.480 ;
      RECT 2961.520 4.080 2962.720 1554.480 ;
      RECT 2972.400 4.080 2973.600 1554.480 ;
      RECT 2983.280 4.080 2984.480 1554.480 ;
      RECT 2994.160 4.080 2995.360 1554.480 ;
      RECT 3005.040 4.080 3006.240 1554.480 ;
      RECT 3015.920 4.080 3017.120 1554.480 ;
      RECT 3026.800 4.080 3028.000 1554.480 ;
      RECT 3037.680 4.080 3038.880 1554.480 ;
      RECT 3048.560 4.080 3049.760 1554.480 ;
      RECT 3059.440 4.080 3060.640 1554.480 ;
      RECT 3070.320 4.080 3071.520 1554.480 ;
      RECT 3081.200 4.080 3082.400 1554.480 ;
      RECT 3092.080 4.080 3093.280 1554.480 ;
      RECT 3102.960 4.080 3104.160 1554.480 ;
      RECT 3113.840 4.080 3115.040 1554.480 ;
      RECT 3124.720 4.080 3125.920 1554.480 ;
      RECT 3135.600 4.080 3136.800 1554.480 ;
      RECT 3146.480 4.080 3147.680 1554.480 ;
      RECT 3157.360 4.080 3158.560 1554.480 ;
      RECT 3168.240 4.080 3169.440 1554.480 ;
      RECT 3179.120 4.080 3180.320 1554.480 ;
      RECT 3190.000 4.080 3191.200 1554.480 ;
      RECT 3200.880 4.080 3202.080 1554.480 ;
      RECT 3211.760 4.080 3212.960 1554.480 ;
      RECT 3222.640 4.080 3223.840 1554.480 ;
      RECT 3233.520 4.080 3234.720 1554.480 ;
      RECT 3244.400 4.080 3245.600 1554.480 ;
      RECT 3255.280 4.080 3256.480 1554.480 ;
    END
  END VDD
  OBS
    LAYER met1 ;
    RECT 0 0 3261.400 1558.560 ;
    LAYER met2 ;
    RECT 0 0 3261.400 1558.560 ;
    LAYER met3 ;
    RECT 0 0 3261.400 1558.560 ;
    LAYER met4 ;
    RECT 0 0 3261.400 1558.560 ;
  END
END fakeram_512x1024_1r1w

END LIBRARY
